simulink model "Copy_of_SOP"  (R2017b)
settings: Solver=FixedStepDiscrete  StartTime=0.0  StopTime=10.0  FixedStep=0.01  RelTol=1e-3  EnableMultiTasking=on
undefined symbols (not defined in the file): ASWTYPE_FALSE, ASWTYPE_TRUE, CcSOP_CellVoltLowLevel1Time_MS, CcSOP_CellVoltRngDiff_V, CcSOP_CellVoltRngDiffHeal_V, CcSOP_CellVoltRngHighTime_MS, CcSOP_CellVoltRngLowTime_MS, CcSOP_CellVoltRngUpLimit_V, CcSOP_ChrgCurrFltChrgCurrThrld_A, CcSOP_ChrgCurrFltLevel1Factor_numb, CcSOP_ChrgCurrFltLevel1Time_ms, CcSOP_ChrgCurrFltLevel2Factor_numb, CcSOP_ChrgCurrFltLevel2Time_ms, CcSOP_ChrgCurrFltLevel3Factor_numb, CcSOP_ChrgCurrFltLevel3Time_ms, CcSOP_ChrgFloorPwrLimit_kW, CcSOP_ChrgFltHysCurr_A, CcSOP_ChrgHighFactor_numb, CcSOP_ChrgLowFactor_numb, CcSOP_ChrgPwrFltPeakPwrThrld_kW, CcSOP_DisChrgEmerPwrLimit_kW, CcSOP_DisChrgFloorPwrLimit_kW, CcSOP_DisChrgHighFactor_numb, CcSOP_DisChrgLowFactor_numb, CcSOP_DischrgPwrFltLevel1Factor_numb, CcSOP_DischrgPwrFltLevel1Time_ms, CcSOP_DischrgPwrFltLevel2Factor_numb, CcSOP_DischrgPwrFltLevel2Time_ms, CcSOP_DischrgPwrFltLevel3Factor_numb, CcSOP_DischrgPwrFltLevel3Time_ms, CcSOP_DischrgPwrFltPeakPwrThrld_kW, CcSOP_DischrgPwrFltThrld_kW, CcSOP_DisChrgPwrLimit_kW, CcSOP_FeedbackPwrFltLevel1Factor_numb, CcSOP_FeedbackPwrFltLevel1Time_ms, CcSOP_FeedbackPwrFltLevel2Factor_numb, CcSOP_FeedbackPwrFltLevel2Time_ms, CcSOP_FeedbackPwrFltLevel3Factor_numb, CcSOP_FeedbackPwrFltLevel3Time_ms, CcSOP_FeedbackPwrFltThrld_kW, CcSOP_FltLimitPwrFactorLevel1_numb, CcSOP_FltLimitPwrFactorLevel2_numb, CcSOP_LookupTablePwrFactor_pct, CcSOP_MaxChrgCurrLimitFactorLevel2_numb, CcSOP_MaxCurrTableLarger_ms, CcSOP_MaxCurrTableSmaller_ms, CcSOP_PeakPowerRunTime_ms, CcSOP_PwrDownDisDetLevel1Speed_kW, CcSOP_PwrDownDisFloorFactor_numb, CcSOP_PwrDownDisFloorSpeed_kW, CcSOP_PwrDownSpeed_kW, CcSOP_PwrFltHysFactor_numb, CcSOP_PwrFltThrldTestMode_kW, CcSOP_PwrUpSpeed_kW, Enum_CTCCtrCtlConnMode, Enum_CTCCtrCtlState, Enum_MSMBMUState, Enum_SOPChrgPwrState, Enum_SOPDisChrgPwrState, Enum_SOPFeedbackPwrState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
libraries: AIWAYS_Powertrain_BMS_lib x77
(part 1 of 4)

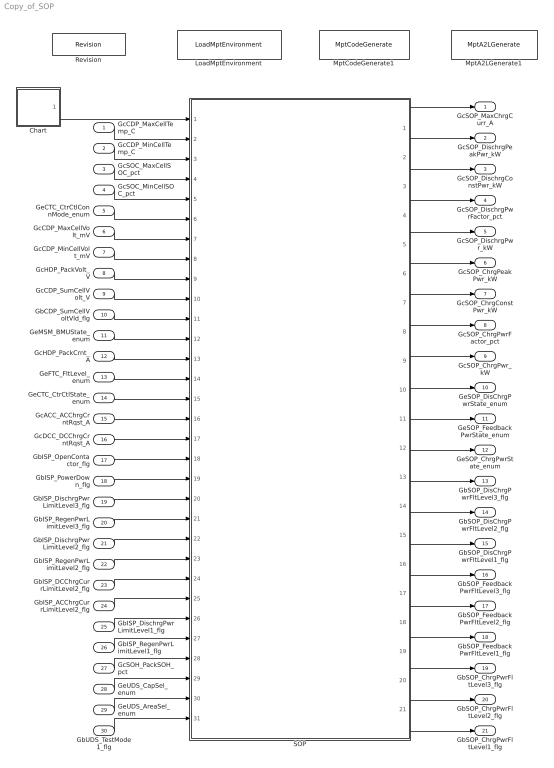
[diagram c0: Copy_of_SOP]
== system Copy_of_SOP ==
  GcCDP_MaxCellTemp_C : Inport
  GcCDP_MinCellTemp_C : Inport  Port=2
  GcSOC_MaxCellSOC_pct : Inport  Port=3
  GcSOC_MinCellSOC_pct : Inport  Port=4
  GeCTC_CtrCtlConnMode_enum : Inport  Port=5
  GcCDP_MaxCellVolt_mV : Inport  Port=6
  GcCDP_MinCellVolt_mV : Inport  Port=7
  GcHDP_PackVolt_V : Inport  Port=8
  GcCDP_SumCellVolt_V : Inport  Port=9
  GbCDP_SumCellVoltVld_flg : Inport  Port=10
  GeMSM_BMUState_enum : Inport  Port=11
  GcHDP_PackCrnt_A : Inport  Port=12
  GeFTC_FltLevel_enum : Inport  Port=13
  GeCTC_CtrCtlState_enum : Inport  Port=14
  GcACC_ACChrgCrntRqst_A : Inport  Port=15
  GcDCC_DCChrgCrntRqst_A : Inport  Port=16
  GbISP_OpenContactor_flg : Inport  Port=17
  GbISP_PowerDown_flg : Inport  Port=18
  GbISP_DischrgPwrLimitLevel3_flg : Inport  Port=19
  GbISP_RegenPwrLimitLevel3_flg : Inport  Port=20
  GbISP_DischrgPwrLimitLevel2_flg : Inport  Port=21
  GbISP_RegenPwrLimitLevel2_flg : Inport  Port=22
  GbISP_DCChrgCurrLimitLevel2_flg : Inport  Port=23
  GbISP_ACChrgCurrLimitLevel2_flg : Inport  Port=24
  GbISP_DischrgPwrLimitLevel1_flg : Inport  Port=25
  GbISP_RegenPwrLimitLevel1_flg : Inport  Port=26
  GcSOH_PackSOH_pct : Inport  Port=27
  GeUDS_CapSel_enum : Inport  Port=28
  GeUDS_AreaSel_enum : Inport  Port=29
  GbUDS_TestMode1_flg : Inport  Port=30
  Chart : Stateflow chart  TreatAsAtomicUnit=on
  LoadMptEnvironment : AIWAYS_Powertrain_BMS_lib/Config/LoadMptEnvironment  ProjectName=Comm  SuppierID=NewPlatformUAES
  MptA2LGenerate1 : AIWAYS_Powertrain_BMS_lib/Config/MptA2LGenerate  SystemSampleTime=-1
  MptCodeGenerate1 : AIWAYS_Powertrain_BMS_lib/Config/MptCodeGenerate  SystemSampleTime=-1
  Revision : AIWAYS_Powertrain_BMS_lib/Config/Revision  curVersion='M110C115R104'  newVersion='M110C115R104'
  SOP : Subsystem
  GcSOP_MaxChrgCurr_A : Outport
  GcSOP_DischrgPeakPwr_kW : Outport  Port=2
  GcSOP_DischrgConstPwr_kW : Outport  Port=3
  GcSOP_DischrgPwrFactor_pct : Outport  Port=4
  GcSOP_DischrgPwr_kW : Outport  Port=5
  GcSOP_ChrgPeakPwr_kW : Outport  Port=6
  GcSOP_ChrgConstPwr_kW : Outport  Port=7
  GcSOP_ChrgPwrFactor_pct : Outport  Port=8
  GcSOP_ChrgPwr_kW : Outport  Port=9
  GeSOP_DisChrgPwrState_enum : Outport  Port=10
  GeSOP_FeedbackPwrState_enum : Outport  Port=11
  GeSOP_ChrgPwrState_enum : Outport  Port=12
  GbSOP_DisChrgPwrFltLevel3_flg : Outport  Port=13
  GbSOP_DisChrgPwrFltLevel2_flg : Outport  Port=14
  GbSOP_DisChrgPwrFltLevel1_flg : Outport  Port=15
  GbSOP_FeedbackPwrFltLevel3_flg : Outport  Port=16
  GbSOP_FeedbackPwrFltLevel2_flg : Outport  Port=17
  GbSOP_FeedbackPwrFltLevel1_flg : Outport  Port=18
  GbSOP_ChrgPwrFltLevel3_flg : Outport  Port=19
  GbSOP_ChrgPwrFltLevel2_flg : Outport  Port=20
  GbSOP_ChrgPwrFltLevel1_flg : Outport  Port=21
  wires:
  Chart/1(SOP_SOP_10ms()) -> SOP/1(SOP_SOP_10ms)
  GcCDP_MaxCellTemp_C/1 -> SOP/2(GcCDP_MaxCellTemp_C)
  GcCDP_MinCellTemp_C/1 -> SOP/3(GcCDP_MinCellTemp_C)
  GcSOC_MaxCellSOC_pct/1 -> SOP/4(GcSOC_MaxCellSOC_pct)
  GcSOC_MinCellSOC_pct/1 -> SOP/5(GcSOC_MinCellSOC_pct)
  GeCTC_CtrCtlConnMode_enum/1 -> SOP/6(GeCTC_CtrCtlConnMode_enum)
  GcCDP_MaxCellVolt_mV/1 -> SOP/7(GcCDP_MaxCellVolt_mV)
  GcCDP_MinCellVolt_mV/1 -> SOP/8(GcCDP_MinCellVolt_mV)
  GcHDP_PackVolt_V/1 -> SOP/9(GcHDP_PackVolt_V)
  GcCDP_SumCellVolt_V/1 -> SOP/10(GcCDP_SumCellVolt_V)
  GbCDP_SumCellVoltVld_flg/1 -> SOP/11(GbCDP_SumCellVoltVld_flg)
  GeMSM_BMUState_enum/1 -> SOP/12(GeMSM_BMUState_enum)
  GcHDP_PackCrnt_A/1 -> SOP/13(GcHDP_PackCrnt_A)
  GeFTC_FltLevel_enum/1 -> SOP/14(GeFTC_FltLevel_enum)
  GeCTC_CtrCtlState_enum/1 -> SOP/15(GeCTC_CtrCtlState_enum)
  GcACC_ACChrgCrntRqst_A/1 -> SOP/16(GcACC_ACChrgCrntRqst_A)
  GcDCC_DCChrgCrntRqst_A/1 -> SOP/17(GcDCC_DCChrgCrntRqst_A)
  SOP/1(GcSOP_MaxChrgCurr_A) -> GcSOP_MaxChrgCurr_A/1
  SOP/2(GcSOP_DischrgPeakPwr_kW) -> GcSOP_DischrgPeakPwr_kW/1
  SOP/3(GcSOP_DischrgConstPwr_kW) -> GcSOP_DischrgConstPwr_kW/1
  SOP/4(GcSOP_DischrgPwrFactor_pct) -> GcSOP_DischrgPwrFactor_pct/1
  SOP/5(GcSOP_DischrgPwr_kW) -> GcSOP_DischrgPwr_kW/1
  SOP/6(GcSOP_ChrgPeakPwr_kW) -> GcSOP_ChrgPeakPwr_kW/1
  SOP/7(GcSOP_ChrgConstPwr_kW) -> GcSOP_ChrgConstPwr_kW/1
  SOP/8(GcSOP_ChrgPwrFactor_pct) -> GcSOP_ChrgPwrFactor_pct/1
  SOP/9(GcSOP_ChrgPwr_kW) -> GcSOP_ChrgPwr_kW/1
  SOP/10(GeSOP_DisChrgPwrState_enum) -> GeSOP_DisChrgPwrState_enum/1
  SOP/11(GeSOP_FeedbackPwrState_enum) -> GeSOP_FeedbackPwrState_enum/1
  SOP/12(GeSOP_ChrgPwrState_enum) -> GeSOP_ChrgPwrState_enum/1
  GbISP_OpenContactor_flg/1 -> SOP/18(GbISP_OpenContactor_flg)
  GbISP_PowerDown_flg/1 -> SOP/19(GbISP_PowerDown_flg)
  GbISP_DischrgPwrLimitLevel3_flg/1 -> SOP/20(GbISP_DischrgPwrLimitLevel3_flg)
  GbISP_RegenPwrLimitLevel3_flg/1 -> SOP/21(GbISP_RegenPwrLimitLevel3_flg)
  GbISP_DischrgPwrLimitLevel2_flg/1 -> SOP/22(GbISP_DischrgPwrLimitLevel2_flg)
  GbISP_RegenPwrLimitLevel2_flg/1 -> SOP/23(GbISP_RegenPwrLimitLevel2_flg)
  GbISP_DCChrgCurrLimitLevel2_flg/1 -> SOP/24(GbISP_DCChrgCurrLimitLevel2_flg)
  GbISP_ACChrgCurrLimitLevel2_flg/1 -> SOP/25(GbISP_ACChrgCurrLimitLevel2_flg)
  GbISP_DischrgPwrLimitLevel1_flg/1 -> SOP/26(GbISP_DischrgPwrLimitLevel1_flg)
  GbISP_RegenPwrLimitLevel1_flg/1 -> SOP/27(GbISP_RegenPwrLimitLevel1_flg)
  SOP/13(GbSOP_DisChrgPwrFltLevel3_flg) -> GbSOP_DisChrgPwrFltLevel3_flg/1
  SOP/14(GbSOP_DisChrgPwrFltLevel2_flg) -> GbSOP_DisChrgPwrFltLevel2_flg/1
  SOP/15(GbSOP_DisChrgPwrFltLevel1_flg) -> GbSOP_DisChrgPwrFltLevel1_flg/1
  SOP/16(GbSOP_FeedbackPwrFltLevel3_flg) -> GbSOP_FeedbackPwrFltLevel3_flg/1
  SOP/17(GbSOP_FeedbackPwrFltLevel2_flg) -> GbSOP_FeedbackPwrFltLevel2_flg/1
  SOP/18(GbSOP_FeedbackPwrFltLevel1_flg) -> GbSOP_FeedbackPwrFltLevel1_flg/1
  SOP/19(GbSOP_ChrgPwrFltLevel3_flg) -> GbSOP_ChrgPwrFltLevel3_flg/1
  SOP/20(GbSOP_ChrgPwrFltLevel2_flg) -> GbSOP_ChrgPwrFltLevel2_flg/1
  SOP/21(GbSOP_ChrgPwrFltLevel1_flg) -> GbSOP_ChrgPwrFltLevel1_flg/1
  GcSOH_PackSOH_pct/1 -> SOP/28(GcSOH_PackSOH_pct)
  GeUDS_CapSel_enum/1 -> SOP/29(GeUDS_CapSel_enum)
  GeUDS_AreaSel_enum/1 -> SOP/30(GeUDS_AreaSel_enum)
  GbUDS_TestMode1_flg/1 -> SOP/31(GbUDS_TestMode1_flg)

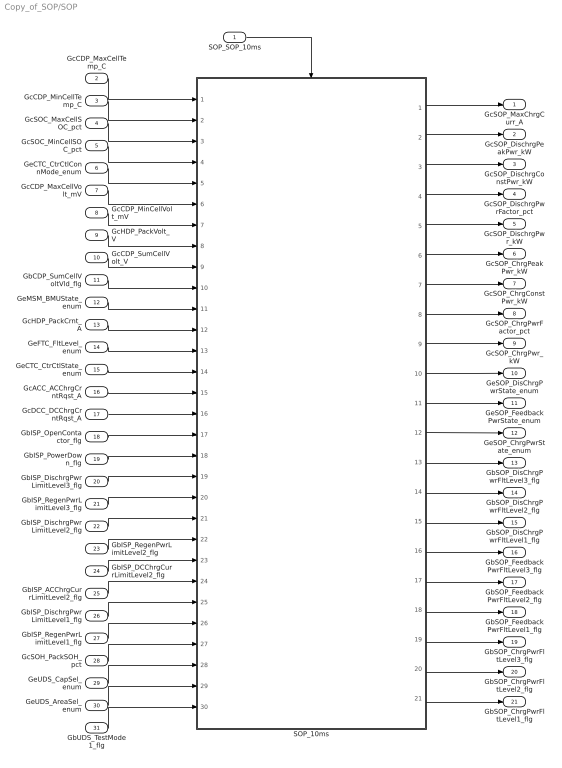
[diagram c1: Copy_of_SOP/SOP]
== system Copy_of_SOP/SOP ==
  SOP_SOP_10ms : Inport
  GcCDP_MaxCellTemp_C : Inport  Port=2
  GcCDP_MinCellTemp_C : Inport  Port=3
  GcSOC_MaxCellSOC_pct : Inport  Port=4
  GcSOC_MinCellSOC_pct : Inport  Port=5
  GeCTC_CtrCtlConnMode_enum : Inport  Port=6
  GcCDP_MaxCellVolt_mV : Inport  Port=7
  GcCDP_MinCellVolt_mV : Inport  Port=8
  GcHDP_PackVolt_V : Inport  Port=9
  GcCDP_SumCellVolt_V : Inport  Port=10
  GbCDP_SumCellVoltVld_flg : Inport  Port=11
  GeMSM_BMUState_enum : Inport  Port=12
  GcHDP_PackCrnt_A : Inport  Port=13
  GeFTC_FltLevel_enum : Inport  Port=14
  GeCTC_CtrCtlState_enum : Inport  Port=15
  GcACC_ACChrgCrntRqst_A : Inport  Port=16
  GcDCC_DCChrgCrntRqst_A : Inport  Port=17
  GbISP_OpenContactor_flg : Inport  Port=18
  GbISP_PowerDown_flg : Inport  Port=19
  GbISP_DischrgPwrLimitLevel3_flg : Inport  Port=20
  GbISP_RegenPwrLimitLevel3_flg : Inport  Port=21
  GbISP_DischrgPwrLimitLevel2_flg : Inport  Port=22
  GbISP_RegenPwrLimitLevel2_flg : Inport  Port=23
  GbISP_DCChrgCurrLimitLevel2_flg : Inport  Port=24
  GbISP_ACChrgCurrLimitLevel2_flg : Inport  Port=25
  GbISP_DischrgPwrLimitLevel1_flg : Inport  Port=26
  GbISP_RegenPwrLimitLevel1_flg : Inport  Port=27
  GcSOH_PackSOH_pct : Inport  Port=28
  GeUDS_CapSel_enum : Inport  Port=29
  GeUDS_AreaSel_enum : Inport  Port=30
  GbUDS_TestMode1_flg : Inport  Port=31
  SOP_10ms : Subsystem  TreatAsAtomicUnit=on
  GcSOP_MaxChrgCurr_A : Outport
  GcSOP_DischrgPeakPwr_kW : Outport  Port=2
  GcSOP_DischrgConstPwr_kW : Outport  Port=3
  GcSOP_DischrgPwrFactor_pct : Outport  Port=4
  GcSOP_DischrgPwr_kW : Outport  Port=5
  GcSOP_ChrgPeakPwr_kW : Outport  Port=6
  GcSOP_ChrgConstPwr_kW : Outport  Port=7
  GcSOP_ChrgPwrFactor_pct : Outport  Port=8
  GcSOP_ChrgPwr_kW : Outport  Port=9
  GeSOP_DisChrgPwrState_enum : Outport  Port=10
  GeSOP_FeedbackPwrState_enum : Outport  Port=11
  GeSOP_ChrgPwrState_enum : Outport  Port=12
  GbSOP_DisChrgPwrFltLevel3_flg : Outport  Port=13
  GbSOP_DisChrgPwrFltLevel2_flg : Outport  Port=14
  GbSOP_DisChrgPwrFltLevel1_flg : Outport  Port=15
  GbSOP_FeedbackPwrFltLevel3_flg : Outport  Port=16
  GbSOP_FeedbackPwrFltLevel2_flg : Outport  Port=17
  GbSOP_FeedbackPwrFltLevel1_flg : Outport  Port=18
  GbSOP_ChrgPwrFltLevel3_flg : Outport  Port=19
  GbSOP_ChrgPwrFltLevel2_flg : Outport  Port=20
  GbSOP_ChrgPwrFltLevel1_flg : Outport  Port=21
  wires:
  SOP_SOP_10ms/1 -> SOP_10ms/Trigger
  SOP_10ms/1(GcSOP_MaxChrgCurr_A) -> GcSOP_MaxChrgCurr_A/1
  SOP_10ms/2(GcSOP_DischrgPeakPwr_kW) -> GcSOP_DischrgPeakPwr_kW/1
  SOP_10ms/3(GcSOP_DischrgConstPwr_kW) -> GcSOP_DischrgConstPwr_kW/1
  SOP_10ms/4(GcSOP_DischrgPwrFactor_pct) -> GcSOP_DischrgPwrFactor_pct/1
  SOP_10ms/5(GcSOP_DischrgPwr_kW) -> GcSOP_DischrgPwr_kW/1
  SOP_10ms/6(GcSOP_ChrgPeakPwr_kW) -> GcSOP_ChrgPeakPwr_kW/1
  SOP_10ms/7(GcSOP_ChrgConstPwr_kW) -> GcSOP_ChrgConstPwr_kW/1
  SOP_10ms/8(GcSOP_ChrgPwrFactor_pct) -> GcSOP_ChrgPwrFactor_pct/1
  SOP_10ms/9(GcSOP_ChrgPwr_kW) -> GcSOP_ChrgPwr_kW/1
  SOP_10ms/10(GeSOP_DisChrgPwrState_enum) -> GeSOP_DisChrgPwrState_enum/1
  SOP_10ms/11(GeSOP_FeedbackPwrState_enum) -> GeSOP_FeedbackPwrState_enum/1
  SOP_10ms/12(GeSOP_ChrgPwrState_enum) -> GeSOP_ChrgPwrState_enum/1
  GcCDP_MaxCellTemp_C/1 -> SOP_10ms/1(GcCDP_MaxCellTemp_C)
  GcCDP_MinCellTemp_C/1 -> SOP_10ms/2(GcCDP_MinCellTemp_C)
  GcSOC_MaxCellSOC_pct/1 -> SOP_10ms/3(GcSOC_MaxCellSOC_pct)
  GcSOC_MinCellSOC_pct/1 -> SOP_10ms/4(GcSOC_MinCellSOC_pct)
  GeCTC_CtrCtlConnMode_enum/1 -> SOP_10ms/5(GeCTC_CtrCtlConnMode_enum)
  GcCDP_MaxCellVolt_mV/1 -> SOP_10ms/6(GcCDP_MaxCellVolt_mV)
  GcCDP_MinCellVolt_mV/1 -> SOP_10ms/7(GcCDP_MinCellVolt_mV)
  GcHDP_PackVolt_V/1 -> SOP_10ms/8(GcHDP_PackVolt_V)
  GcCDP_SumCellVolt_V/1 -> SOP_10ms/9(GcCDP_SumCellVolt_V)
  GbCDP_SumCellVoltVld_flg/1 -> SOP_10ms/10(GbCDP_SumCellVoltVld_flg)
  GeMSM_BMUState_enum/1 -> SOP_10ms/11(GeMSM_BMUState_enum)
  GcHDP_PackCrnt_A/1 -> SOP_10ms/12(GcHDP_PackCrnt_A)
  GeFTC_FltLevel_enum/1 -> SOP_10ms/13(GeFTC_FltLevel_enum)
  GeCTC_CtrCtlState_enum/1 -> SOP_10ms/14(GeCTC_CtrCtlState_enum)
  GcACC_ACChrgCrntRqst_A/1 -> SOP_10ms/15(GcACC_ACChrgCrntRqst_A)
  GcDCC_DCChrgCrntRqst_A/1 -> SOP_10ms/16(GcDCC_DCChrgCrntRqst_A)
  GbISP_OpenContactor_flg/1 -> SOP_10ms/17(GbISP_OpenContactor_flg)
  GbISP_PowerDown_flg/1 -> SOP_10ms/18(GbISP_PowerDown_flg)
  GbISP_DischrgPwrLimitLevel3_flg/1 -> SOP_10ms/19(GbISP_DischrgPwrLimitLevel3_flg)
  GbISP_RegenPwrLimitLevel3_flg/1 -> SOP_10ms/20(GbISP_RegenPwrLimitLevel3_flg)
  GbISP_DischrgPwrLimitLevel2_flg/1 -> SOP_10ms/21(GbISP_DischrgPwrLimitLevel2_flg)
  GbISP_RegenPwrLimitLevel2_flg/1 -> SOP_10ms/22(GbISP_RegenPwrLimitLevel2_flg)
  GbISP_DCChrgCurrLimitLevel2_flg/1 -> SOP_10ms/23(GbISP_DCChrgCurrLimitLevel2_flg)
  GbISP_ACChrgCurrLimitLevel2_flg/1 -> SOP_10ms/24(GbISP_ACChrgCurrLimitLevel2_flg)
  GbISP_DischrgPwrLimitLevel1_flg/1 -> SOP_10ms/25(GbISP_DischrgPwrLimitLevel1_flg)
  GbISP_RegenPwrLimitLevel1_flg/1 -> SOP_10ms/26(GbISP_RegenPwrLimitLevel1_flg)
  SOP_10ms/13(GbSOP_DisChrgPwrFltLevel3_flg) -> GbSOP_DisChrgPwrFltLevel3_flg/1
  SOP_10ms/14(GbSOP_DisChrgPwrFltLevel2_flg) -> GbSOP_DisChrgPwrFltLevel2_flg/1
  SOP_10ms/15(GbSOP_DisChrgPwrFltLevel1_flg) -> GbSOP_DisChrgPwrFltLevel1_flg/1
  SOP_10ms/16(GbSOP_FeedbackPwrFltLevel3_flg) -> GbSOP_FeedbackPwrFltLevel3_flg/1
  SOP_10ms/17(GbSOP_FeedbackPwrFltLevel2_flg) -> GbSOP_FeedbackPwrFltLevel2_flg/1
  SOP_10ms/18(GbSOP_FeedbackPwrFltLevel1_flg) -> GbSOP_FeedbackPwrFltLevel1_flg/1
  SOP_10ms/19(GbSOP_ChrgPwrFltLevel3_flg) -> GbSOP_ChrgPwrFltLevel3_flg/1
  SOP_10ms/20(GbSOP_ChrgPwrFltLevel2_flg) -> GbSOP_ChrgPwrFltLevel2_flg/1
  SOP_10ms/21(GbSOP_ChrgPwrFltLevel1_flg) -> GbSOP_ChrgPwrFltLevel1_flg/1
  GcSOH_PackSOH_pct/1 -> SOP_10ms/27(GcSOH_PackSOH_pct)
  GeUDS_CapSel_enum/1 -> SOP_10ms/28(GeUDS_CapSel_enum)
  GeUDS_AreaSel_enum/1 -> SOP_10ms/29(GeUDS_AreaSel_enum)
  GbUDS_TestMode1_flg/1 -> SOP_10ms/30(GbUDS_TestMode1_flg)

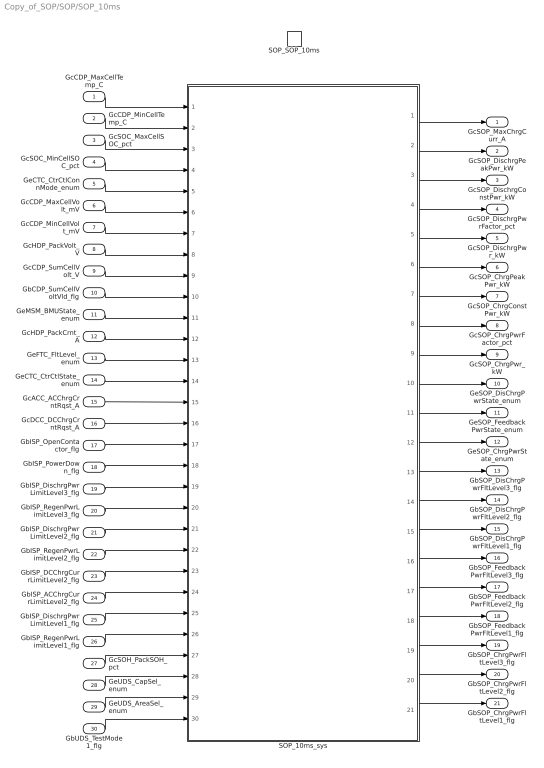
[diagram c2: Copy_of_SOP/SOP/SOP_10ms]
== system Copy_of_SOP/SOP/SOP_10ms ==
  GcCDP_MaxCellTemp_C : Inport
  GcCDP_MinCellTemp_C : Inport  Port=2
  GcSOC_MaxCellSOC_pct : Inport  Port=3
  GcSOC_MinCellSOC_pct : Inport  Port=4
  GeCTC_CtrCtlConnMode_enum : Inport  Port=5
  GcCDP_MaxCellVolt_mV : Inport  Port=6
  GcCDP_MinCellVolt_mV : Inport  Port=7
  GcHDP_PackVolt_V : Inport  Port=8
  GcCDP_SumCellVolt_V : Inport  Port=9
  GbCDP_SumCellVoltVld_flg : Inport  Port=10
  GeMSM_BMUState_enum : Inport  Port=11
  GcHDP_PackCrnt_A : Inport  Port=12
  GeFTC_FltLevel_enum : Inport  Port=13
  GeCTC_CtrCtlState_enum : Inport  Port=14
  GcACC_ACChrgCrntRqst_A : Inport  Port=15
  GcDCC_DCChrgCrntRqst_A : Inport  Port=16
  GbISP_OpenContactor_flg : Inport  Port=17
  GbISP_PowerDown_flg : Inport  Port=18
  GbISP_DischrgPwrLimitLevel3_flg : Inport  Port=19
  GbISP_RegenPwrLimitLevel3_flg : Inport  Port=20
  GbISP_DischrgPwrLimitLevel2_flg : Inport  Port=21
  GbISP_RegenPwrLimitLevel2_flg : Inport  Port=22
  GbISP_DCChrgCurrLimitLevel2_flg : Inport  Port=23
  GbISP_ACChrgCurrLimitLevel2_flg : Inport  Port=24
  GbISP_DischrgPwrLimitLevel1_flg : Inport  Port=25
  GbISP_RegenPwrLimitLevel1_flg : Inport  Port=26
  GcSOH_PackSOH_pct : Inport  Port=27
  GeUDS_CapSel_enum : Inport  Port=28
  GeUDS_AreaSel_enum : Inport  Port=29
  GbUDS_TestMode1_flg : Inport  Port=30
  SOP_SOP_10ms : TriggerPort  TriggerType=function-call  VariantControl=(inherit)  SampleTime=-1
  SOP_10ms_sys : Subsystem  Tag=MTestTObj
  GcSOP_MaxChrgCurr_A : Outport
  GcSOP_DischrgPeakPwr_kW : Outport  Port=2
  GcSOP_DischrgConstPwr_kW : Outport  Port=3
  GcSOP_DischrgPwrFactor_pct : Outport  Port=4
  GcSOP_DischrgPwr_kW : Outport  Port=5
  GcSOP_ChrgPeakPwr_kW : Outport  Port=6
  GcSOP_ChrgConstPwr_kW : Outport  Port=7
  GcSOP_ChrgPwrFactor_pct : Outport  Port=8
  GcSOP_ChrgPwr_kW : Outport  Port=9
  GeSOP_DisChrgPwrState_enum : Outport  Port=10
  GeSOP_FeedbackPwrState_enum : Outport  Port=11
  GeSOP_ChrgPwrState_enum : Outport  Port=12
  GbSOP_DisChrgPwrFltLevel3_flg : Outport  Port=13
  GbSOP_DisChrgPwrFltLevel2_flg : Outport  Port=14
  GbSOP_DisChrgPwrFltLevel1_flg : Outport  Port=15
  GbSOP_FeedbackPwrFltLevel3_flg : Outport  Port=16
  GbSOP_FeedbackPwrFltLevel2_flg : Outport  Port=17
  GbSOP_FeedbackPwrFltLevel1_flg : Outport  Port=18
  GbSOP_ChrgPwrFltLevel3_flg : Outport  Port=19
  GbSOP_ChrgPwrFltLevel2_flg : Outport  Port=20
  GbSOP_ChrgPwrFltLevel1_flg : Outport  Port=21
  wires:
  GcSOC_MinCellSOC_pct/1 -> SOP_10ms_sys/4(GcSOC_MinCellSOC_pct)
  GcSOC_MaxCellSOC_pct/1 -> SOP_10ms_sys/3(GcSOC_MaxCellSOC_pct)
  GcCDP_MinCellTemp_C/1 -> SOP_10ms_sys/2(GcCDP_MinCellTemp_C)
  GcCDP_MaxCellTemp_C/1 -> SOP_10ms_sys/1(GcCDP_MaxCellTemp_C)
  GeCTC_CtrCtlConnMode_enum/1 -> SOP_10ms_sys/5(GeCTC_CtrCtlConnMode_enum)
  GcHDP_PackVolt_V/1 -> SOP_10ms_sys/8(GcHDP_PackVolt_V)
  GeMSM_BMUState_enum/1 -> SOP_10ms_sys/11(GeMSM_BMUState_enum)
  GeCTC_CtrCtlState_enum/1 -> SOP_10ms_sys/14(GeCTC_CtrCtlState_enum)
  GeFTC_FltLevel_enum/1 -> SOP_10ms_sys/13(GeFTC_FltLevel_enum)
  GcHDP_PackCrnt_A/1 -> SOP_10ms_sys/12(GcHDP_PackCrnt_A)
  SOP_10ms_sys/1(GcSOP_MaxChrgCurr_A) -> GcSOP_MaxChrgCurr_A/1
  SOP_10ms_sys/2(GcSOP_DischrgPeakPwr_kW) -> GcSOP_DischrgPeakPwr_kW/1
  SOP_10ms_sys/3(GcSOP_DischrgConstPwr_kW) -> GcSOP_DischrgConstPwr_kW/1
  SOP_10ms_sys/4(GcSOP_DischrgPwrFactor_pct) -> GcSOP_DischrgPwrFactor_pct/1
  SOP_10ms_sys/5(GcSOP_DischrgPwr_kW) -> GcSOP_DischrgPwr_kW/1
  SOP_10ms_sys/6(GcSOP_ChrgPeakPwr_kW) -> GcSOP_ChrgPeakPwr_kW/1
  SOP_10ms_sys/7(GcSOP_ChrgConstPwr_kW) -> GcSOP_ChrgConstPwr_kW/1
  SOP_10ms_sys/8(GcSOP_ChrgPwrFactor_pct) -> GcSOP_ChrgPwrFactor_pct/1
  SOP_10ms_sys/9(GcSOP_ChrgPwr_kW) -> GcSOP_ChrgPwr_kW/1
  GcACC_ACChrgCrntRqst_A/1 -> SOP_10ms_sys/15(GcACC_ACChrgCrntRqst_A)
  GcDCC_DCChrgCrntRqst_A/1 -> SOP_10ms_sys/16(GcDCC_DCChrgCrntRqst_A)
  SOP_10ms_sys/10(GeSOP_DisChrgPwrState_enum) -> GeSOP_DisChrgPwrState_enum/1
  SOP_10ms_sys/11(GeSOP_FeedbackPwrState_enum) -> GeSOP_FeedbackPwrState_enum/1
  SOP_10ms_sys/12(GeSOP_ChrgPwrState_enum) -> GeSOP_ChrgPwrState_enum/1
  GcCDP_MaxCellVolt_mV/1 -> SOP_10ms_sys/6(GcCDP_MaxCellVolt_mV)
  GcCDP_MinCellVolt_mV/1 -> SOP_10ms_sys/7(GcCDP_MinCellVolt_mV)
  GcCDP_SumCellVolt_V/1 -> SOP_10ms_sys/9(GcCDP_SumCellVolt_V)
  GbCDP_SumCellVoltVld_flg/1 -> SOP_10ms_sys/10(GbCDP_SumCellVoltVld_flg)
  GbISP_OpenContactor_flg/1 -> SOP_10ms_sys/17(GbISP_OpenContactor_flg)
  GbISP_PowerDown_flg/1 -> SOP_10ms_sys/18(GbISP_PowerDown_flg)
  GbISP_DischrgPwrLimitLevel3_flg/1 -> SOP_10ms_sys/19(GbISP_DischrgPwrLimitLevel3_flg)
  GbISP_RegenPwrLimitLevel3_flg/1 -> SOP_10ms_sys/20(GbISP_RegenPwrLimitLevel3_flg)
  GbISP_DischrgPwrLimitLevel2_flg/1 -> SOP_10ms_sys/21(GbISP_DischrgPwrLimitLevel2_flg)
  GbISP_RegenPwrLimitLevel2_flg/1 -> SOP_10ms_sys/22(GbISP_RegenPwrLimitLevel2_flg)
  GbISP_DCChrgCurrLimitLevel2_flg/1 -> SOP_10ms_sys/23(GbISP_DCChrgCurrLimitLevel2_flg)
  GbISP_ACChrgCurrLimitLevel2_flg/1 -> SOP_10ms_sys/24(GbISP_ACChrgCurrLimitLevel2_flg)
  GbISP_DischrgPwrLimitLevel1_flg/1 -> SOP_10ms_sys/25(GbISP_DischrgPwrLimitLevel1_flg)
  GbISP_RegenPwrLimitLevel1_flg/1 -> SOP_10ms_sys/26(GbISP_RegenPwrLimitLevel1_flg)
  SOP_10ms_sys/13(GbSOP_DisChrgPwrFltLevel3_flg) -> GbSOP_DisChrgPwrFltLevel3_flg/1
  SOP_10ms_sys/14(GbSOP_DisChrgPwrFltLevel2_flg) -> GbSOP_DisChrgPwrFltLevel2_flg/1
  SOP_10ms_sys/15(GbSOP_DisChrgPwrFltLevel1_flg) -> GbSOP_DisChrgPwrFltLevel1_flg/1
  SOP_10ms_sys/16(GbSOP_FeedbackPwrFltLevel3_flg) -> GbSOP_FeedbackPwrFltLevel3_flg/1
  SOP_10ms_sys/17(GbSOP_FeedbackPwrFltLevel2_flg) -> GbSOP_FeedbackPwrFltLevel2_flg/1
  SOP_10ms_sys/18(GbSOP_FeedbackPwrFltLevel1_flg) -> GbSOP_FeedbackPwrFltLevel1_flg/1
  SOP_10ms_sys/19(GbSOP_ChrgPwrFltLevel3_flg) -> GbSOP_ChrgPwrFltLevel3_flg/1
  SOP_10ms_sys/20(GbSOP_ChrgPwrFltLevel2_flg) -> GbSOP_ChrgPwrFltLevel2_flg/1
  SOP_10ms_sys/21(GbSOP_ChrgPwrFltLevel1_flg) -> GbSOP_ChrgPwrFltLevel1_flg/1
  GcSOH_PackSOH_pct/1 -> SOP_10ms_sys/27(GcSOH_PackSOH_pct)
  GeUDS_CapSel_enum/1 -> SOP_10ms_sys/28(GeUDS_CapSel_enum)
  GeUDS_AreaSel_enum/1 -> SOP_10ms_sys/29(GeUDS_AreaSel_enum)
  GbUDS_TestMode1_flg/1 -> SOP_10ms_sys/30(GbUDS_TestMode1_flg)

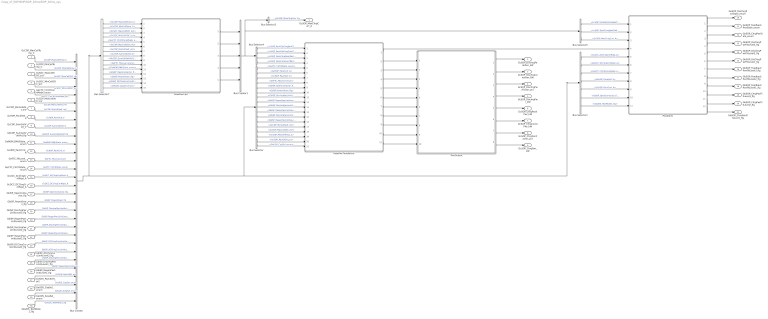
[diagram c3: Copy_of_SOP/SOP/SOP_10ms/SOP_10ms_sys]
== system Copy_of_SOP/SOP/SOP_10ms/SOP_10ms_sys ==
  GcCDP_MaxCellTemp_C : Inport
  GcCDP_MinCellTemp_C : Inport  Port=2
  GcSOC_MaxCellSOC_pct : Inport  Port=3
  GcSOC_MinCellSOC_pct : Inport  Port=4
  GeCTC_CtrCtlConnMode_enum : Inport  Port=5
  GcCDP_MaxCellVolt_mV : Inport  Port=6
  GcCDP_MinCellVolt_mV : Inport  Port=7
  GcHDP_PackVolt_V : Inport  Port=8
  GcCDP_SumCellVolt_V : Inport  Port=9
  GbCDP_SumCellVoltVld_flg : Inport  Port=10
  GeMSM_BMUState_enum : Inport  Port=11
  GcHDP_PackCrnt_A : Inport  Port=12
  GeFTC_FltLevel_enum : Inport  Port=13
  GeCTC_CtrCtlState_enum : Inport  Port=14
  GcACC_ACChrgCrntRqst_A : Inport  Port=15
  GcDCC_DCChrgCrntRqst_A : Inport  Port=16
  GbISP_OpenContactor_flg : Inport  Port=17
  GbISP_PowerDown_flg : Inport  Port=18
  GbISP_DischrgPwrLimitLevel3_flg : Inport  Port=19
  GbISP_RegenPwrLimitLevel3_flg : Inport  Port=20
  GbISP_DischrgPwrLimitLevel2_flg : Inport  Port=21
  GbISP_RegenPwrLimitLevel2_flg : Inport  Port=22
  GbISP_DCChrgCurrLimitLevel2_flg : Inport  Port=23
  GbISP_ACChrgCurrLimitLevel2_flg : Inport  Port=24
  GbISP_DischrgPwrLimitLevel1_flg : Inport  Port=25
  GbISP_RegenPwrLimitLevel1_flg : Inport  Port=26
  GcSOH_PackSOH_pct : Inport  Port=27
  GeUDS_CapSel_enum : Inport  Port=28
  GeUDS_AreaSel_enum : Inport  Port=29
  GbUDS_TestMode1_flg : Inport  Port=30
  Bus Creator : BusCreator  Inputs=30
  Bus Creator1 : BusCreator  Inputs=5
  Bus Selector : BusSelector  OutputSignals=GeCTC_CtrCtlState_enum,GcHDP_PackCrnt_A,GcHDP_PackVolt_V,GeFTC_FltLevel_enum,GbISP_OpenContactor_flg,GbISP_PowerDown_flg,GbISP_DischrgPwrLimitLevel3_flg,GbISP_RegenPwrLimitLevel3_flg,GbISP_DischrgPwrLimitLevel2_flg,GbISP_RegenPwrLimitLevel2_flg,GbISP_DischrgPwrLimitLevel1_flg,GbISP_RegenPwrLimitLevel1_flg,GcCDP_MinCellVolt_mV,GcCDP_MaxCellVolt_mV,GcCDP_MinCellTemp_C,GcSOH_PackSOH_pct,GeUDS_CapSel_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
  Bus Selector1 : BusSelector  OutputSignals=GcACC_ACChrgCrntRqst_A,GcDCC_DCChrgCrntRqst_A,GeCTC_CtrCtlConnMode_enum,GcHDP_PackVolt_V,GcHDP_PackCrnt_A,GbISP_OpenContactor_flg,GbUDS_TestMode1_flg
  Bus Selector3 : BusSelector  OutputSignals=GcSOP_MaxChrgCurr_A
  Bus Selector4 : BusSelector  OutputSignals=LcSOP_PackDisChrgPeakTablePwr_kW,LcSOP_PackDisChrgContTablePwr_kW,LcSOP_PackChrgPeakTablePwr_kW,LcSOP_PackChrgContTablePwr_kW
  Bus Selector5 : BusSelector  OutputSignals=LcSOP_PackDisChrgPeakTablePwr_kW,LcSOP_PackChrgPeakTablePwr_kW,GcSOP_MaxChrgCurr_A
  Bus Selector7 : BusSelector  OutputSignals=GcCDP_MaxCellTemp_C,GcCDP_MinCellTemp_C,GcSOC_MaxCellSOC_pct,GcSOC_MinCellSOC_pct,GeCTC_CtrCtlConnMode_enum,GcCDP_MaxCellVolt_mV,GcCDP_MinCellVolt_mV,GcCDP_SumCellVolt_V,GbCDP_SumCellVoltVld_flg,GeFTC_FltLevel_enum,GeMSM_BMUState_enum,GbISP_OpenContactor_flg,GbISP_PowerDown_flg,GbISP_DCChrgCurrLimitLevel2_flg,GeUDS_CapSel_enum
  PeakPwrCacl : Subsystem
  PeakPwrTimeFactor : Subsystem
  PwrAlarm : Subsystem
  PwrOutput : Subsystem
  GcSOP_MaxChrgCurr_A : Outport
  GcSOP_DischrgPeakPwr_kW : Outport  Port=2
  GcSOP_DischrgConstPwr_kW : Outport  Port=3
  GcSOP_DischrgPwrFactor_pct : Outport  Port=4
  GcSOP_DischrgPwr_kW : Outport  Port=5
  GcSOP_ChrgPeakPwr_kW : Outport  Port=6
  GcSOP_ChrgConstPwr_kW : Outport  Port=7
  GcSOP_ChrgPwrFactor_pct : Outport  Port=8
  GcSOP_ChrgPwr_kW : Outport  Port=9
  GeSOP_DisChrgPwrState_enum : Outport  Port=10
  GeSOP_FeedbackPwrState_enum : Outport  Port=11
  GeSOP_ChrgPwrState_enum : Outport  Port=12
  GbSOP_DisChrgPwrFltLevel3_flg : Outport  Port=13
  GbSOP_DisChrgPwrFltLevel2_flg : Outport  Port=14
  GbSOP_DisChrgPwrFltLevel1_flg : Outport  Port=15
  GbSOP_FeedbackPwrFltLevel3_flg : Outport  Port=16
  GbSOP_FeedbackPwrFltLevel2_flg : Outport  Port=17
  GbSOP_FeedbackPwrFltLevel1_flg : Outport  Port=18
  GbSOP_ChrgPwrFltLevel3_flg : Outport  Port=19
  GbSOP_ChrgPwrFltLevel2_flg : Outport  Port=20
  GbSOP_ChrgPwrFltLevel1_flg : Outport  Port=21
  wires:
  Bus Selector1/3 -> PwrAlarm/7(GeCTC_CtrCtlConnMode_enum)  "<GeCTC_CtrCtlConnMode_enum>"
  PwrAlarm/3(GeSOP_ChrgPwrState_enum) -> GeSOP_ChrgPwrState_enum/1
  PwrAlarm/2(GeSOP_FeedbackPwrState_enum) -> GeSOP_FeedbackPwrState_enum/1
  PwrAlarm/1(GeSOP_DisChrgPwrState_enum) -> GeSOP_DisChrgPwrState_enum/1
  Bus Selector1/4 -> PwrAlarm/8(GcHDP_PackVolt_V)  "<GcHDP_PackVolt_V>"
  Bus Selector1/5 -> PwrAlarm/9(GcHDP_PackCrnt_A)  "<GcHDP_PackCrnt_A>"
  PeakPwrCacl/5(GcSOP_MaxChrgCurr_A) -> Bus Creator1/5
  Bus Selector/2 -> PeakPwrTimeFactor/6(GcHDP_PackCrnt_A)  "<GcHDP_PackCrnt_A>"
  Bus Selector/4 -> PeakPwrTimeFactor/8(GeFTC_FltLevel_enum)  "<GeFTC_FltLevel_enum>"
  Bus Selector/3 -> PeakPwrTimeFactor/7(GcHDP_PackVolt_V)  "<GcHDP_PackVolt_V>"
  PwrOutput/2(GcSOP_DischrgConstPwr_kW) -> GcSOP_DischrgConstPwr_kW/1
  PwrOutput/3(GcSOP_DischrgPwrFactor_pct) -> GcSOP_DischrgPwrFactor_pct/1
  PwrOutput/4(GcSOP_DischrgPwr_kW) -> GcSOP_DischrgPwr_kW/1
  PwrOutput/5(GcSOP_ChrgPeakPwr_kW) -> GcSOP_ChrgPeakPwr_kW/1
  PwrOutput/6(GcSOP_ChrgConstPwr_kW) -> GcSOP_ChrgConstPwr_kW/1
  PwrOutput/7(GcSOP_ChrgPwrFactor_pct) -> GcSOP_ChrgPwrFactor_pct/1
  PwrOutput/8(GcSOP_ChrgPwr_kW) -> GcSOP_ChrgPwr_kW/1
  PwrOutput/1(GcSOP_DischrgPeakPwr_kW) -> GcSOP_DischrgPeakPwr_kW/1
  PeakPwrTimeFactor/7(LcSOP_ChrgPwrFactor_pct) -> PwrOutput/6(LcSOP_ChrgPwrFactor_pct)
  PeakPwrTimeFactor/6(LcSOP_DischrgPwrFactor_pct) -> PwrOutput/5(LcSOP_DischrgPwrFactor_pct)
  PeakPwrTimeFactor/5(LcSOP_ChrgContPwr_kW) -> PwrOutput/4(LcSOP_ChrgContPwr_kW)
  PeakPwrTimeFactor/4(LcSOP_ChrgPeakPwr_kW) -> PwrOutput/3(LcSOP_ChrgPeakPwr_kW)
  PeakPwrTimeFactor/3(LcSOP_DisChrgContPwr_kW) -> PwrOutput/2(LcSOP_DisChrgContPwr_kW)
  PeakPwrTimeFactor/2(LcSOP_DisChrgPeakPwr_kW) -> PwrOutput/1(LcSOP_DisChrgPeakPwr_kW)
  Bus Creator1/1 -> Bus Selector5/1, Bus Selector3/1, Bus Selector4/1
  Bus Selector5/1 -> PwrAlarm/1(LcSOP_PackDisChrgPeakTablePwr_kW)  "<LcSOP_PackDisChrgPeakTablePwr_kW>"
  Bus Selector5/2 -> PwrAlarm/2(LcSOP_PackChrgPeakTablePwr_kW)  "<LcSOP_PackChrgPeakTablePwr_kW>"
  PeakPwrCacl/1(LcSOP_PackDisChrgPeakTablePwr_kW) -> Bus Creator1/1
  PeakPwrCacl/2(LcSOP_PackDisChrgContTablePwr_kW) -> Bus Creator1/2
  PeakPwrCacl/3(LcSOP_PackChrgPeakTablePwr_kW) -> Bus Creator1/3
  PeakPwrCacl/4(LcSOP_PackChrgContTablePwr_kW) -> Bus Creator1/4
  Bus Selector4/1 -> PeakPwrTimeFactor/1(LcSOP_PackDisChrgPeakTablePwr_kW)  "<LcSOP_PackDisChrgPeakTablePwr_kW>"
  Bus Selector4/2 -> PeakPwrTimeFactor/2(LcSOP_PackDisChrgContTablePwr_kW)  "<LcSOP_PackDisChrgContTablePwr_kW>"
  Bus Selector4/3 -> PeakPwrTimeFactor/3(LcSOP_PackChrgPeakTablePwr_kW)  "<LcSOP_PackChrgPeakTablePwr_kW>"
  Bus Selector4/4 -> PeakPwrTimeFactor/4(LcSOP_PackChrgContTablePwr_kW)  "<LcSOP_PackChrgContTablePwr_kW>"
  Bus Selector/1 -> PeakPwrTimeFactor/5(GeCTC_CtrCtlState_enum)  "<GeCTC_CtrCtlState_enum>"
  GcCDP_MaxCellTemp_C/1 -> Bus Creator/1  "GcCDP_MaxCellTemp_C"
  GcCDP_MinCellTemp_C/1 -> Bus Creator/2  "GcCDP_MinCellTemp_C"
  GcSOC_MaxCellSOC_pct/1 -> Bus Creator/3  "GcSOC_MaxCellSOC_pct"
  GcSOC_MinCellSOC_pct/1 -> Bus Creator/4  "GcSOC_MinCellSOC_pct"
  GeCTC_CtrCtlConnMode_enum/1 -> Bus Creator/5  "GeCTC_CtrCtlConnMode_enum"
  GcCDP_MaxCellVolt_mV/1 -> Bus Creator/6  "GcCDP_MaxCellVolt_mV"
  GcCDP_MinCellVolt_mV/1 -> Bus Creator/7  "GcCDP_MinCellVolt_mV"
  GcHDP_PackVolt_V/1 -> Bus Creator/8  "GcHDP_PackVolt_V"
  GcCDP_SumCellVolt_V/1 -> Bus Creator/9  "GcCDP_SumCellVolt_V"
  GbCDP_SumCellVoltVld_flg/1 -> Bus Creator/10  "GbCDP_SumCellVoltVld_flg"
  GeMSM_BMUState_enum/1 -> Bus Creator/11  "GeMSM_BMUState_enum"
  GcHDP_PackCrnt_A/1 -> Bus Creator/12  "GcHDP_PackCrnt_A"
  GeFTC_FltLevel_enum/1 -> Bus Creator/13  "GeFTC_FltLevel_enum"
  Bus Creator/1 -> Bus Selector7/1, Bus Selector1/1, Bus Selector/1
  Bus Selector7/1 -> PeakPwrCacl/1(GcCDP_MaxCellTemp_C)  "<GcCDP_MaxCellTemp_C>"
  Bus Selector7/2 -> PeakPwrCacl/2(GcCDP_MinCellTemp_C)  "<GcCDP_MinCellTemp_C>"
  Bus Selector7/3 -> PeakPwrCacl/3(GcSOC_MaxCellSOC_pct)  "<GcSOC_MaxCellSOC_pct>"
  Bus Selector7/4 -> PeakPwrCacl/4(GcSOC_MinCellSOC_pct)  "<GcSOC_MinCellSOC_pct>"
  Bus Selector7/5 -> PeakPwrCacl/5(GeCTC_CtrCtlConnMode_enum)  "<GeCTC_CtrCtlConnMode_enum>"
  Bus Selector7/6 -> PeakPwrCacl/6(GcCDP_MaxCellVolt_mV)  "<GcCDP_MaxCellVolt_mV>"
  Bus Selector7/7 -> PeakPwrCacl/7(GcCDP_MinCellVolt_mV)  "<GcCDP_MinCellVolt_mV>"
  Bus Selector7/8 -> PeakPwrCacl/8(GcCDP_SumCellVolt_V)  "<GcCDP_SumCellVolt_V>"
  Bus Selector7/9 -> PeakPwrCacl/9(GbCDP_SumCellVoltVld_flg)  "<GbCDP_SumCellVoltVld_flg>"
  Bus Selector7/10 -> PeakPwrCacl/10(GeFTC_FltLevel_enum)  "<GeFTC_FltLevel_enum>"
  Bus Selector5/3 -> PwrAlarm/3(GcSOP_MaxChrgCurr_A)  "<GcSOP_MaxChrgCurr_A>"
  Bus Selector3/1 -> GcSOP_MaxChrgCurr_A/1  "<GcSOP_MaxChrgCurr_A>"
  Bus Selector1/1 -> PwrAlarm/5(GcACC_ACChrgCrntRqst_A)  "<GcACC_ACChrgCrntRqst_A>"
  Bus Selector1/2 -> PwrAlarm/6(GcDCC_DCChrgCrntRqst_A)  "<GcDCC_DCChrgCrntRqst_A>"
  PeakPwrTimeFactor/1(LbSOP_SOPEnbl_flg) -> PwrAlarm/4(LbSOP_SOPEnbl_flg)
  Bus Selector7/11 -> PeakPwrCacl/11(GeMSM_BMUState_enum)  "<GeMSM_BMUState_enum>"
  Bus Selector7/12 -> PeakPwrCacl/12(GbISP_OpenContactor_flg)  "<GbISP_OpenContactor_flg>"
  Bus Selector7/13 -> PeakPwrCacl/13(GbISP_PowerDown_flg)  "<GbISP_PowerDown_flg>"
  Bus Selector7/14 -> PeakPwrCacl/14(GbISP_DCChrgCurrLimitLevel2_flg)  "<GbISP_DCChrgCurrLimitLevel2_flg>"
  GeCTC_CtrCtlState_enum/1 -> Bus Creator/14  "GeCTC_CtrCtlState_enum"
  GcACC_ACChrgCrntRqst_A/1 -> Bus Creator/15  "GcACC_ACChrgCrntRqst_A"
  GcDCC_DCChrgCrntRqst_A/1 -> Bus Creator/16  "GcDCC_DCChrgCrntRqst_A"
  GbISP_OpenContactor_flg/1 -> Bus Creator/17  "GbISP_OpenContactor_flg"
  GbISP_PowerDown_flg/1 -> Bus Creator/18  "GbISP_PowerDown_flg"
  GbISP_DischrgPwrLimitLevel3_flg/1 -> Bus Creator/19  "GbISP_DischrgPwrLimitLevel3_flg"
  GbISP_RegenPwrLimitLevel3_flg/1 -> Bus Creator/20  "GbISP_RegenPwrLimitLevel3_flg"
  GbISP_DischrgPwrLimitLevel2_flg/1 -> Bus Creator/21  "GbISP_DischrgPwrLimitLevel2_flg"
  GbISP_RegenPwrLimitLevel2_flg/1 -> Bus Creator/22  "GbISP_RegenPwrLimitLevel2_flg"
  GbISP_DCChrgCurrLimitLevel2_flg/1 -> Bus Creator/23  "GbISP_DCChrgCurrLimitLevel2_flg"
  GbISP_ACChrgCurrLimitLevel2_flg/1 -> Bus Creator/24  "GbISP_ACChrgCurrLimitLevel2_flg"
  GbISP_DischrgPwrLimitLevel1_flg/1 -> Bus Creator/25  "GbISP_DischrgPwrLimitLevel1_flg"
  GbISP_RegenPwrLimitLevel1_flg/1 -> Bus Creator/26  "GbISP_RegenPwrLimitLevel1_flg"
  Bus Selector/5 -> PeakPwrTimeFactor/9(GbISP_OpenContactor_flg)  "<GbISP_OpenContactor_flg>"
  Bus Selector/6 -> PeakPwrTimeFactor/10(GbISP_PowerDown_flg)  "<GbISP_PowerDown_flg>"
  Bus Selector/7 -> PeakPwrTimeFactor/11(GbISP_DischrgPwrLimitLevel3_flg)  "<GbISP_DischrgPwrLimitLevel3_flg>"
  Bus Selector/8 -> PeakPwrTimeFactor/12(GbISP_RegenPwrLimitLevel3_flg)  "<GbISP_RegenPwrLimitLevel3_flg>"
  Bus Selector/9 -> PeakPwrTimeFactor/13(GbISP_DischrgPwrLimitLevel2_flg)  "<GbISP_DischrgPwrLimitLevel2_flg>"
  Bus Selector/10 -> PeakPwrTimeFactor/14(GbISP_RegenPwrLimitLevel2_flg)  "<GbISP_RegenPwrLimitLevel2_flg>"
  Bus Selector/11 -> PeakPwrTimeFactor/15(GbISP_DischrgPwrLimitLevel1_flg)  "<GbISP_DischrgPwrLimitLevel1_flg>"
  Bus Selector/12 -> PeakPwrTimeFactor/16(GbISP_RegenPwrLimitLevel1_flg)  "<GbISP_RegenPwrLimitLevel1_flg>"
  Bus Selector/13 -> PeakPwrTimeFactor/17(GcCDP_MinCellVolt_mV)  "<GcCDP_MinCellVolt_mV>"
  Bus Selector/14 -> PeakPwrTimeFactor/18(GcCDP_MaxCellVolt_mV)  "<GcCDP_MaxCellVolt_mV>"
  Bus Selector/15 -> PeakPwrTimeFactor/19(GcCDP_MinCellTemp_C)  "<GcCDP_MinCellTemp_C>"
  PwrAlarm/4(GbSOP_DisChrgPwrFltLevel3_flg) -> GbSOP_DisChrgPwrFltLevel3_flg/1
  PwrAlarm/5(GbSOP_DisChrgPwrFltLevel2_flg) -> GbSOP_DisChrgPwrFltLevel2_flg/1
  PwrAlarm/6(GbSOP_DisChrgPwrFltLevel1_flg) -> GbSOP_DisChrgPwrFltLevel1_flg/1
  PwrAlarm/7(GbSOP_FeedbackPwrFltLevel3_flg) -> GbSOP_FeedbackPwrFltLevel3_flg/1
  PwrAlarm/8(GbSOP_FeedbackPwrFltLevel2_flg) -> GbSOP_FeedbackPwrFltLevel2_flg/1
  PwrAlarm/9(GbSOP_FeedbackPwrFltLevel1_flg) -> GbSOP_FeedbackPwrFltLevel1_flg/1
  PwrAlarm/10(GbSOP_ChrgPwrFltLevel3_flg) -> GbSOP_ChrgPwrFltLevel3_flg/1
  PwrAlarm/11(GbSOP_ChrgPwrFltLevel2_flg) -> GbSOP_ChrgPwrFltLevel2_flg/1
  PwrAlarm/12(GbSOP_ChrgPwrFltLevel1_flg) -> GbSOP_ChrgPwrFltLevel1_flg/1
  PeakPwrTimeFactor/8(LbSOP_DisChrgDetLevel1_flg) -> PwrOutput/7(LbSOP_DisChrgDetLevel1_flg)
  PeakPwrTimeFactor/9(LbSOP_DisChrgHealLevel1_flg) -> PwrOutput/8(LbSOP_DisChrgHealLevel1_flg)
  PeakPwrTimeFactor/10(LbSOP_DisChrgFloorFlag_flg) -> PwrOutput/9(LbSOP_DisChrgFloorFlag_flg)
  PeakPwrTimeFactor/11(LbSOP_ChrgFloorFlag_flg) -> PwrOutput/10(LbSOP_ChrgFloorFlag_flg)
  GcSOH_PackSOH_pct/1 -> Bus Creator/27  "GcSOH_PackSOH_pct"
  Bus Selector/16 -> PeakPwrTimeFactor/20(GcSOH_PackSOH_pct)  "<GcSOH_PackSOH_pct>"
  GeUDS_CapSel_enum/1 -> Bus Creator/28  "GeUDS_CapSel_enum"
  GeUDS_AreaSel_enum/1 -> Bus Creator/29  "GeUDS_AreaSel_enum"
  Bus Selector7/15 -> PeakPwrCacl/15(GeUDS_CapSel_enum)  "<GeUDS_CapSel_enum>"
  Bus Selector/17 -> PeakPwrTimeFactor/21(GeUDS_CapSel_enum)  "<GeUDS_CapSel_enum>"
  Bus Selector1/6 -> PwrAlarm/10(GbISP_OpenContactor_flg)  "<GbISP_OpenContactor_flg>"
  GbUDS_TestMode1_flg/1 -> Bus Creator/30  "GbUDS_TestMode1_flg"
  Bus Selector1/7 -> PwrAlarm/11(GbUDS_TestMode1_flg)  "<GbUDS_TestMode1_flg>"

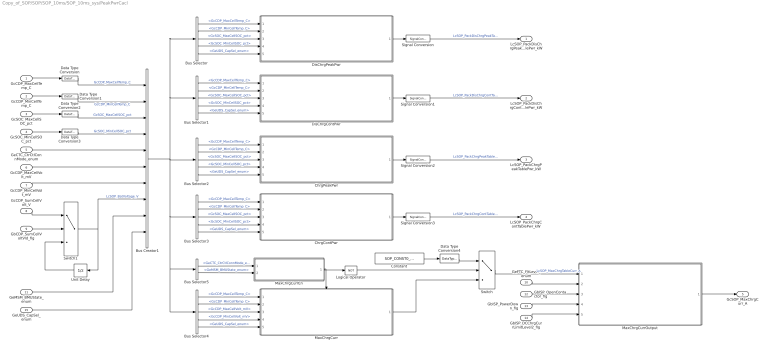
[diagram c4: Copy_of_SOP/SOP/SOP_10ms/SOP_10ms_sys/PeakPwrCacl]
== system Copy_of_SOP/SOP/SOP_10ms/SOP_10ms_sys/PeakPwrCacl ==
  GcCDP_MaxCellTemp_C : Inport
  GcCDP_MinCellTemp_C : Inport  Port=2
  GcSOC_MaxCellSOC_pct : Inport  Port=3
  GcSOC_MinCellSOC_pct : Inport  Port=4
  GeCTC_CtrCtlConnMode_enum : Inport  Port=5
  GcCDP_MaxCellVolt_mV : Inport  Port=6
  GcCDP_MinCellVolt_mV : Inport  Port=7
  GcCDP_SumCellVolt_V : Inport  Port=8
  GbCDP_SumCellVoltVld_flg : Inport  Port=9
  GeFTC_FltLevel_enum : Inport  Port=10
  GeMSM_BMUState_enum : Inport  Port=11
  GbISP_OpenContactor_flg : Inport  Port=12
  GbISP_PowerDown_flg : Inport  Port=13
  GbISP_DCChrgCurrLimitLevel2_flg : Inport  Port=14
  GeUDS_CapSel_enum : Inport  Port=15
  Bus Creator1 : BusCreator  Inputs=10
  Bus Selector{,1..3} (4 alike) : BusSelector  OutputSignals=GcCDP_MaxCellTemp_C,GcCDP_MinCellTemp_C,GcSOC_MaxCellSOC_pct,GcSOC_MinCellSOC_pct,GeUDS_CapSel_enum
  Bus Selector4 : BusSelector  OutputSignals=GcCDP_MaxCellTemp_C,GcCDP_MinCellTemp_C,GcCDP_MaxCellVolt_mV,GcCDP_MinCellVolt_mV,GeUDS_CapSel_enum
  Bus Selector5 : BusSelector  OutputSignals=GeCTC_CtrCtlConnMode_enum,GeMSM_BMUState_enum
  ChrgContPwr : Subsystem
  ChrgPeakPwr : Subsystem
  Constant : Constant  Value=SOP_CONST0_NUMB
  Data Type Conversion : DataTypeConversion  OutDataTypeStr=fixdt(0,8,1,-40)
  Data Type Conversion1 : DataTypeConversion  OutDataTypeStr=fixdt(0,8,1,-40)
  Data Type Conversion2 : DataTypeConversion  OutDataTypeStr=uint8
  Data Type Conversion3 : DataTypeConversion  OutDataTypeStr=uint8
  Data Type Conversion4 : DataTypeConversion
  DisChrgContPwr : Subsystem
  DisChrgPeakPwr : Subsystem
  Logical Operator : Logic  Operator=NOT  AllPortsSameDT=off  OutDataTypeStr=boolean
  MaxChrgCurr : Subsystem
  MaxChrgCurrEn : Subsystem
  MaxChrgCurrOutput : Subsystem
  Signal Conversion{,1..3} (4 alike) : SignalConversion  ConversionOutput=Contiguous copy  OverrideOpt=off
  Switch : Switch  Criteria=u2 ~= 0
  Switch1 : Switch  Criteria=u2 ~= 0
  Unit Delay : UnitDelay  SampleTime=-1  StateName=StateName
  LcSOP_PackDisChrgPeakTablePwr_kW : Outport
  LcSOP_PackDisChrgContTablePwr_kW : Outport  Port=2
  LcSOP_PackChrgPeakTablePwr_kW : Outport  Port=3
  LcSOP_PackChrgContTablePwr_kW : Outport  Port=4
  GcSOP_MaxChrgCurr_A : Outport  Port=5
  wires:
  GcSOC_MinCellSOC_pct/1 -> Data Type Conversion3/1
  GcSOC_MaxCellSOC_pct/1 -> Data Type Conversion2/1
  Data Type Conversion1/1 -> Bus Creator1/2  "GcCDP_MinCellTemp_C"
  Data Type Conversion/1 -> Bus Creator1/1  "GcCDP_MaxCellTemp_C"
  GeCTC_CtrCtlConnMode_enum/1 -> Bus Creator1/5
  Bus Selector4/1 -> MaxChrgCurr/1(GcCDP_MaxCellTemp_C)  "<GcCDP_MaxCellTemp_C>"
  Bus Selector4/2 -> MaxChrgCurr/2(GcCDP_MinCellTemp_C)  "<GcCDP_MinCellTemp_C>"
  Bus Selector/1 -> DisChrgPeakPwr/1(GcCDP_MaxCellTemp_C)  "<GcCDP_MaxCellTemp_C>"
  Bus Selector/3 -> DisChrgPeakPwr/3(GcSOC_MaxCellSOC_pct)  "<GcSOC_MaxCellSOC_pct>"
  Bus Selector/2 -> DisChrgPeakPwr/2(GcCDP_MinCellTemp_C)  "<GcCDP_MinCellTemp_C>"
  Bus Selector/4 -> DisChrgPeakPwr/4(GcSOC_MinCellSOC_pct)  "<GcSOC_MinCellSOC_pct>"
  GcCDP_MaxCellTemp_C/1 -> Data Type Conversion/1
  GcCDP_MinCellTemp_C/1 -> Data Type Conversion1/1
  Bus Selector1/2 -> DisChrgContPwr/2(GcCDP_MinCellTemp_C)  "<GcCDP_MinCellTemp_C>"
  Bus Selector1/3 -> DisChrgContPwr/3(GcSOC_MaxCellSOC_pct)  "<GcSOC_MaxCellSOC_pct>"
  Bus Selector1/1 -> DisChrgContPwr/1(GcCDP_MaxCellTemp_C)  "<GcCDP_MaxCellTemp_C>"
  Bus Selector1/4 -> DisChrgContPwr/4(GcSOC_MinCellSOC_pct)  "<GcSOC_MinCellSOC_pct>"
  Bus Selector2/1 -> ChrgPeakPwr/1(GcCDP_MaxCellTemp_C)  "<GcCDP_MaxCellTemp_C>"
  Bus Selector2/2 -> ChrgPeakPwr/2(GcCDP_MinCellTemp_C)  "<GcCDP_MinCellTemp_C>"
  Bus Selector2/3 -> ChrgPeakPwr/3(GcSOC_MaxCellSOC_pct)  "<GcSOC_MaxCellSOC_pct>"
  Bus Selector2/4 -> ChrgPeakPwr/4(GcSOC_MinCellSOC_pct)  "<GcSOC_MinCellSOC_pct>"
  Bus Selector3/3 -> ChrgContPwr/3(GcSOC_MaxCellSOC_pct)  "<GcSOC_MaxCellSOC_pct>"
  Bus Selector3/4 -> ChrgContPwr/4(GcSOC_MinCellSOC_pct)  "<GcSOC_MinCellSOC_pct>"
  Bus Selector3/2 -> ChrgContPwr/2(GcCDP_MinCellTemp_C)  "<GcCDP_MinCellTemp_C>"
  Bus Selector3/1 -> ChrgContPwr/1(GcCDP_MaxCellTemp_C)  "<GcCDP_MaxCellTemp_C>"
  Bus Selector4/3 -> MaxChrgCurr/3(GcCDP_MaxCellVolt_mV)  "<GcCDP_MaxCellVolt_mV>"
  Bus Selector4/4 -> MaxChrgCurr/4(GcCDP_MinCellVolt_mV)  "<GcCDP_MinCellVolt_mV>"
  MaxChrgCurrEn/1(LbSOP_MaxChrgCurrEn_flg) -> Logical Operator/1, MaxChrgCurr/Enable
  Bus Selector5/1 -> MaxChrgCurrEn/1(GeCTC_CtrCtlConnMode_enum)  "<GeCTC_CtrCtlConnMode_enum>"
  Logical Operator/1 -> Switch/2
  Switch/1 -> MaxChrgCurrOutput/1(LcSOP_MaxChrgTableCurr_A)  "LcSOP_MaxChrgTableCurr_A"
  MaxChrgCurr/1(LcSOP_MaxChrgTableCurr_A) -> Switch/3
  Constant/1 -> Data Type Conversion4/1
  Data Type Conversion2/1 -> Bus Creator1/3  "GcSOC_MaxCellSOC_pct"
  Data Type Conversion3/1 -> Bus Creator1/4  "GcSOC_MinCellSOC_pct"
  GcCDP_MaxCellVolt_mV/1 -> Bus Creator1/6
  GcCDP_MinCellVolt_mV/1 -> Bus Creator1/7
  DisChrgPeakPwr/1(LcSOP_DisChrgPeakTablePwr_kW) -> Signal Conversion/1
  Signal Conversion1/1 -> LcSOP_PackDisChrgContTablePwr_kW/1  "LcSOP_PackDisChrgContTablePwr_kW"
  Signal Conversion2/1 -> LcSOP_PackChrgPeakTablePwr_kW/1  "LcSOP_PackChrgPeakTablePwr_kW"
  Signal Conversion3/1 -> LcSOP_PackChrgContTablePwr_kW/1  "LcSOP_PackChrgContTablePwr_kW"
  Bus Creator1/1 -> Bus Selector/1, Bus Selector1/1, Bus Selector3/1, Bus Selector4/1, Bus Selector5/1, Bus Selector2/1
  Switch1/1 -> Bus Creator1/8, Unit Delay/1  "LcSOP_BatVoltage_V"
  GbCDP_SumCellVoltVld_flg/1 -> Switch1/2
  Unit Delay/1 -> Switch1/3
  GcCDP_SumCellVolt_V/1 -> Switch1/1
  Signal Conversion/1 -> LcSOP_PackDisChrgPeakTablePwr_kW/1  "LcSOP_PackDisChrgPeakTablePwr_kW"
  DisChrgContPwr/1(LcSOP_DisChrgContTablePwr_kW) -> Signal Conversion1/1
  ChrgPeakPwr/1(LcSOP_ChrgPeakTablePwr_kW) -> Signal Conversion2/1
  ChrgContPwr/1(LcSOP_ChrgContTablePwr_kW) -> Signal Conversion3/1
  GeFTC_FltLevel_enum/1 -> MaxChrgCurrOutput/2(GeFTC_FltLevel_enum)
  MaxChrgCurrOutput/1(GcSOP_MaxChrgCurr_A) -> GcSOP_MaxChrgCurr_A/1
  GeMSM_BMUState_enum/1 -> Bus Creator1/9
  Bus Selector5/2 -> MaxChrgCurrEn/2(GeMSM_BMUState_enum)  "<GeMSM_BMUState_enum>"
  GbISP_OpenContactor_flg/1 -> MaxChrgCurrOutput/3(GbISP_OpenContactor_flg)
  GbISP_PowerDown_flg/1 -> MaxChrgCurrOutput/4(GbISP_PowerDown_flg)
  GbISP_DCChrgCurrLimitLevel2_flg/1 -> MaxChrgCurrOutput/5(GbISP_DCChrgCurrLimitLevel2_flg)
  Data Type Conversion4/1 -> Switch/1
  GeUDS_CapSel_enum/1 -> Bus Creator1/10
  Bus Selector/5 -> DisChrgPeakPwr/5(GeUDS_CapSel_enum)  "<GeUDS_CapSel_enum>"
  Bus Selector1/5 -> DisChrgContPwr/5(GeUDS_CapSel_enum)  "<GeUDS_CapSel_enum>"
  Bus Selector4/5 -> MaxChrgCurr/5(GeUDS_CapSel_enum)  "<GeUDS_CapSel_enum>"
  Bus Selector3/5 -> ChrgContPwr/5(GeUDS_CapSel_enum)  "<GeUDS_CapSel_enum>"
  Bus Selector2/5 -> ChrgPeakPwr/5(GeUDS_CapSel_enum)  "<GeUDS_CapSel_enum>"

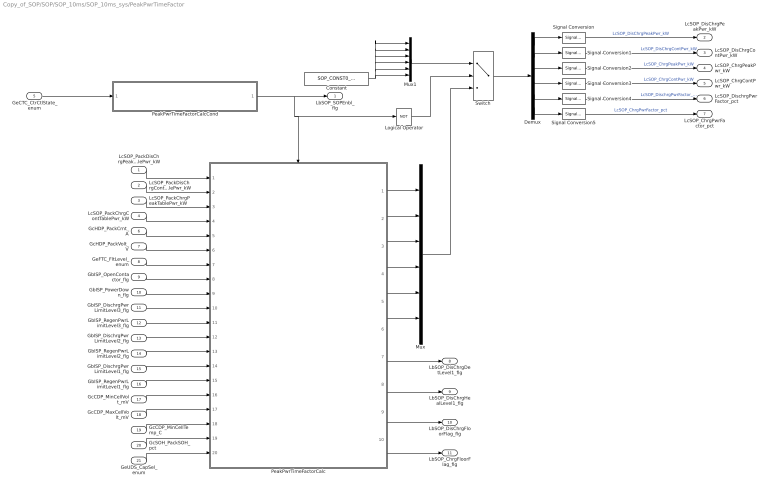
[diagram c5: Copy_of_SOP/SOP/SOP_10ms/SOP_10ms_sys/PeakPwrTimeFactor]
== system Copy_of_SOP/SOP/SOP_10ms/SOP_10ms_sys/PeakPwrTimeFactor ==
  LcSOP_PackDisChrgPeakTablePwr_kW : Inport
  LcSOP_PackDisChrgContTablePwr_kW : Inport  Port=2
  LcSOP_PackChrgPeakTablePwr_kW : Inport  Port=3
  LcSOP_PackChrgContTablePwr_kW : Inport  Port=4
  GeCTC_CtrCtlState_enum : Inport  Port=5
  GcHDP_PackCrnt_A : Inport  Port=6
  GcHDP_PackVolt_V : Inport  Port=7
  GeFTC_FltLevel_enum : Inport  Port=8
  GbISP_OpenContactor_flg : Inport  Port=9
  GbISP_PowerDown_flg : Inport  Port=10
  GbISP_DischrgPwrLimitLevel3_flg : Inport  Port=11
  GbISP_RegenPwrLimitLevel3_flg : Inport  Port=12
  GbISP_DischrgPwrLimitLevel2_flg : Inport  Port=13
  GbISP_RegenPwrLimitLevel2_flg : Inport  Port=14
  GbISP_DischrgPwrLimitLevel1_flg : Inport  Port=15
  GbISP_RegenPwrLimitLevel1_flg : Inport  Port=16
  GcCDP_MinCellVolt_mV : Inport  Port=17
  GcCDP_MaxCellVolt_mV : Inport  Port=18
  GcCDP_MinCellTemp_C : Inport  Port=19
  GcSOH_PackSOH_pct : Inport  Port=20
  GeUDS_CapSel_enum : Inport  Port=21
  Constant : Constant  Value=SOP_CONST0_NUMB
  Demux : Demux  Outputs=6
  Logical Operator : Logic  Operator=NOT  AllPortsSameDT=off  OutDataTypeStr=boolean
  Mux : Mux  Inputs=6
  Mux1 : Mux  Inputs=6
  PeakPwrTimeFactorCalc : Subsystem
  PeakPwrTimeFactorCalcCond : Subsystem
  Signal Conversion{,1..5} (6 alike) : SignalConversion  OverrideOpt=off
  Switch : Switch  Criteria=u2 ~= 0
  LbSOP_SOPEnbl_flg : Outport
  LcSOP_DisChrgPeakPwr_kW : Outport  Port=2
  LcSOP_DisChrgContPwr_kW : Outport  Port=3
  LcSOP_ChrgPeakPwr_kW : Outport  Port=4
  LcSOP_ChrgContPwr_kW : Outport  Port=5
  LcSOP_DischrgPwrFactor_pct : Outport  Port=6
  LcSOP_ChrgPwrFactor_pct : Outport  Port=7
  LbSOP_DisChrgDetLevel1_flg : Outport  Port=8
  LbSOP_DisChrgHealLevel1_flg : Outport  Port=9
  LbSOP_DisChrgFloorFlag_flg : Outport  Port=10
  LbSOP_ChrgFloorFlag_flg : Outport  Port=11
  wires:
  Signal Conversion5/1 -> LcSOP_ChrgPwrFactor_pct/1  "LcSOP_ChrgPwrFactor_pct"
  Signal Conversion4/1 -> LcSOP_DischrgPwrFactor_pct/1  "LcSOP_DischrgPwrFactor_pct"
  Signal Conversion3/1 -> LcSOP_ChrgContPwr_kW/1  "LcSOP_ChrgContPwr_kW"
  Signal Conversion2/1 -> LcSOP_ChrgPeakPwr_kW/1  "LcSOP_ChrgPeakPwr_kW"
  Signal Conversion1/1 -> LcSOP_DisChrgContPwr_kW/1  "LcSOP_DisChrgContPwr_kW"
  Signal Conversion/1 -> LcSOP_DisChrgPeakPwr_kW/1  "LcSOP_DisChrgPeakPwr_kW"
  Demux/6 -> Signal Conversion5/1
  Demux/5 -> Signal Conversion4/1
  Demux/4 -> Signal Conversion3/1
  Demux/3 -> Signal Conversion2/1
  Demux/2 -> Signal Conversion1/1
  Demux/1 -> Signal Conversion/1
  PeakPwrTimeFactorCalc/4(LcSOP_ChrgContPwr_kW) -> Mux/4
  PeakPwrTimeFactorCalc/3(LcSOP_ChrgPeakPwr_kW) -> Mux/3
  PeakPwrTimeFactorCalc/2(LcSOP_DisChrgContPwr_kW) -> Mux/2
  PeakPwrTimeFactorCalc/1(LcSOP_DisChrgPeakPwr_kW) -> Mux/1
  PeakPwrTimeFactorCalc/6(LcSOP_ChrgPwrFactor_pct) -> Mux/6
  PeakPwrTimeFactorCalc/5(LcSOP_DischrgPwrFactor_pct) -> Mux/5
  LcSOP_PackDisChrgPeakTablePwr_kW/1 -> PeakPwrTimeFactorCalc/1(LcSOP_PackDisChrgPeakTablePwr_kW)
  LcSOP_PackChrgContTablePwr_kW/1 -> PeakPwrTimeFactorCalc/4(LcSOP_PackChrgContTablePwr_kW)
  LcSOP_PackDisChrgContTablePwr_kW/1 -> PeakPwrTimeFactorCalc/2(LcSOP_PackDisChrgContTablePwr_kW)
  LcSOP_PackChrgPeakTablePwr_kW/1 -> PeakPwrTimeFactorCalc/3(LcSOP_PackChrgPeakTablePwr_kW)
  GeFTC_FltLevel_enum/1 -> PeakPwrTimeFactorCalc/7(GeFTC_FltLevel_enum)
  GeCTC_CtrCtlState_enum/1 -> PeakPwrTimeFactorCalcCond/1(GeCTC_CtrCtlState_enum)
  GcHDP_PackVolt_V/1 -> PeakPwrTimeFactorCalc/6(GcHDP_PackVolt_V)
  GcHDP_PackCrnt_A/1 -> PeakPwrTimeFactorCalc/5(GcHDP_PackCrnt_A)
  PeakPwrTimeFactorCalcCond/1(LbSOP_SOPEnbl_flg) -> PeakPwrTimeFactorCalc/Enable, Logical Operator/1, LbSOP_SOPEnbl_flg/1
  Mux/1 -> Switch/3
  Logical Operator/1 -> Switch/2
  Mux1/1 -> Switch/1
  Switch/1 -> Demux/1
  GbISP_OpenContactor_flg/1 -> PeakPwrTimeFactorCalc/8(GbISP_OpenContactor_flg)
  GbISP_PowerDown_flg/1 -> PeakPwrTimeFactorCalc/9(GbISP_PowerDown_flg)
  GbISP_DischrgPwrLimitLevel3_flg/1 -> PeakPwrTimeFactorCalc/10(GbISP_DischrgPwrLimitLevel3_flg)
  GbISP_RegenPwrLimitLevel3_flg/1 -> PeakPwrTimeFactorCalc/11(GbISP_RegenPwrLimitLevel3_flg)
  GbISP_DischrgPwrLimitLevel2_flg/1 -> PeakPwrTimeFactorCalc/12(GbISP_DischrgPwrLimitLevel2_flg)
  GbISP_RegenPwrLimitLevel2_flg/1 -> PeakPwrTimeFactorCalc/13(GbISP_RegenPwrLimitLevel2_flg)
  GbISP_DischrgPwrLimitLevel1_flg/1 -> PeakPwrTimeFactorCalc/14(GbISP_DischrgPwrLimitLevel1_flg)
  GbISP_RegenPwrLimitLevel1_flg/1 -> PeakPwrTimeFactorCalc/15(GbISP_RegenPwrLimitLevel1_flg)
  GcCDP_MinCellVolt_mV/1 -> PeakPwrTimeFactorCalc/16(GcCDP_MinCellVolt_mV)
  GcCDP_MinCellTemp_C/1 -> PeakPwrTimeFactorCalc/18(GcCDP_MinCellTemp_C)
  GcCDP_MaxCellVolt_mV/1 -> PeakPwrTimeFactorCalc/17(GcCDP_MaxCellVolt_mV)
  PeakPwrTimeFactorCalc/7(LbSOP_DisChrgDetLevel1_flg) -> LbSOP_DisChrgDetLevel1_flg/1
  PeakPwrTimeFactorCalc/8(LbSOP_DisChrgHealLevel1_flg) -> LbSOP_DisChrgHealLevel1_flg/1
  PeakPwrTimeFactorCalc/9(LbSOP_DisChrgFloorFlag_flg) -> LbSOP_DisChrgFloorFlag_flg/1
  PeakPwrTimeFactorCalc/10(LbSOP_ChrgFloorFlag_flg) -> LbSOP_ChrgFloorFlag_flg/1
  Constant/1 -> Mux1/1, Mux1/2, Mux1/3, Mux1/4, Mux1/5, Mux1/6
  GcSOH_PackSOH_pct/1 -> PeakPwrTimeFactorCalc/19(GcSOH_PackSOH_pct)
  GeUDS_CapSel_enum/1 -> PeakPwrTimeFactorCalc/20(GeUDS_CapSel_enum)
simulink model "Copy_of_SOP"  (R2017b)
settings: Solver=FixedStepDiscrete  StartTime=0.0  StopTime=10.0  FixedStep=0.01  RelTol=1e-3  EnableMultiTasking=on
undefined symbols (not defined in the file): ASWTYPE_FALSE, ASWTYPE_TRUE, CcSOP_CellVoltLowLevel1Time_MS, CcSOP_CellVoltRngDiff_V, CcSOP_CellVoltRngDiffHeal_V, CcSOP_CellVoltRngHighTime_MS, CcSOP_CellVoltRngLowTime_MS, CcSOP_CellVoltRngUpLimit_V, CcSOP_ChrgCurrFltChrgCurrThrld_A, CcSOP_ChrgCurrFltLevel1Factor_numb, CcSOP_ChrgCurrFltLevel1Time_ms, CcSOP_ChrgCurrFltLevel2Factor_numb, CcSOP_ChrgCurrFltLevel2Time_ms, CcSOP_ChrgCurrFltLevel3Factor_numb, CcSOP_ChrgCurrFltLevel3Time_ms, CcSOP_ChrgFloorPwrLimit_kW, CcSOP_ChrgFltHysCurr_A, CcSOP_ChrgHighFactor_numb, CcSOP_ChrgLowFactor_numb, CcSOP_ChrgPwrFltPeakPwrThrld_kW, CcSOP_DisChrgEmerPwrLimit_kW, CcSOP_DisChrgFloorPwrLimit_kW, CcSOP_DisChrgHighFactor_numb, CcSOP_DisChrgLowFactor_numb, CcSOP_DischrgPwrFltLevel1Factor_numb, CcSOP_DischrgPwrFltLevel1Time_ms, CcSOP_DischrgPwrFltLevel2Factor_numb, CcSOP_DischrgPwrFltLevel2Time_ms, CcSOP_DischrgPwrFltLevel3Factor_numb, CcSOP_DischrgPwrFltLevel3Time_ms, CcSOP_DischrgPwrFltPeakPwrThrld_kW, CcSOP_DischrgPwrFltThrld_kW, CcSOP_DisChrgPwrLimit_kW, CcSOP_FeedbackPwrFltLevel1Factor_numb, CcSOP_FeedbackPwrFltLevel1Time_ms, CcSOP_FeedbackPwrFltLevel2Factor_numb, CcSOP_FeedbackPwrFltLevel2Time_ms, CcSOP_FeedbackPwrFltLevel3Factor_numb, CcSOP_FeedbackPwrFltLevel3Time_ms, CcSOP_FeedbackPwrFltThrld_kW, CcSOP_FltLimitPwrFactorLevel1_numb, CcSOP_FltLimitPwrFactorLevel2_numb, CcSOP_LookupTablePwrFactor_pct, CcSOP_MaxChrgCurrLimitFactorLevel2_numb, CcSOP_MaxCurrTableLarger_ms, CcSOP_MaxCurrTableSmaller_ms, CcSOP_PeakPowerRunTime_ms, CcSOP_PwrDownDisDetLevel1Speed_kW, CcSOP_PwrDownDisFloorFactor_numb, CcSOP_PwrDownDisFloorSpeed_kW, CcSOP_PwrDownSpeed_kW, CcSOP_PwrFltHysFactor_numb, CcSOP_PwrFltThrldTestMode_kW, CcSOP_PwrUpSpeed_kW, Enum_CTCCtrCtlConnMode, Enum_CTCCtrCtlState, Enum_MSMBMUState, Enum_SOPChrgPwrState, Enum_SOPDisChrgPwrState, Enum_SOPFeedbackPwrState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
libraries: AIWAYS_Powertrain_BMS_lib x77
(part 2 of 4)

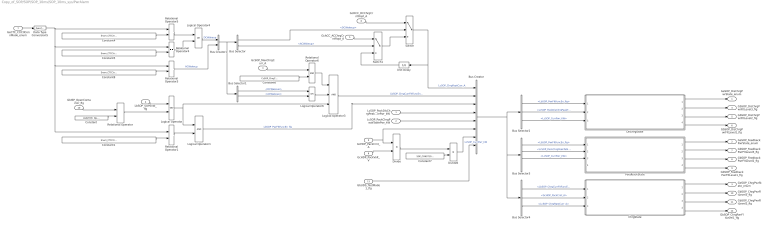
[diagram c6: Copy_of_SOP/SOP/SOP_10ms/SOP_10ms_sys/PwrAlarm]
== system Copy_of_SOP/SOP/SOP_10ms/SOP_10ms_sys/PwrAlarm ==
  LcSOP_PackDisChrgPeakTablePwr_kW : Inport
  LcSOP_PackChrgPeakTablePwr_kW : Inport  Port=2
  GcSOP_MaxChrgCurr_A : Inport  Port=3
  LbSOP_SOPEnbl_flg : Inport  Port=4
  GcACC_ACChrgCrntRqst_A : Inport  Port=5
  GcDCC_DCChrgCrntRqst_A : Inport  Port=6
  GeCTC_CtrCtlConnMode_enum : Inport  Port=7
  GcHDP_PackVolt_V : Inport  Port=8
  GcHDP_PackCrnt_A : Inport  Port=9
  GbISP_OpenContactor_flg : Inport  Port=10
  GbUDS_TestMode1_flg : Inport  Port=11
  Bus Creator : BusCreator  Inputs=8
  Bus Creator1 : BusCreator  Inputs=2
  Bus Selector : BusSelector  OutputSignals=DCWakeup,ACWakeup
  Bus Selector1 : BusSelector  OutputSignals=DCWakeup,ACWakeup
  Bus Selector2 : BusSelector  OutputSignals=LbSOP_PwrFltFuncEn_flg,LcSOP_PackDisChrgPeakTablePwr_kW,LcSOP_CurrPwr_kW
  Bus Selector3 : BusSelector  OutputSignals=LbSOP_PwrFltFuncEn_flg,LcSOP_PackChrgPeakTablePwr_kW,LcSOP_CurrPwr_kW,GbUDS_TestMode1_flg
  Bus Selector4 : BusSelector  OutputSignals=LbSOP_ChrgCurrFltFuncEn_flg,GcHDP_PackCrnt_A,LcSOP_ChrgRqstCurr_A
  ChrgState : Subsystem
  Constant : Constant  Value=ASWTYPE_FALSE
  Constant1 : Constant  Value=Enum_CTCCtrCtlConnMode.Enum_CTCCtrCtlConnMode_Drive
  Constant4 : Constant  Value=Enum_CTCCtrCtlConnMode.Enum_CTCCtrCtlConnMode_DCChrg
  Constant5 : Constant  Value=Enum_CTCCtrCtlConnMode.Enum_CTCCtrCtlConnMode_EDCChrg
  Constant6 : Constant  Value=CcSOP_ChrgCurrFltChrgCurrThrld_A
  Constant7 : Constant  Value=SOP_CONST1000_NUMB
  Constant8 : Constant  Value=Enum_CTCCtrCtlConnMode.Enum_CTCCtrCtlConnMode_ACChrg
  Data Type Conversion5 : DataTypeConversion
  DischrgState : Subsystem
  Divide : Product  Inputs=**  OutDataTypeStr=single
  Divide6 : Product  Inputs=*/  OutDataTypeStr=single
  FeedbackState : Subsystem
  Logical Operator : Logic  AllPortsSameDT=off  OutDataTypeStr=boolean
  Logical Operator1 : Logic  AllPortsSameDT=off  OutDataTypeStr=boolean
  Logical Operator3 : Logic  Inputs=3  AllPortsSameDT=off  OutDataTypeStr=boolean
  Logical Operator4 : Logic  Operator=OR  AllPortsSameDT=off  OutDataTypeStr=boolean
  Logical Operator6 : Logic  Operator=OR  AllPortsSameDT=off  OutDataTypeStr=boolean
  Relational Operator{,1,3..5} (5 alike) : RelationalOperator  Operator===  OutDataTypeStr=boolean
  Relational Operator6 : RelationalOperator  OutDataTypeStr=boolean
  Switch : Switch  Criteria=u2 ~= 0  OutDataTypeStr=Inherit: Inherit via back propagation
  Switch1 : Switch  Criteria=u2 ~= 0  OutDataTypeStr=Inherit: Inherit via back propagation
  Unit Delay : UnitDelay  SampleTime=-1  StateName=StateName
  GeSOP_DisChrgPwrState_enum : Outport
  GeSOP_FeedbackPwrState_enum : Outport  Port=2
  GeSOP_ChrgPwrState_enum : Outport  Port=3
  GbSOP_DisChrgPwrFltLevel3_flg : Outport  Port=4
  GbSOP_DisChrgPwrFltLevel2_flg : Outport  Port=5
  GbSOP_DisChrgPwrFltLevel1_flg : Outport  Port=6
  GbSOP_FeedbackPwrFltLevel3_flg : Outport  Port=7
  GbSOP_FeedbackPwrFltLevel2_flg : Outport  Port=8
  GbSOP_FeedbackPwrFltLevel1_flg : Outport  Port=9
  GbSOP_ChrgPwrFltLevel3_flg : Outport  Port=10
  GbSOP_ChrgPwrFltLevel2_flg : Outport  Port=11
  GbSOP_ChrgPwrFltLevel1_flg : Outport  Port=12
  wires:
  ChrgState/1(GeSOP_ChrgPwrState_enum) -> GeSOP_ChrgPwrState_enum/1
  FeedbackState/1(GeSOP_FeedbackPwrState_enum) -> GeSOP_FeedbackPwrState_enum/1
  DischrgState/1(GeSOP_DisChrgPwrState_enum) -> GeSOP_DisChrgPwrState_enum/1
  Bus Selector4/3 -> ChrgState/3(LcSOP_ChrgRqstCurr_A)  "<LcSOP_ChrgRqstCurr_A>"
  Bus Selector4/2 -> ChrgState/2(GcHDP_PackCrnt_A)  "<GcHDP_PackCrnt_A>"
  Bus Selector4/1 -> ChrgState/1(LbSOP_ChrgCurrFltFuncEn_flg)  "<LbSOP_ChrgCurrFltFuncEn_flg>"
  GcHDP_PackVolt_V/1 -> Divide/2
  GcHDP_PackCrnt_A/1 -> Divide/1, Bus Creator/6
  Bus Selector3/3 -> FeedbackState/3(LcSOP_CurrPwr_kW)  "<LcSOP_CurrPwr_kW>"
  Bus Selector3/1 -> FeedbackState/1(LbSOP_PwrFltFuncEn_flg)  "<LbSOP_PwrFltFuncEn_flg>"
  Bus Selector3/2 -> FeedbackState/2(LcSOP_PackChrgPeakTablePwr_kW)  "<LcSOP_PackChrgPeakTablePwr_kW>"
  Bus Selector2/3 -> DischrgState/3(LcSOP_CurrPwr_kW)  "<LcSOP_CurrPwr_kW>"
  Bus Selector2/2 -> DischrgState/2(LcSOP_PackDisChrgPeakTablePwr_kW)  "<LcSOP_PackDisChrgPeakTablePwr_kW>"
  Bus Selector2/1 -> DischrgState/1(LbSOP_PwrFltFuncEn_flg)  "<LbSOP_PwrFltFuncEn_flg>"
  Bus Creator/1 -> Bus Selector2/1, Bus Selector4/1, Bus Selector3/1
  Divide6/1 -> Bus Creator/7  "LcSOP_CurrPwr_kW"
  LcSOP_PackChrgPeakTablePwr_kW/1 -> Bus Creator/5
  LcSOP_PackDisChrgPeakTablePwr_kW/1 -> Bus Creator/4
  Logical Operator3/1 -> Bus Creator/2  "LbSOP_ChrgCurrFltFuncEn_flg"
  Bus Selector1/2 -> Logical Operator6/2  "<ACWakeup>"
  Bus Selector1/1 -> Logical Operator6/1  "<DCWakeup>"
  Switch/1 -> Bus Creator/1, Unit Delay/1  "LcSOP_ChrgRqstCurr_A"
  Unit Delay/1 -> Switch1/3
  Bus Creator1/1 -> Bus Selector1/1, Bus Selector/1
  Bus Selector/2 -> Switch1/2  "<ACWakeup>"
  Bus Selector/1 -> Switch/2  "<DCWakeup>"
  GcACC_ACChrgCrntRqst_A/1 -> Switch1/1
  Switch1/1 -> Switch/3
  GcDCC_DCChrgCrntRqst_A/1 -> Switch/1
  Relational Operator3/1 -> Bus Creator1/2  "ACWakeup"
  Logical Operator4/1 -> Bus Creator1/1  "DCWakeup"
  Relational Operator4/1 -> Logical Operator4/2
  Relational Operator5/1 -> Logical Operator4/1
  Relational Operator1/1 -> Logical Operator1/2
  Constant4/1 -> Relational Operator5/2
  Constant5/1 -> Relational Operator4/2
  Constant8/1 -> Relational Operator3/2
  Logical Operator1/1 -> Bus Creator/3  "LbSOP_PwrFltFuncEn_flg"
  Logical Operator/1 -> Logical Operator3/3, Logical Operator1/1
  GeCTC_CtrCtlConnMode_enum/1 -> Data Type Conversion5/1
  Constant1/1 -> Relational Operator1/2
  Divide/1 -> Divide6/1
  Constant7/1 -> Divide6/2
  Relational Operator/1 -> Logical Operator/2
  Constant/1 -> Relational Operator/2
  Constant6/1 -> Relational Operator6/2
  Relational Operator6/1 -> Logical Operator3/1
  GcSOP_MaxChrgCurr_A/1 -> Relational Operator6/1
  Logical Operator6/1 -> Logical Operator3/2
  Data Type Conversion5/1 -> Relational Operator3/1, Relational Operator1/1, Relational Operator4/1, Relational Operator5/1
  LbSOP_SOPEnbl_flg/1 -> Logical Operator/1
  DischrgState/2(GbSOP_DisChrgPwrFltLevel3_flg) -> GbSOP_DisChrgPwrFltLevel3_flg/1
  DischrgState/3(GbSOP_DisChrgPwrFltLevel2_flg) -> GbSOP_DisChrgPwrFltLevel2_flg/1
  DischrgState/4(GbSOP_DisChrgPwrFltLevel1_flg) -> GbSOP_DisChrgPwrFltLevel1_flg/1
  ChrgState/2(GbSOP_ChrgPwrFltLevel3_flg) -> GbSOP_ChrgPwrFltLevel3_flg/1
  ChrgState/3(GbSOP_ChrgPwrFltLevel2_flg) -> GbSOP_ChrgPwrFltLevel2_flg/1
  ChrgState/4(GbSOP_ChrgPwrFltLevel1_flg) -> GbSOP_ChrgPwrFltLevel1_flg/1
  FeedbackState/2(GbSOP_FeedbackPwrFltLevel3_flg) -> GbSOP_FeedbackPwrFltLevel3_flg/1
  FeedbackState/3(GbSOP_FeedbackPwrFltLevel2_flg) -> GbSOP_FeedbackPwrFltLevel2_flg/1
  FeedbackState/4(GbSOP_FeedbackPwrFltLevel1_flg) -> GbSOP_FeedbackPwrFltLevel1_flg/1
  GbISP_OpenContactor_flg/1 -> Relational Operator/1
  GbUDS_TestMode1_flg/1 -> Bus Creator/8

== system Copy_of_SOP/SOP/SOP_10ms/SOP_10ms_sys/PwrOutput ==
  LcSOP_DisChrgPeakPwr_kW : Inport
  LcSOP_DisChrgContPwr_kW : Inport  Port=2
  LcSOP_ChrgPeakPwr_kW : Inport  Port=3
  LcSOP_ChrgContPwr_kW : Inport  Port=4
  LcSOP_DischrgPwrFactor_pct : Inport  Port=5
  LcSOP_ChrgPwrFactor_pct : Inport  Port=6
  LbSOP_DisChrgDetLevel1_flg : Inport  Port=7
  LbSOP_DisChrgHealLevel1_flg : Inport  Port=8
  LbSOP_DisChrgFloorFlag_flg : Inport  Port=9
  LbSOP_ChrgFloorFlag_flg : Inport  Port=10
  Bus Creator6 : BusCreator  Inputs=10
  Bus Creator7 : BusCreator  Inputs=8
  Bus Selector11 : BusSelector  OutputSignals=LcSOP_DisChrgPeakPwr_kW,LcSOP_DisChrgContPwr_kW,LcSOP_ChrgPeakPwr_kW,LcSOP_ChrgContPwr_kW,LcSOP_DischrgPwrFactor_pct,LcSOP_ChrgPwrFactor_pct,LbSOP_DisChrgDetLevel1_flg,LbSOP_DisChrgHealLevel1_flg,LbSOP_DisChrgFloorFlag_flg,LbSOP_ChrgFloorFlag_flg
  Bus Selector12 : BusSelector  OutputSignals=LcSOP_DisChrgPeakPwr_kW,LcSOP_DisChrgContPwr_kW,LcSOP_DischrgPwrFactor_pct,GcSOP_DischrgPwr_kW,LcSOP_ChrgPeakPwr_kW,LcSOP_ChrgContPwr_kW,LcSOP_ChrgPwrFactor_pct,GcSOP_ChrgPwr_kW
  DefaultMode : Subsystem  TreatAsAtomicUnit=on
  OverWrite : AIWAYS_Powertrain_BMS_lib/Signals/OverWrite  OverWrite_Value=CcSOP_DischrgPeakPwrOvr_kW  OverWrite_flag=CbSOP_DischrgPeakPwrOvrSwt_flg
  OverWrite1 : AIWAYS_Powertrain_BMS_lib/Signals/OverWrite  OverWrite_Value=CcSOP_DischrgConstPwrOvr_kW  OverWrite_flag=CbSOP_DischrgConstPwrOvrSwt_flg
  OverWrite2 : AIWAYS_Powertrain_BMS_lib/Signals/OverWrite  OverWrite_Value=CcSOP_DischrgPwrFactorOvr_pct  OverWrite_flag=CbSOP_DischrgPwrFactorOvrSwt_flg
  OverWrite3 : AIWAYS_Powertrain_BMS_lib/Signals/OverWrite  OverWrite_Value=CcSOP_DischrgPwrOvr_kW  OverWrite_flag=CbSOP_DischrgPwrOvrSwt_flg
  OverWrite4 : AIWAYS_Powertrain_BMS_lib/Signals/OverWrite  OverWrite_Value=CcSOP_ChrgPeakPwrOvr_kW  OverWrite_flag=CbSOP_ChrgPeakPwrOvrSwt_flg
  OverWrite5 : AIWAYS_Powertrain_BMS_lib/Signals/OverWrite  OverWrite_Value=CcSOP_ChrgConstPwrOvr_kW  OverWrite_flag=CbSOP_ChrgConstPwrOvrSwt_flg
  OverWrite6 : AIWAYS_Powertrain_BMS_lib/Signals/OverWrite  OverWrite_Value=CcSOP_ChrgPwrFactorOvr_pct  OverWrite_flag=CbSOP_ChrgPwrFactorOvrSwt_flg
  OverWrite7 : AIWAYS_Powertrain_BMS_lib/Signals/OverWrite  OverWrite_Value=CcSOP_ChrgPwrOvr_kW  OverWrite_flag=CbSOP_ChrgPwrOvrSwt_flg
  GcSOP_DischrgPeakPwr_kW : Outport
  GcSOP_DischrgConstPwr_kW : Outport  Port=2
  GcSOP_DischrgPwrFactor_pct : Outport  Port=3
  GcSOP_DischrgPwr_kW : Outport  Port=4
  GcSOP_ChrgPeakPwr_kW : Outport  Port=5
  GcSOP_ChrgConstPwr_kW : Outport  Port=6
  GcSOP_ChrgPwrFactor_pct : Outport  Port=7
  GcSOP_ChrgPwr_kW : Outport  Port=8
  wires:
  OverWrite7/1 -> GcSOP_ChrgPwr_kW/1  "GcSOP_ChrgPwr_kW"
  OverWrite6/1 -> GcSOP_ChrgPwrFactor_pct/1  "GcSOP_ChrgPwrFactor_pct"
  OverWrite5/1 -> GcSOP_ChrgConstPwr_kW/1  "GcSOP_ChrgConstPwr_kW"
  OverWrite4/1 -> GcSOP_ChrgPeakPwr_kW/1  "GcSOP_ChrgPeakPwr_kW"
  OverWrite3/1 -> GcSOP_DischrgPwr_kW/1  "GcSOP_DischrgPwr_kW"
  OverWrite2/1 -> GcSOP_DischrgPwrFactor_pct/1  "GcSOP_DischrgPwrFactor_pct"
  OverWrite1/1 -> GcSOP_DischrgConstPwr_kW/1  "GcSOP_DischrgConstPwr_kW"
  OverWrite/1 -> GcSOP_DischrgPeakPwr_kW/1  "GcSOP_DischrgPeakPwr_kW"
  Bus Creator6/1 -> Bus Selector11/1
  LcSOP_DisChrgPeakPwr_kW/1 -> Bus Creator6/1  "LcSOP_DisChrgPeakPwr_kW"
  LcSOP_DisChrgContPwr_kW/1 -> Bus Creator6/2  "LcSOP_DisChrgContPwr_kW"
  LcSOP_DischrgPwrFactor_pct/1 -> Bus Creator6/3  "LcSOP_DischrgPwrFactor_pct"
  LcSOP_ChrgPwrFactor_pct/1 -> Bus Creator6/6  "LcSOP_ChrgPwrFactor_pct"
  LcSOP_ChrgContPwr_kW/1 -> Bus Creator6/5  "LcSOP_ChrgContPwr_kW"
  LcSOP_ChrgPeakPwr_kW/1 -> Bus Creator6/4  "LcSOP_ChrgPeakPwr_kW"
  Bus Selector11/1 -> DefaultMode/1(LcSOP_DisChrgPeakPwr_kW)  "<LcSOP_DisChrgPeakPwr_kW>"
  Bus Selector11/2 -> DefaultMode/2(LcSOP_DisChrgContPwr_kW)  "<LcSOP_DisChrgContPwr_kW>"
  Bus Selector11/3 -> DefaultMode/3(LcSOP_ChrgPeakPwr_kW)  "<LcSOP_ChrgPeakPwr_kW>"
  Bus Selector11/4 -> DefaultMode/4(LcSOP_ChrgContPwr_kW)  "<LcSOP_ChrgContPwr_kW>"
  Bus Selector11/5 -> DefaultMode/5(LcSOP_DischrgPwrFactor_pct)  "<LcSOP_DischrgPwrFactor_pct>"
  Bus Selector11/6 -> DefaultMode/6(LcSOP_ChrgPwrFactor_pct)  "<LcSOP_ChrgPwrFactor_pct>"
  DefaultMode/1(LcSOP_DischrgPeakPwr_kW) -> Bus Creator7/1
  DefaultMode/2(LcSOP_DischrgConstPwr_kW) -> Bus Creator7/2
  DefaultMode/3(GcSOP_DischrgPwrFactor_pct) -> Bus Creator7/3
  DefaultMode/4(GcSOP_DischrgPwr_kW) -> Bus Creator7/4
  DefaultMode/5(GcSOP_ChrgPeakPwr_kW) -> Bus Creator7/5
  DefaultMode/6(LcSOP_ChrgConstPwr_kW) -> Bus Creator7/6
  DefaultMode/7(GcSOP_ChrgPwrFactor_pct) -> Bus Creator7/7
  DefaultMode/8(GcSOP_ChrgPwr_kW) -> Bus Creator7/8
  Bus Creator7/1 -> Bus Selector12/1
  Bus Selector12/1 -> OverWrite/1  "<LcSOP_DisChrgPeakPwr_kW>"
  Bus Selector12/2 -> OverWrite1/1  "<LcSOP_DisChrgContPwr_kW>"
  Bus Selector12/3 -> OverWrite2/1  "<LcSOP_DischrgPwrFactor_pct>"
  Bus Selector12/4 -> OverWrite3/1  "<GcSOP_DischrgPwr_kW>"
  Bus Selector12/5 -> OverWrite4/1  "<LcSOP_ChrgPeakPwr_kW>"
  Bus Selector12/6 -> OverWrite5/1  "<LcSOP_ChrgContPwr_kW>"
  Bus Selector12/7 -> OverWrite6/1  "<LcSOP_ChrgPwrFactor_pct>"
  Bus Selector12/8 -> OverWrite7/1  "<GcSOP_ChrgPwr_kW>"
  LbSOP_DisChrgDetLevel1_flg/1 -> Bus Creator6/7
  LbSOP_DisChrgHealLevel1_flg/1 -> Bus Creator6/8
  LbSOP_DisChrgFloorFlag_flg/1 -> Bus Creator6/9
  LbSOP_ChrgFloorFlag_flg/1 -> Bus Creator6/10
  Bus Selector11/7 -> DefaultMode/7(LbSOP_DisChrgDetLevel1_flg)  "<LbSOP_DisChrgDetLevel1_flg>"
  Bus Selector11/8 -> DefaultMode/8(LbSOP_DisChrgHealLevel1_flg)  "<LbSOP_DisChrgHealLevel1_flg>"
  Bus Selector11/9 -> DefaultMode/9(LbSOP_DisChrgFloorFlag_flg)  "<LbSOP_DisChrgFloorFlag_flg>"
  Bus Selector11/10 -> DefaultMode/10(LbSOP_ChrgFloorFlag_flg)  "<LbSOP_ChrgFloorFlag_flg>"

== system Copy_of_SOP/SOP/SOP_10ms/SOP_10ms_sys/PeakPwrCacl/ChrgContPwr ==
  GcCDP_MaxCellTemp_C : Inport
  GcCDP_MinCellTemp_C : Inport  Port=2
  GcSOC_MaxCellSOC_pct : Inport  Port=3
  GcSOC_MinCellSOC_pct : Inport  Port=4
  GeUDS_CapSel_enum : Inport  Port=5
  3D_Config_Word{,1..3} (4 alike) : AIWAYS_Powertrain_BMS_lib/Signals/3D_Config_Word  Default_Cal_Breakpoint1_Name=CaSOP_ChrgContPwrTempTable_C  Default_Cal_Breakpoint2_Name=CaSOP_ChrgContPwrSOCTable_pct  Default_Cal_Table1_Name=CaSOP_ChrgContPwrTable_kW  CATL153Ah_Cal_Breakpoint1_Name=CaSOP_ChrgContPwrTempTableC153_C  CATL153Ah_Cal_Breakpoint2_Name=CaSOP_ChrgContPwrSOCTableC153_pct  CATL153Ah_Cal_Table1_Name=CaSOP_ChrgContPwrTableC153_kW  CATL180Ah_Cal_Breakpoint1_Name=CaSOP_ChrgContPwrTempTableC180_C  CATL180Ah_Cal_Breakpoint2_Name=CaSOP_ChrgContPwrSOCTableC180_pct  CATL180Ah_Cal_Table1_Name=CaSOP_ChrgContPwrTableC180_kW  CATL177Ah_Cal_Breakpoint1_Name=CaSOP_ChrgContPwrTempTableC177_C  CATL177Ah_Cal_Breakpoint2_Name=CaSOP_ChrgContPwrSOCTableC177_pct  CATL177Ah_Cal_Table1_Name=CaSOP_ChrgContPwrTableC177_kW  CATL203Ah_Cal_Breakpoint1_Name=CaSOP_ChrgContPwrTempTableC203_C  CATL203Ah_Cal_Breakpoint2_Name=CaSOP_ChrgContPwrSOCTableC203_pct  CATL203Ah_Cal_Table1_Name=CaSOP_ChrgContPwrTableC203_kW  CATL51Ah_Cal_Breakpoint1_Name=CaSOP_ChrgContPwrTempTableC51_C  CATL51Ah_Cal_Breakpoint2_Name=CaSOP_ChrgContPwrSOCTableC51_pct  CATL51Ah_Cal_Table1_Name=CaSOP_ChrgContPwrTableC51_kW  CATL132Ah_Cal_Breakpoint1_Name=CaSOP_ChrgContPwrTempTableC132_C  CATL132Ah_Cal_Breakpoint2_Name=CaSOP_ChrgContPwrSOCTableC132_pct  CATL132Ah_Cal_Table1_Name=CaSOP_ChrgContPwrTableC132_kW  XWD75Ah_Cal_Breakpoint1_Name=CaSOP_ChrgContPwrTempTableX75_C  XWD75Ah_Cal_Breakpoint2_Name=CaSOP_ChrgContPwrSOCTableX75_pct  XWD75Ah_Cal_Table1_Name=CaSOP_ChrgContPwrTableX75_kW  TFE177Ah_Cal_Breakpoint1_Name=CaSOP_ChrgContPwrTempTableT177_C  TFE177Ah_Cal_Breakpoint2_Name=CaSOP_ChrgContPwrSOCTableT177_pct  TFE177Ah_Cal_Table1_Name=CaSOP_ChrgContPwrTableT177_kW  CATLCTP248Ah_Cal_Breakpoint1_Name=CaSOP_ChrgContPwrTempTableC248_C  CATLCTP248Ah_Cal_Breakpoint2_Name=CaSOP_ChrgContPwrSOCTableC248_pct  CATLCTP248Ah_Cal_Table1_Name=CaSOP_ChrgContPwrTableC248_kW
  Bus Creator : BusCreator  Inputs=5
  Bus Selector4 : BusSelector  OutputSignals=GeUDS_CapSel_enum,GcCDP_MaxCellTemp_C,GcSOC_MaxCellSOC_pct
  Bus Selector5 : BusSelector  OutputSignals=GeUDS_CapSel_enum,GcCDP_MinCellTemp_C,GcSOC_MaxCellSOC_pct
  Bus Selector6 : BusSelector  OutputSignals=GeUDS_CapSel_enum,GcCDP_MaxCellTemp_C,GcSOC_MinCellSOC_pct
  Bus Selector7 : BusSelector  OutputSignals=GeUDS_CapSel_enum,GcCDP_MinCellTemp_C,GcSOC_MinCellSOC_pct
  Constant : Constant  Value=CcSOP_LookupTablePwrFactor_pct
  Divide : Product  Inputs=**  OutDataTypeStr=Inherit: Inherit via back propagation
  MinMax : MinMax  Inputs=4
  LcSOP_ChrgContTablePwr_kW : Outport
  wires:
  GcCDP_MaxCellTemp_C/1 -> Bus Creator/1  "GcCDP_MaxCellTemp_C"
  GcCDP_MinCellTemp_C/1 -> Bus Creator/2  "GcCDP_MinCellTemp_C"
  GcSOC_MaxCellSOC_pct/1 -> Bus Creator/3  "GcSOC_MaxCellSOC_pct"
  GcSOC_MinCellSOC_pct/1 -> Bus Creator/4  "GcSOC_MinCellSOC_pct"
  MinMax/1 -> Divide/1
  Divide/1 -> LcSOP_ChrgContTablePwr_kW/1  "LcSOP_ChrgContTablePwr_kW"
  Constant/1 -> Divide/2
  GeUDS_CapSel_enum/1 -> Bus Creator/5  "GeUDS_CapSel_enum"
  Bus Creator/1 -> Bus Selector7/1, Bus Selector6/1, Bus Selector5/1, Bus Selector4/1
  Bus Selector4/1 -> 3D_Config_Word/1  "<GeUDS_CapSel_enum>"
  Bus Selector4/2 -> 3D_Config_Word/2  "<GcCDP_MaxCellTemp_C>"
  Bus Selector4/3 -> 3D_Config_Word/3  "<GcSOC_MaxCellSOC_pct>"
  Bus Selector5/1 -> 3D_Config_Word1/1  "<GeUDS_CapSel_enum>"
  Bus Selector5/2 -> 3D_Config_Word1/2  "<GcCDP_MinCellTemp_C>"
  Bus Selector5/3 -> 3D_Config_Word1/3  "<GcSOC_MaxCellSOC_pct>"
  Bus Selector6/1 -> 3D_Config_Word2/1  "<GeUDS_CapSel_enum>"
  Bus Selector6/2 -> 3D_Config_Word2/2  "<GcCDP_MaxCellTemp_C>"
  Bus Selector6/3 -> 3D_Config_Word2/3  "<GcSOC_MinCellSOC_pct>"
  Bus Selector7/1 -> 3D_Config_Word3/1  "<GeUDS_CapSel_enum>"
  Bus Selector7/2 -> 3D_Config_Word3/2  "<GcCDP_MinCellTemp_C>"
  Bus Selector7/3 -> 3D_Config_Word3/3  "<GcSOC_MinCellSOC_pct>"
  3D_Config_Word/1 -> MinMax/1
  3D_Config_Word1/1 -> MinMax/2
  3D_Config_Word2/1 -> MinMax/3
  3D_Config_Word3/1 -> MinMax/4

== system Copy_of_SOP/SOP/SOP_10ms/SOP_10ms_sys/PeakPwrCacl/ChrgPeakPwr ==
  GcCDP_MaxCellTemp_C : Inport
  GcCDP_MinCellTemp_C : Inport  Port=2
  GcSOC_MaxCellSOC_pct : Inport  Port=3
  GcSOC_MinCellSOC_pct : Inport  Port=4
  GeUDS_CapSel_enum : Inport  Port=5
  3D_Config_Word{,1..3} (4 alike) : AIWAYS_Powertrain_BMS_lib/Signals/3D_Config_Word  Default_Cal_Breakpoint1_Name=CaSOP_ChrgPeakPwrTempTable_C  Default_Cal_Breakpoint2_Name=CaSOP_ChrgPeakPwrSOCTable_pct  Default_Cal_Table1_Name=CaSOP_ChrgPeakPwrTable_kW  CATL153Ah_Cal_Breakpoint1_Name=CaSOP_ChrgPeakPwrTempTableC153_C  CATL153Ah_Cal_Breakpoint2_Name=CaSOP_ChrgPeakPwrSOCTableC153_pct  CATL153Ah_Cal_Table1_Name=CaSOP_ChrgPeakPwrTableC153_kW  CATL180Ah_Cal_Breakpoint1_Name=CaSOP_ChrgPeakPwrTempTableC180_C  CATL180Ah_Cal_Breakpoint2_Name=CaSOP_ChrgPeakPwrSOCTableC180_pct  CATL180Ah_Cal_Table1_Name=CaSOP_ChrgPeakPwrTableC180_kW  CATL177Ah_Cal_Breakpoint1_Name=CaSOP_ChrgPeakPwrTempTableC177_C  CATL177Ah_Cal_Breakpoint2_Name=CaSOP_ChrgPeakPwrSOCTableC177_pct  CATL177Ah_Cal_Table1_Name=CaSOP_ChrgPeakPwrTableC177_kW  CATL203Ah_Cal_Breakpoint1_Name=CaSOP_ChrgPeakPwrTempTableC203_C  CATL203Ah_Cal_Breakpoint2_Name=CaSOP_ChrgPeakPwrSOCTableC203_pct  CATL203Ah_Cal_Table1_Name=CaSOP_ChrgPeakPwrTableC203_kW  CATL51Ah_Cal_Breakpoint1_Name=CaSOP_ChrgPeakPwrTempTableC51_C  CATL51Ah_Cal_Breakpoint2_Name=CaSOP_ChrgPeakPwrSOCTableC51_pct  CATL51Ah_Cal_Table1_Name=CaSOP_ChrgPeakPwrTableC51_kW  CATL132Ah_Cal_Breakpoint1_Name=CaSOP_ChrgPeakPwrTempTableC132_C  CATL132Ah_Cal_Breakpoint2_Name=CaSOP_ChrgPeakPwrSOCTableC132_pct  CATL132Ah_Cal_Table1_Name=CaSOP_ChrgPeakPwrTableC132_kW  XWD75Ah_Cal_Breakpoint1_Name=CaSOP_ChrgPeakPwrTempTableX75_C  XWD75Ah_Cal_Breakpoint2_Name=CaSOP_ChrgPeakPwrSOCTableX75_pct  XWD75Ah_Cal_Table1_Name=CaSOP_ChrgPeakPwrTableX75_kW  TFE177Ah_Cal_Breakpoint1_Name=CaSOP_ChrgPeakPwrTempTableT177_C  TFE177Ah_Cal_Breakpoint2_Name=CaSOP_ChrgPeakPwrSOCTableT177_pct  TFE177Ah_Cal_Table1_Name=CaSOP_ChrgPeakPwrTableT177_kW  CATLCTP248Ah_Cal_Breakpoint1_Name=CaSOP_ChrgPeakPwrTempTableC248_C  CATLCTP248Ah_Cal_Breakpoint2_Name=CaSOP_ChrgPeakPwrSOCTableC248_pct  CATLCTP248Ah_Cal_Table1_Name=CaSOP_ChrgPeakPwrTableC248_kW
  Bus Creator : BusCreator  Inputs=5
  Bus Selector4 : BusSelector  OutputSignals=GeUDS_CapSel_enum,GcCDP_MaxCellTemp_C,GcSOC_MaxCellSOC_pct
  Bus Selector5 : BusSelector  OutputSignals=GeUDS_CapSel_enum,GcCDP_MinCellTemp_C,GcSOC_MaxCellSOC_pct
  Bus Selector6 : BusSelector  OutputSignals=GeUDS_CapSel_enum,GcCDP_MaxCellTemp_C,GcSOC_MinCellSOC_pct
  Bus Selector7 : BusSelector  OutputSignals=GeUDS_CapSel_enum,GcCDP_MinCellTemp_C,GcSOC_MinCellSOC_pct
  Constant : Constant  Value=CcSOP_LookupTablePwrFactor_pct
  Divide : Product  Inputs=**  OutDataTypeStr=Inherit: Inherit via back propagation
  MinMax : MinMax  Inputs=4
  LcSOP_ChrgPeakTablePwr_kW : Outport
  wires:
  Constant/1 -> Divide/2
  Divide/1 -> LcSOP_ChrgPeakTablePwr_kW/1  "LcSOP_ChrgPeakTablePwr_kW"
  MinMax/1 -> Divide/1
  GcSOC_MinCellSOC_pct/1 -> Bus Creator/4  "GcSOC_MinCellSOC_pct"
  GcSOC_MaxCellSOC_pct/1 -> Bus Creator/3  "GcSOC_MaxCellSOC_pct"
  GcCDP_MinCellTemp_C/1 -> Bus Creator/2  "GcCDP_MinCellTemp_C"
  GcCDP_MaxCellTemp_C/1 -> Bus Creator/1  "GcCDP_MaxCellTemp_C"
  GeUDS_CapSel_enum/1 -> Bus Creator/5  "GeUDS_CapSel_enum"
  Bus Creator/1 -> Bus Selector7/1, Bus Selector6/1, Bus Selector5/1, Bus Selector4/1
  3D_Config_Word/1 -> MinMax/1
  Bus Selector4/1 -> 3D_Config_Word/1  "<GeUDS_CapSel_enum>"
  Bus Selector4/2 -> 3D_Config_Word/2  "<GcCDP_MaxCellTemp_C>"
  Bus Selector4/3 -> 3D_Config_Word/3  "<GcSOC_MaxCellSOC_pct>"
  Bus Selector5/1 -> 3D_Config_Word1/1  "<GeUDS_CapSel_enum>"
  Bus Selector5/2 -> 3D_Config_Word1/2  "<GcCDP_MinCellTemp_C>"
  Bus Selector5/3 -> 3D_Config_Word1/3  "<GcSOC_MaxCellSOC_pct>"
  Bus Selector6/1 -> 3D_Config_Word2/1  "<GeUDS_CapSel_enum>"
  Bus Selector6/2 -> 3D_Config_Word2/2  "<GcCDP_MaxCellTemp_C>"
  Bus Selector6/3 -> 3D_Config_Word2/3  "<GcSOC_MinCellSOC_pct>"
  Bus Selector7/1 -> 3D_Config_Word3/1  "<GeUDS_CapSel_enum>"
  Bus Selector7/2 -> 3D_Config_Word3/2  "<GcCDP_MinCellTemp_C>"
  Bus Selector7/3 -> 3D_Config_Word3/3  "<GcSOC_MinCellSOC_pct>"
  3D_Config_Word1/1 -> MinMax/2
  3D_Config_Word2/1 -> MinMax/3
  3D_Config_Word3/1 -> MinMax/4

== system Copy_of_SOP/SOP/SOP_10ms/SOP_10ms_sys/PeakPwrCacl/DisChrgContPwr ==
  GcCDP_MaxCellTemp_C : Inport
  GcCDP_MinCellTemp_C : Inport  Port=2
  GcSOC_MaxCellSOC_pct : Inport  Port=3
  GcSOC_MinCellSOC_pct : Inport  Port=4
  GeUDS_CapSel_enum : Inport  Port=5
  3D_Config_Word{,2..4} (4 alike) : AIWAYS_Powertrain_BMS_lib/Signals/3D_Config_Word  Default_Cal_Breakpoint1_Name=CaSOP_DisChrgContPwrTempTable_C  Default_Cal_Breakpoint2_Name=CaSOP_DisChrgContPwrSOCTable_pct  Default_Cal_Table1_Name=CaSOP_DisChrgContPwrTable_kW  CATL153Ah_Cal_Breakpoint1_Name=CaSOP_DisChrgContPwrTempTableC153_C  CATL153Ah_Cal_Breakpoint2_Name=CaSOP_DisChrgContPwrSOCTableC153_pct  CATL153Ah_Cal_Table1_Name=CaSOP_DisChrgContPwrTableC153_kW  CATL180Ah_Cal_Breakpoint1_Name=CaSOP_DisChrgContPwrTempTableC180_C  CATL180Ah_Cal_Breakpoint2_Name=CaSOP_DisChrgContPwrSOCTableC180_pct  CATL180Ah_Cal_Table1_Name=CaSOP_DisChrgContPwrTableC180_kW  CATL177Ah_Cal_Breakpoint1_Name=CaSOP_DisChrgContPwrTempTableC177_C  CATL177Ah_Cal_Breakpoint2_Name=CaSOP_DisChrgContPwrSOCTableC177_pct  CATL177Ah_Cal_Table1_Name=CaSOP_DisChrgContPwrTableC177_kW  CATL203Ah_Cal_Breakpoint1_Name=CaSOP_DisChrgContPwrTempTableC203_C  CATL203Ah_Cal_Breakpoint2_Name=CaSOP_DisChrgContPwrSOCTableC203_pct  CATL203Ah_Cal_Table1_Name=CaSOP_DisChrgContPwrTableC203_kW  CATL51Ah_Cal_Breakpoint1_Name=CaSOP_DisChrgContPwrTempTableC51_C  CATL51Ah_Cal_Breakpoint2_Name=CaSOP_DisChrgContPwrSOCTableC51_pct  CATL51Ah_Cal_Table1_Name=CaSOP_DisChrgContPwrTableC51_kW  CATL132Ah_Cal_Breakpoint1_Name=CaSOP_DisChrgContPwrTempTableC132_C  CATL132Ah_Cal_Breakpoint2_Name=CaSOP_DisChrgContPwrSOCTableC132_pct  CATL132Ah_Cal_Table1_Name=CaSOP_DisChrgContPwrTableC132_kW  XWD75Ah_Cal_Breakpoint1_Name=CaSOP_DisChrgContPwrTempTableX75_C  XWD75Ah_Cal_Breakpoint2_Name=CaSOP_DisChrgContPwrSOCTableX75_pct  XWD75Ah_Cal_Table1_Name=CaSOP_DisChrgContPwrTableX75_kW  TFE177Ah_Cal_Breakpoint1_Name=CaSOP_DisChrgContPwrTempTableT177_C  TFE177Ah_Cal_Breakpoint2_Name=CaSOP_DisChrgContPwrSOCTableT177_pct  TFE177Ah_Cal_Table1_Name=CaSOP_DisChrgContPwrTableT177_kW  CATLCTP248Ah_Cal_Breakpoint1_Name=CaSOP_DisChrgContPwrTempTableC248_C  CATLCTP248Ah_Cal_Breakpoint2_Name=CaSOP_DisChrgContPwrSOCTableC248_pct  CATLCTP248Ah_Cal_Table1_Name=CaSOP_DisChrgContPwrTableC248_kW
  Bus Creator : BusCreator  Inputs=5
  Bus Selector : BusSelector  OutputSignals=GeUDS_CapSel_enum,GcCDP_MaxCellTemp_C,GcSOC_MaxCellSOC_pct
  Bus Selector1 : BusSelector  OutputSignals=GeUDS_CapSel_enum,GcCDP_MinCellTemp_C,GcSOC_MaxCellSOC_pct
  Bus Selector2 : BusSelector  OutputSignals=GeUDS_CapSel_enum,GcCDP_MaxCellTemp_C,GcSOC_MinCellSOC_pct
  Bus Selector3 : BusSelector  OutputSignals=GeUDS_CapSel_enum,GcCDP_MinCellTemp_C,GcSOC_MinCellSOC_pct
  Constant : Constant  Value=CcSOP_LookupTablePwrFactor_pct
  Divide : Product  Inputs=**  OutDataTypeStr=Inherit: Inherit via back propagation
  MinMax : MinMax  Inputs=4
  LcSOP_DisChrgContTablePwr_kW : Outport
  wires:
  Constant/1 -> Divide/2
  Divide/1 -> LcSOP_DisChrgContTablePwr_kW/1  "LcSOP_DisChrgContTablePwr_kW"
  MinMax/1 -> Divide/1
  Bus Creator/1 -> Bus Selector/1, Bus Selector3/1, Bus Selector2/1, Bus Selector1/1
  GcSOC_MinCellSOC_pct/1 -> Bus Creator/4  "GcSOC_MinCellSOC_pct"
  GcSOC_MaxCellSOC_pct/1 -> Bus Creator/3  "GcSOC_MaxCellSOC_pct"
  GcCDP_MinCellTemp_C/1 -> Bus Creator/2  "GcCDP_MinCellTemp_C"
  GcCDP_MaxCellTemp_C/1 -> Bus Creator/1  "GcCDP_MaxCellTemp_C"
  GeUDS_CapSel_enum/1 -> Bus Creator/5  "GeUDS_CapSel_enum"
  Bus Selector/1 -> 3D_Config_Word/1  "<GeUDS_CapSel_enum>"
  Bus Selector/2 -> 3D_Config_Word/2  "<GcCDP_MaxCellTemp_C>"
  Bus Selector/3 -> 3D_Config_Word/3  "<GcSOC_MaxCellSOC_pct>"
  3D_Config_Word/1 -> MinMax/1
  Bus Selector1/1 -> 3D_Config_Word2/1  "<GeUDS_CapSel_enum>"
  Bus Selector1/2 -> 3D_Config_Word2/2  "<GcCDP_MinCellTemp_C>"
  Bus Selector1/3 -> 3D_Config_Word2/3  "<GcSOC_MaxCellSOC_pct>"
  Bus Selector2/1 -> 3D_Config_Word3/1  "<GeUDS_CapSel_enum>"
  Bus Selector2/2 -> 3D_Config_Word3/2  "<GcCDP_MaxCellTemp_C>"
  Bus Selector2/3 -> 3D_Config_Word3/3  "<GcSOC_MinCellSOC_pct>"
  Bus Selector3/1 -> 3D_Config_Word4/1  "<GeUDS_CapSel_enum>"
  Bus Selector3/2 -> 3D_Config_Word4/2  "<GcCDP_MinCellTemp_C>"
  Bus Selector3/3 -> 3D_Config_Word4/3  "<GcSOC_MinCellSOC_pct>"
  3D_Config_Word2/1 -> MinMax/2
  3D_Config_Word3/1 -> MinMax/3
  3D_Config_Word4/1 -> MinMax/4

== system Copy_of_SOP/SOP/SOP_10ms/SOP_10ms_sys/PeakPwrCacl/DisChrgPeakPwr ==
  GcCDP_MaxCellTemp_C : Inport
  GcCDP_MinCellTemp_C : Inport  Port=2
  GcSOC_MaxCellSOC_pct : Inport  Port=3
  GcSOC_MinCellSOC_pct : Inport  Port=4
  GeUDS_CapSel_enum : Inport  Port=5
  3D_Config_Word{,1..3} (4 alike) : AIWAYS_Powertrain_BMS_lib/Signals/3D_Config_Word  Default_Cal_Breakpoint1_Name=CaSOP_DisChrgPeakPwrTempTable_C  Default_Cal_Breakpoint2_Name=CaSOP_DisChrgPeakPwrSOCTable_pct  Default_Cal_Table1_Name=CaSOP_DisChrgPeakPwrTable_kW  CATL153Ah_Cal_Breakpoint1_Name=CaSOP_DisChrgPeakPwrTempTableC153_C  CATL153Ah_Cal_Breakpoint2_Name=CaSOP_DisChrgPeakPwrSOCTableC153_pct  CATL153Ah_Cal_Table1_Name=CaSOP_DisChrgPeakPwrTableC153_kW  CATL180Ah_Cal_Breakpoint1_Name=CaSOP_DisChrgPeakPwrTempTableC180_C  CATL180Ah_Cal_Breakpoint2_Name=CaSOP_DisChrgPeakPwrSOCTableC180_pct  CATL180Ah_Cal_Table1_Name=CaSOP_DisChrgPeakPwrTableC180_kW  CATL177Ah_Cal_Breakpoint1_Name=CaSOP_DisChrgPeakPwrTempTableC177_C  CATL177Ah_Cal_Breakpoint2_Name=CaSOP_DisChrgPeakPwrSOCTableC177_pct  CATL177Ah_Cal_Table1_Name=CaSOP_DisChrgPeakPwrTableC177_kW  CATL203Ah_Cal_Breakpoint1_Name=CaSOP_DisChrgPeakPwrTempTableC203_C  CATL203Ah_Cal_Breakpoint2_Name=CaSOP_DisChrgPeakPwrSOCTableC203_pct  CATL203Ah_Cal_Table1_Name=CaSOP_DisChrgPeakPwrTableC203_kW  CATL51Ah_Cal_Breakpoint1_Name=CaSOP_DisChrgPeakPwrTempTableC51_C  CATL51Ah_Cal_Breakpoint2_Name=CaSOP_DisChrgPeakPwrSOCTableC51_pct  CATL51Ah_Cal_Table1_Name=CaSOP_DisChrgPeakPwrTableC51_kW  CATL132Ah_Cal_Breakpoint1_Name=CaSOP_DisChrgPeakPwrTempTableC132_C  CATL132Ah_Cal_Breakpoint2_Name=CaSOP_DisChrgPeakPwrSOCTableC132_pct  CATL132Ah_Cal_Table1_Name=CaSOP_DisChrgPeakPwrTableC132_kW  XWD75Ah_Cal_Breakpoint1_Name=CaSOP_DisChrgPeakPwrTempTableX75_C  XWD75Ah_Cal_Breakpoint2_Name=CaSOP_DisChrgPeakPwrSOCTableX75_pct  XWD75Ah_Cal_Table1_Name=CaSOP_DisChrgPeakPwrTableX75_kW  TFE177Ah_Cal_Breakpoint1_Name=CaSOP_DisChrgPeakPwrTempTableT177_C  TFE177Ah_Cal_Breakpoint2_Name=CaSOP_DisChrgPeakPwrSOCTableT177_pct  TFE177Ah_Cal_Table1_Name=CaSOP_DisChrgPeakPwrTableT177_kW  CATLCTP248Ah_Cal_Breakpoint1_Name=CaSOP_DisChrgPeakPwrTempTableC248_C  CATLCTP248Ah_Cal_Breakpoint2_Name=CaSOP_DisChrgPeakPwrSOCTableC248_pct  CATLCTP248Ah_Cal_Table1_Name=CaSOP_DisChrgPeakPwrTableC248_kW
  Bus Creator : BusCreator  Inputs=5
  Bus Selector : BusSelector  OutputSignals=GeUDS_CapSel_enum,GcCDP_MaxCellTemp_C,GcSOC_MaxCellSOC_pct
  Bus Selector1 : BusSelector  OutputSignals=GeUDS_CapSel_enum,GcCDP_MaxCellTemp_C,GcSOC_MinCellSOC_pct
  Bus Selector2 : BusSelector  OutputSignals=GeUDS_CapSel_enum,GcCDP_MinCellTemp_C,GcSOC_MaxCellSOC_pct
  Bus Selector3 : BusSelector  OutputSignals=GeUDS_CapSel_enum,GcCDP_MinCellTemp_C,GcSOC_MinCellSOC_pct
  Constant : Constant  Value=CcSOP_LookupTablePwrFactor_pct
  Divide : Product  Inputs=**  OutDataTypeStr=Inherit: Inherit via back propagation
  MinMax : MinMax  Inputs=4
  LcSOP_DisChrgPeakTablePwr_kW : Outport
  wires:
  GcCDP_MaxCellTemp_C/1 -> Bus Creator/1  "GcCDP_MaxCellTemp_C"
  GcCDP_MinCellTemp_C/1 -> Bus Creator/2  "GcCDP_MinCellTemp_C"
  GcSOC_MaxCellSOC_pct/1 -> Bus Creator/3  "GcSOC_MaxCellSOC_pct"
  GcSOC_MinCellSOC_pct/1 -> Bus Creator/4  "GcSOC_MinCellSOC_pct"
  Bus Creator/1 -> Bus Selector/1, Bus Selector1/1, Bus Selector3/1, Bus Selector2/1
  MinMax/1 -> Divide/1
  Divide/1 -> LcSOP_DisChrgPeakTablePwr_kW/1  "LcSOP_DisChrgPeakTablePwr_kW"
  Constant/1 -> Divide/2
  GeUDS_CapSel_enum/1 -> Bus Creator/5  "GeUDS_CapSel_enum"
  Bus Selector/1 -> 3D_Config_Word/1  "<GeUDS_CapSel_enum>"
  Bus Selector/2 -> 3D_Config_Word/2  "<GcCDP_MaxCellTemp_C>"
  Bus Selector/3 -> 3D_Config_Word/3  "<GcSOC_MaxCellSOC_pct>"
  Bus Selector1/1 -> 3D_Config_Word1/1  "<GeUDS_CapSel_enum>"
  Bus Selector1/2 -> 3D_Config_Word1/2  "<GcCDP_MaxCellTemp_C>"
  Bus Selector1/3 -> 3D_Config_Word1/3  "<GcSOC_MinCellSOC_pct>"
  Bus Selector2/1 -> 3D_Config_Word2/1  "<GeUDS_CapSel_enum>"
  Bus Selector2/2 -> 3D_Config_Word2/2  "<GcCDP_MinCellTemp_C>"
  Bus Selector2/3 -> 3D_Config_Word2/3  "<GcSOC_MaxCellSOC_pct>"
  Bus Selector3/1 -> 3D_Config_Word3/1  "<GeUDS_CapSel_enum>"
  Bus Selector3/2 -> 3D_Config_Word3/2  "<GcCDP_MinCellTemp_C>"
  Bus Selector3/3 -> 3D_Config_Word3/3  "<GcSOC_MinCellSOC_pct>"
  3D_Config_Word/1 -> MinMax/1
  3D_Config_Word1/1 -> MinMax/2
  3D_Config_Word2/1 -> MinMax/3
  3D_Config_Word3/1 -> MinMax/4

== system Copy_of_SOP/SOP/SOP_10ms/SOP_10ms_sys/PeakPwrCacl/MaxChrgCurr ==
  GcCDP_MaxCellTemp_C : Inport
  GcCDP_MinCellTemp_C : Inport  Port=2
  GcCDP_MaxCellVolt_mV : Inport  Port=3
  GcCDP_MinCellVolt_mV : Inport  Port=4
  GeUDS_CapSel_enum : Inport  Port=5
  Enable : EnablePort  StatesWhenEnabling=reset
  MaxChrgCurr_Update : Subsystem
  MaxDCChrgCurr : Subsystem
  LcSOP_MaxChrgTableCurr_A : Outport
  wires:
  MaxDCChrgCurr/1(LcSOP_OrigMaxChrgTableCurr_A) -> MaxChrgCurr_Update/1(LcSOP_OrigMaxChrgTableCurr_A)
  MaxChrgCurr_Update/1(LcSOP_MaxChrgTableCurr_A) -> LcSOP_MaxChrgTableCurr_A/1
  GcCDP_MaxCellTemp_C/1 -> MaxDCChrgCurr/1(GcCDP_MaxCellTemp_C)
  GcCDP_MinCellTemp_C/1 -> MaxDCChrgCurr/2(GcCDP_MinCellTemp_C)
  GcCDP_MaxCellVolt_mV/1 -> MaxDCChrgCurr/3(GcCDP_MaxCellVolt_mV)
  GcCDP_MinCellVolt_mV/1 -> MaxDCChrgCurr/4(GcCDP_MinCellVolt_mV)
  GeUDS_CapSel_enum/1 -> MaxDCChrgCurr/5(GeUDS_CapSel_enum)

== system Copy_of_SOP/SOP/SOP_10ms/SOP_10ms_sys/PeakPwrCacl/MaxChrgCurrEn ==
  GeCTC_CtrCtlConnMode_enum : Inport
  GeMSM_BMUState_enum : Inport  Port=2
  Constant : Constant  Value=Enum_MSMBMUState.Enum_MSMBMUState_Run
  Constant1 : Constant  Value=Enum_CTCCtrCtlConnMode.Enum_CTCCtrCtlConnMode_EDCChrg
  Constant2 : Constant  Value=Enum_CTCCtrCtlConnMode.Enum_CTCCtrCtlConnMode_ACChrg
  Constant3 : Constant  Value=Enum_CTCCtrCtlConnMode.Enum_CTCCtrCtlConnMode_DCChrg
  Data Type Conversion1 : DataTypeConversion
  Data Type Conversion2 : DataTypeConversion
  Logical Operator2 : Logic  AllPortsSameDT=off  OutDataTypeStr=boolean
  Logical Operator5 : Logic  Operator=OR  Inputs=3  AllPortsSameDT=off  OutDataTypeStr=boolean
  Relational Operator{,2..4} (4 alike) : RelationalOperator  Operator===  OutDataTypeStr=boolean
  LbSOP_MaxChrgCurrEn_flg : Outport
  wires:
  GeCTC_CtrCtlConnMode_enum/1 -> Data Type Conversion2/1
  Constant3/1 -> Relational Operator3/2
  Relational Operator2/1 -> Logical Operator5/2
  Relational Operator3/1 -> Logical Operator5/1
  Relational Operator4/1 -> Logical Operator5/3
  Data Type Conversion2/1 -> Relational Operator3/1, Relational Operator2/1, Relational Operator4/1
  Constant1/1 -> Relational Operator2/2
  Constant2/1 -> Relational Operator4/2
  Constant/1 -> Relational Operator/2
  GeMSM_BMUState_enum/1 -> Data Type Conversion1/1
  Data Type Conversion1/1 -> Relational Operator/1
  Relational Operator/1 -> Logical Operator2/2
  Logical Operator2/1 -> LbSOP_MaxChrgCurrEn_flg/1  "LbSOP_MaxChrgCurrEn_flg"
  Logical Operator5/1 -> Logical Operator2/1

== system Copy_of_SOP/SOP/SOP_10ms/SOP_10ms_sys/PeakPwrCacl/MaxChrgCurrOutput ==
  LcSOP_MaxChrgTableCurr_A : Inport
  GeFTC_FltLevel_enum : Inport  Port=2
  GbISP_OpenContactor_flg : Inport  Port=3
  GbISP_PowerDown_flg : Inport  Port=4
  GbISP_DCChrgCurrLimitLevel2_flg : Inport  Port=5
  Bus Creator : BusCreator  Inputs=5
  Bus Selector1 : BusSelector  OutputSignals=LcSOP_MaxChrgTableCurr_A
  Bus Selector2 : BusSelector  OutputSignals=LcSOP_MaxChrgTableCurr_A
  Bus Selector3 : BusSelector  OutputSignals=GbISP_DCChrgCurrLimitLevel2_flg
  Bus Selector6 : BusSelector  OutputSignals=GbISP_PowerDown_flg
  Bus Selector7 : BusSelector  OutputSignals=GbISP_OpenContactor_flg
  Constant5 : Constant  Value=SOP_CONST0_NUMB
  Constant7 : Constant  Value=CcSOP_MaxChrgCurrLimitFactorLevel2_numb
  Data Type Conversion : DataTypeConversion
  Data Type Conversion5 : DataTypeConversion
  Divide : Product  Inputs=**
  Logical Operator : Logic  Operator=OR  AllPortsSameDT=off  OutDataTypeStr=boolean
  OverWrite : AIWAYS_Powertrain_BMS_lib/Signals/OverWrite  OverWrite_Value=CcSOP_MaxChrgCurrOvr_A  OverWrite_flag=CbSOP_MaxChrgCurrOvrSwt_flg
  Switch1 : Switch  Criteria=u2 ~= 0
  Switch2 : Switch  Criteria=u2 ~= 0
  GcSOP_MaxChrgCurr_A : Outport
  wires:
  OverWrite/1 -> GcSOP_MaxChrgCurr_A/1  "GcSOP_MaxChrgCurr_A"
  LcSOP_MaxChrgTableCurr_A/1 -> Bus Creator/2
  GeFTC_FltLevel_enum/1 -> Data Type Conversion5/1
  Constant5/1 -> Data Type Conversion/1
  Bus Selector7/1 -> Logical Operator/1  "<GbISP_OpenContactor_flg>"
  Bus Selector6/1 -> Logical Operator/2  "<GbISP_PowerDown_flg>"
  Logical Operator/1 -> Switch1/2
  Switch2/1 -> Switch1/3
  Bus Selector3/1 -> Switch2/2  "<GbISP_DCChrgCurrLimitLevel2_flg>"
  Divide/1 -> Switch2/1
  Constant7/1 -> Divide/2
  Switch1/1 -> OverWrite/1
  Data Type Conversion5/1 -> Bus Creator/1  "GeFTC_FltLevel_enum"
  Bus Creator/1 -> Bus Selector2/1, Bus Selector3/1, Bus Selector1/1, Bus Selector6/1, Bus Selector7/1
  Bus Selector1/1 -> Divide/1  "<LcSOP_MaxChrgTableCurr_A>"
  Bus Selector2/1 -> Switch2/3  "<LcSOP_MaxChrgTableCurr_A>"
  GbISP_OpenContactor_flg/1 -> Bus Creator/3
  GbISP_PowerDown_flg/1 -> Bus Creator/4
  GbISP_DCChrgCurrLimitLevel2_flg/1 -> Bus Creator/5
  Data Type Conversion/1 -> Switch1/1

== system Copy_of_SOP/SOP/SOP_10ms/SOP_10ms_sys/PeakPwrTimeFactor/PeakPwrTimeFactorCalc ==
  LcSOP_PackDisChrgPeakTablePwr_kW : Inport
  LcSOP_PackDisChrgContTablePwr_kW : Inport  Port=2
  LcSOP_PackChrgPeakTablePwr_kW : Inport  Port=3
  LcSOP_PackChrgContTablePwr_kW : Inport  Port=4
  GcHDP_PackCrnt_A : Inport  Port=5
  GcHDP_PackVolt_V : Inport  Port=6
  GeFTC_FltLevel_enum : Inport  Port=7
  GbISP_OpenContactor_flg : Inport  Port=8
  GbISP_PowerDown_flg : Inport  Port=9
  GbISP_DischrgPwrLimitLevel3_flg : Inport  Port=10
  GbISP_RegenPwrLimitLevel3_flg : Inport  Port=11
  GbISP_DischrgPwrLimitLevel2_flg : Inport  Port=12
  GbISP_RegenPwrLimitLevel2_flg : Inport  Port=13
  GbISP_DischrgPwrLimitLevel1_flg : Inport  Port=14
  GbISP_RegenPwrLimitLevel1_flg : Inport  Port=15
  GcCDP_MinCellVolt_mV : Inport  Port=16
  GcCDP_MaxCellVolt_mV : Inport  Port=17
  GcCDP_MinCellTemp_C : Inport  Port=18
  GcSOH_PackSOH_pct : Inport  Port=19
  GeUDS_CapSel_enum : Inport  Port=20
  Enable : EnablePort  StatesWhenEnabling=reset
  Bus Creator1 : BusCreator  Inputs=6
  Bus Creator2 : BusCreator  Inputs=6
  Bus Selector1 : BusSelector  OutputSignals=LcSOP_ChrgPeakPwr_kW,LcSOP_ChrgContPwr_kW,GcHDP_PackCrnt_A,GcHDP_PackVolt_V
  Bus Selector2 : BusSelector  OutputSignals=LcSOP_DisChrgPeakPwr_kW,LcSOP_DisChrgContPwr_kW,GcHDP_PackCrnt_A,GcHDP_PackVolt_V
  Bus Selector3 : BusSelector  OutputSignals=LcSOP_DisChrgPeakPwr_kW,LcSOP_DisChrgContPwr_kW,LcSOP_ChrgPeakPwr_kW,LcSOP_ChrgContPwr_kW
  Bus Selector4 : BusSelector  OutputSignals=LbSOP_DisChrgDetLevel1_flg,LbSOP_DisChrgHealLevel1_flg,LbSOP_DisChrgFloorFlag_flg,LbSOP_ChrgFloorFlag_flg
  Bus Selector5 : BusSelector  OutputSignals=LbSOP_DisChrgDetLevel1_flg,LbSOP_DisChrgHealLevel1_flg,LbSOP_DisChrgFloorFlag_flg,LbSOP_ChrgFloorFlag_flg,GcHDP_PackCrnt_A,GcHDP_PackVolt_V
  ChrgTimeFactor : Subsystem
  DisChrgTimeFactor : Subsystem
  PwrLimit : Subsystem
  PwrLimitFlg : Subsystem
  LcSOP_DisChrgPeakPwr_kW : Outport
  LcSOP_DisChrgContPwr_kW : Outport  Port=2
  LcSOP_ChrgPeakPwr_kW : Outport  Port=3
  LcSOP_ChrgContPwr_kW : Outport  Port=4
  LcSOP_DischrgPwrFactor_pct : Outport  Port=5
  LcSOP_ChrgPwrFactor_pct : Outport  Port=6
  LbSOP_DisChrgDetLevel1_flg : Outport  Port=7
  LbSOP_DisChrgHealLevel1_flg : Outport  Port=8
  LbSOP_DisChrgFloorFlag_flg : Outport  Port=9
  LbSOP_ChrgFloorFlag_flg : Outport  Port=10
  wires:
  Bus Selector3/2 -> LcSOP_DisChrgContPwr_kW/1  "<LcSOP_DisChrgContPwr_kW>"
  Bus Selector3/1 -> LcSOP_DisChrgPeakPwr_kW/1  "<LcSOP_DisChrgPeakPwr_kW>"
  Bus Selector1/1 -> ChrgTimeFactor/1(LcSOP_ChrgPeakPwr_kW)  "<LcSOP_ChrgPeakPwr_kW>"
  Bus Selector1/2 -> ChrgTimeFactor/2(LcSOP_ChrgContPwr_kW)  "<LcSOP_ChrgContPwr_kW>"
  Bus Selector2/1 -> DisChrgTimeFactor/1(LcSOP_DisChrgPeakPwr_kW)  "<LcSOP_DisChrgPeakPwr_kW>"
  Bus Selector2/2 -> DisChrgTimeFactor/2(LcSOP_DisChrgContPwr_kW)  "<LcSOP_DisChrgContPwr_kW>"
  GeFTC_FltLevel_enum/1 -> PwrLimit/5(GeFTC_FltLevel_enum)
  LcSOP_PackChrgContTablePwr_kW/1 -> PwrLimit/4(LcSOP_PackChrgContTablePwr_kW)
  LcSOP_PackChrgPeakTablePwr_kW/1 -> PwrLimit/3(LcSOP_PackChrgPeakTablePwr_kW)
  LcSOP_PackDisChrgContTablePwr_kW/1 -> PwrLimit/2(LcSOP_PackDisChrgContTablePwr_kW)
  LcSOP_PackDisChrgPeakTablePwr_kW/1 -> PwrLimit/1(LcSOP_PackDisChrgPeakTablePwr_kW)
  Bus Selector2/4 -> DisChrgTimeFactor/4(GcHDP_PackVolt_V)  "<GcHDP_PackVolt_V>"
  Bus Selector2/3 -> DisChrgTimeFactor/3(GcHDP_PackCrnt_A)  "<GcHDP_PackCrnt_A>"
  Bus Selector1/3 -> ChrgTimeFactor/3(GcHDP_PackCrnt_A)  "<GcHDP_PackCrnt_A>"
  Bus Selector1/4 -> ChrgTimeFactor/4(GcHDP_PackVolt_V)  "<GcHDP_PackVolt_V>"
  DisChrgTimeFactor/1(LcSOP_DischrgPwrFactor_pct) -> LcSOP_DischrgPwrFactor_pct/1
  ChrgTimeFactor/1(LcSOP_ChrgPwrFactor_pct) -> LcSOP_ChrgPwrFactor_pct/1
  Bus Selector3/4 -> LcSOP_ChrgContPwr_kW/1  "<LcSOP_ChrgContPwr_kW>"
  Bus Selector3/3 -> LcSOP_ChrgPeakPwr_kW/1  "<LcSOP_ChrgPeakPwr_kW>"
  GbISP_OpenContactor_flg/1 -> PwrLimit/6(GbISP_OpenContactor_flg)
  GbISP_PowerDown_flg/1 -> PwrLimit/7(GbISP_PowerDown_flg)
  GbISP_DischrgPwrLimitLevel3_flg/1 -> PwrLimit/8(GbISP_DischrgPwrLimitLevel3_flg)
  GbISP_RegenPwrLimitLevel3_flg/1 -> PwrLimit/9(GbISP_RegenPwrLimitLevel3_flg)
  GbISP_DischrgPwrLimitLevel2_flg/1 -> PwrLimit/10(GbISP_DischrgPwrLimitLevel2_flg)
  GbISP_RegenPwrLimitLevel2_flg/1 -> PwrLimit/11(GbISP_RegenPwrLimitLevel2_flg)
  GbISP_DischrgPwrLimitLevel1_flg/1 -> PwrLimit/12(GbISP_DischrgPwrLimitLevel1_flg)
  GbISP_RegenPwrLimitLevel1_flg/1 -> PwrLimit/13(GbISP_RegenPwrLimitLevel1_flg)
  GcCDP_MinCellVolt_mV/1 -> PwrLimitFlg/1(GcCDP_MinCellVolt_mV)
  GcCDP_MinCellTemp_C/1 -> PwrLimitFlg/2(GcCDP_MinCellTemp_C)
  GcCDP_MaxCellVolt_mV/1 -> PwrLimitFlg/3(GcCDP_MaxCellVolt_mV)
  PwrLimitFlg/1(LbSOP_DisChrgDetLevel1_flg) -> Bus Creator1/1
  PwrLimitFlg/2(LbSOP_DisChrgHealLevel1_flg) -> Bus Creator1/2
  PwrLimitFlg/3(LbSOP_DisChrgFloorFlag_flg) -> Bus Creator1/3
  PwrLimitFlg/4(LbSOP_ChrgFloorFlag_flg) -> Bus Creator1/4
  Bus Creator1/1 -> Bus Selector4/1, Bus Selector5/1
  Bus Selector4/1 -> LbSOP_DisChrgDetLevel1_flg/1  "<LbSOP_DisChrgDetLevel1_flg>"
  Bus Selector4/2 -> LbSOP_DisChrgHealLevel1_flg/1  "<LbSOP_DisChrgHealLevel1_flg>"
  Bus Selector4/3 -> LbSOP_DisChrgFloorFlag_flg/1  "<LbSOP_DisChrgFloorFlag_flg>"
  Bus Selector4/4 -> LbSOP_ChrgFloorFlag_flg/1  "<LbSOP_ChrgFloorFlag_flg>"
  Bus Selector5/1 -> PwrLimit/14(LbSOP_DisChrgDetLevel1_flg)  "<LbSOP_DisChrgDetLevel1_flg>"
  Bus Selector5/2 -> PwrLimit/15(LbSOP_DisChrgHealLevel1_flg)  "<LbSOP_DisChrgHealLevel1_flg>"
  Bus Selector5/3 -> PwrLimit/16(LbSOP_DisChrgFloorFlag_flg)  "<LbSOP_DisChrgFloorFlag_flg>"
  Bus Selector5/4 -> PwrLimit/17(LbSOP_ChrgFloorFlag_flg)  "<LbSOP_ChrgFloorFlag_flg>"
  PwrLimit/1(LcSOP_DisChrgPeakPwr_kW) -> Bus Creator2/1
  PwrLimit/2(LcSOP_DisChrgContPwr_kW) -> Bus Creator2/2
  PwrLimit/3(LcSOP_ChrgPeakPwr_kW) -> Bus Creator2/3
  PwrLimit/4(LcSOP_ChrgContPwr_kW) -> Bus Creator2/4
  GcHDP_PackCrnt_A/1 -> Bus Creator1/5
  GcHDP_PackVolt_V/1 -> Bus Creator1/6
  Bus Selector5/5 -> Bus Creator2/5, PwrLimit/18(GcHDP_PackCrnt_A)  "<GcHDP_PackCrnt_A>"
  Bus Selector5/6 -> PwrLimit/19(GcHDP_PackVolt_V), Bus Creator2/6  "<GcHDP_PackVolt_V>"
  Bus Creator2/1 -> Bus Selector1/1, Bus Selector2/1, Bus Selector3/1
  GcSOH_PackSOH_pct/1 -> PwrLimitFlg/4(GcSOH_PackSOH_pct)
  GeUDS_CapSel_enum/1 -> PwrLimitFlg/5(GeUDS_CapSel_enum)

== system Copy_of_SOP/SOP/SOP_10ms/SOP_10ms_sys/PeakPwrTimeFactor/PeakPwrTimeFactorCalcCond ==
  GeCTC_CtrCtlState_enum : Inport
  Constant1 : Constant  Value=Enum_CTCCtrCtlState.Enum_CTCCtrCtlState_Emergency
  Data Type Conversion1 : DataTypeConversion
  Relational Operator1 : RelationalOperator  Operator=~=  OutDataTypeStr=boolean
  LbSOP_SOPEnbl_flg : Outport
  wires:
  GeCTC_CtrCtlState_enum/1 -> Data Type Conversion1/1
  Constant1/1 -> Relational Operator1/2
  Relational Operator1/1 -> LbSOP_SOPEnbl_flg/1  "LbSOP_SOPEnbl_flg"
  Data Type Conversion1/1 -> Relational Operator1/1

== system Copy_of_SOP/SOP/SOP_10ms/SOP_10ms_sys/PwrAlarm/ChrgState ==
  LbSOP_ChrgCurrFltFuncEn_flg : Inport
  GcHDP_PackCrnt_A : Inport  Port=2
  LcSOP_ChrgRqstCurr_A : Inport  Port=3
  Bus Creator : BusCreator  Inputs=2
  Bus Selector{,1..3} (4 alike) : BusSelector  OutputSignals=LcSOP_ChrgRqstCurr_A,GcHDP_PackCrnt_A
  ChrgState : Stateflow chart  TreatAsAtomicUnit=on
  ChrgStateFltLevel1 : Subsystem  TreatAsAtomicUnit=on
  ChrgStateFltLevel2 : Subsystem  TreatAsAtomicUnit=on
  ChrgStateFltLevel3 : Subsystem  TreatAsAtomicUnit=on
  ChrgStateNormal : Subsystem  TreatAsAtomicUnit=on
  Constant1 : Constant  Value=Enum_SOPChrgPwrState.Enum_SOPChrgPwrState_FltLevel1
  Constant2 : Constant  Value=Enum_SOPChrgPwrState.Enum_SOPChrgPwrState_FltLevel2
  Constant3 : Constant  Value=Enum_SOPChrgPwrState.Enum_SOPChrgPwrState_FltLevel3
  Constant4 : Constant  Value=Enum_SOPChrgPwrState.Enum_SOPChrgPwrState_Normal
  Constant5 : Constant  Value=Enum_SOPChrgPwrState.Enum_SOPChrgPwrState_FltLevel3
  Constant6 : Constant  Value=Enum_SOPChrgPwrState.Enum_SOPChrgPwrState_FltLevel2
  Constant7 : Constant  Value=Enum_SOPChrgPwrState.Enum_SOPChrgPwrState_FltLevel1
  Data Type Conversion1 : DataTypeConversion
  Data Type Conversion4 : DataTypeConversion
  OverWrite : AIWAYS_Powertrain_BMS_lib/Signals/OverWrite  OverWrite_Value=CeSOP_ChrgPwrStateOvr_enum  OverWrite_flag=CbSOP_ChrgPwrStateOvrSwt_flg
  Relational Operator{,1..3,5..7} (7 alike) : RelationalOperator  Operator===  OutDataTypeStr=boolean
  SOP_GbSOP_ChrgPwrFltLevel1_flg : AIWAYS_Powertrain_BMS_lib/Signals/OverWrite  OverWrite_Value=CbSOP_ChrgPwrFltLevel1Ovr_flg  OverWrite_flag=CbSOP_ChrgPwrFltLevel1OvrSwt_flg
  SOP_GbSOP_ChrgPwrFltLevel2_flg : AIWAYS_Powertrain_BMS_lib/Signals/OverWrite  OverWrite_Value=CbSOP_ChrgPwrFltLevel2Ovr_flg  OverWrite_flag=CbSOP_ChrgPwrFltLevel2OvrSwt_flg
  SOP_GbSOP_ChrgPwrFltLevel3_flg : AIWAYS_Powertrain_BMS_lib/Signals/OverWrite  OverWrite_Value=CbSOP_ChrgPwrFltLevel3Ovr_flg  OverWrite_flag=CbSOP_ChrgPwrFltLevel3OvrSwt_flg
  Unit Delay : UnitDelay  SampleTime=-1  StateName=StateName
  GeSOP_ChrgPwrState_enum : Outport
  GbSOP_ChrgPwrFltLevel3_flg : Outport  Port=2
  GbSOP_ChrgPwrFltLevel2_flg : Outport  Port=3
  GbSOP_ChrgPwrFltLevel1_flg : Outport  Port=4
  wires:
  OverWrite/1 -> GeSOP_ChrgPwrState_enum/1  "GeSOP_ChrgPwrState_enum"
  LcSOP_ChrgRqstCurr_A/1 -> Bus Creator/2  "LcSOP_ChrgRqstCurr_A"
  ChrgStateNormal/1(LbSOP_ChrgPwrNormal2Level1_flg) -> ChrgState/2(LbSOP_ChrgPwrNormal2Level1_flg)
  ChrgStateFltLevel1/1(LbSOP_ChrgPwrLevel12Level2_flg) -> ChrgState/3(LbSOP_ChrgPwrLevel12Level2_flg)
  ChrgStateFltLevel1/2(LbSOP_ChrgPwrLevel12Normal_flg) -> ChrgState/4(LbSOP_ChrgPwrLevel12Normal_flg)
  ChrgStateFltLevel2/1(LbSOP_ChrgPwrLevel22Level3_flg) -> ChrgState/5(LbSOP_ChrgPwrLevel22Level3_flg)
  ChrgStateFltLevel2/2(LbSOP_ChrgPwrLevel22Level1_flg) -> ChrgState/6(LbSOP_ChrgPwrLevel22Level1_flg)
  ChrgStateFltLevel3/1(LbSOP_ChrgPwrLevel32Level2_flg) -> ChrgState/7(LbSOP_ChrgPwrLevel32Level2_flg)
  Unit Delay/1 -> Data Type Conversion4/1
  Constant4/1 -> Relational Operator/2
  Relational Operator/1 -> ChrgStateNormal/Enable
  Bus Selector/2 -> ChrgStateNormal/2(GcHDP_PackCrnt_A)  "<GcHDP_PackCrnt_A>"
  Bus Selector/1 -> ChrgStateNormal/1(LcSOP_ChrgRqstCurr_A)  "<LcSOP_ChrgRqstCurr_A>"
  Bus Creator/1 -> Bus Selector/1, Bus Selector2/1, Bus Selector3/1, Bus Selector1/1
  GcHDP_PackCrnt_A/1 -> Bus Creator/1  "GcHDP_PackCrnt_A"
  Bus Selector1/1 -> ChrgStateFltLevel1/1(LcSOP_ChrgRqstCurr_A)  "<LcSOP_ChrgRqstCurr_A>"
  Bus Selector1/2 -> ChrgStateFltLevel1/2(GcHDP_PackCrnt_A)  "<GcHDP_PackCrnt_A>"
  Bus Selector2/1 -> ChrgStateFltLevel2/1(LcSOP_ChrgRqstCurr_A)  "<LcSOP_ChrgRqstCurr_A>"
  Bus Selector2/2 -> ChrgStateFltLevel2/2(GcHDP_PackCrnt_A)  "<GcHDP_PackCrnt_A>"
  Bus Selector3/2 -> ChrgStateFltLevel3/2(GcHDP_PackCrnt_A)  "<GcHDP_PackCrnt_A>"
  Bus Selector3/1 -> ChrgStateFltLevel3/1(LcSOP_ChrgRqstCurr_A)  "<LcSOP_ChrgRqstCurr_A>"
  Constant1/1 -> Relational Operator1/2
  Relational Operator1/1 -> ChrgStateFltLevel1/Enable
  Constant2/1 -> Relational Operator2/2
  Relational Operator2/1 -> ChrgStateFltLevel2/Enable
  Constant3/1 -> Relational Operator3/2
  Relational Operator3/1 -> ChrgStateFltLevel3/Enable
  LbSOP_ChrgCurrFltFuncEn_flg/1 -> ChrgState/1(LbSOP_ChrgCurrFltFuncEn_flg)  "LbSOP_ChrgCurrFltFuncEn_flg"
  Data Type Conversion4/1 -> Relational Operator/1, Relational Operator2/1, Relational Operator3/1, Relational Operator1/1
  Constant5/1 -> Relational Operator5/2
  Constant7/1 -> Relational Operator7/2
  Constant6/1 -> Relational Operator6/2
  Relational Operator7/1 -> SOP_GbSOP_ChrgPwrFltLevel1_flg/1
  Relational Operator6/1 -> SOP_GbSOP_ChrgPwrFltLevel2_flg/1
  ChrgState/1(GeSOP_ChrgPwrState_enum) -> Unit Delay/1, Data Type Conversion1/1, OverWrite/1
  Data Type Conversion1/1 -> Relational Operator6/1, Relational Operator7/1, Relational Operator5/1
  Relational Operator5/1 -> SOP_GbSOP_ChrgPwrFltLevel3_flg/1
  SOP_GbSOP_ChrgPwrFltLevel1_flg/1 -> GbSOP_ChrgPwrFltLevel1_flg/1  "GbSOP_ChrgPwrFltLevel1_flg"
  SOP_GbSOP_ChrgPwrFltLevel2_flg/1 -> GbSOP_ChrgPwrFltLevel2_flg/1  "GbSOP_ChrgPwrFltLevel2_flg"
  SOP_GbSOP_ChrgPwrFltLevel3_flg/1 -> GbSOP_ChrgPwrFltLevel3_flg/1  "GbSOP_ChrgPwrFltLevel3_flg"
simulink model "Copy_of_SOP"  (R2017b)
settings: Solver=FixedStepDiscrete  StartTime=0.0  StopTime=10.0  FixedStep=0.01  RelTol=1e-3  EnableMultiTasking=on
undefined symbols (not defined in the file): ASWTYPE_FALSE, ASWTYPE_TRUE, CcSOP_CellVoltLowLevel1Time_MS, CcSOP_CellVoltRngDiff_V, CcSOP_CellVoltRngDiffHeal_V, CcSOP_CellVoltRngHighTime_MS, CcSOP_CellVoltRngLowTime_MS, CcSOP_CellVoltRngUpLimit_V, CcSOP_ChrgCurrFltChrgCurrThrld_A, CcSOP_ChrgCurrFltLevel1Factor_numb, CcSOP_ChrgCurrFltLevel1Time_ms, CcSOP_ChrgCurrFltLevel2Factor_numb, CcSOP_ChrgCurrFltLevel2Time_ms, CcSOP_ChrgCurrFltLevel3Factor_numb, CcSOP_ChrgCurrFltLevel3Time_ms, CcSOP_ChrgFloorPwrLimit_kW, CcSOP_ChrgFltHysCurr_A, CcSOP_ChrgHighFactor_numb, CcSOP_ChrgLowFactor_numb, CcSOP_ChrgPwrFltPeakPwrThrld_kW, CcSOP_DisChrgEmerPwrLimit_kW, CcSOP_DisChrgFloorPwrLimit_kW, CcSOP_DisChrgHighFactor_numb, CcSOP_DisChrgLowFactor_numb, CcSOP_DischrgPwrFltLevel1Factor_numb, CcSOP_DischrgPwrFltLevel1Time_ms, CcSOP_DischrgPwrFltLevel2Factor_numb, CcSOP_DischrgPwrFltLevel2Time_ms, CcSOP_DischrgPwrFltLevel3Factor_numb, CcSOP_DischrgPwrFltLevel3Time_ms, CcSOP_DischrgPwrFltPeakPwrThrld_kW, CcSOP_DischrgPwrFltThrld_kW, CcSOP_DisChrgPwrLimit_kW, CcSOP_FeedbackPwrFltLevel1Factor_numb, CcSOP_FeedbackPwrFltLevel1Time_ms, CcSOP_FeedbackPwrFltLevel2Factor_numb, CcSOP_FeedbackPwrFltLevel2Time_ms, CcSOP_FeedbackPwrFltLevel3Factor_numb, CcSOP_FeedbackPwrFltLevel3Time_ms, CcSOP_FeedbackPwrFltThrld_kW, CcSOP_FltLimitPwrFactorLevel1_numb, CcSOP_FltLimitPwrFactorLevel2_numb, CcSOP_LookupTablePwrFactor_pct, CcSOP_MaxChrgCurrLimitFactorLevel2_numb, CcSOP_MaxCurrTableLarger_ms, CcSOP_MaxCurrTableSmaller_ms, CcSOP_PeakPowerRunTime_ms, CcSOP_PwrDownDisDetLevel1Speed_kW, CcSOP_PwrDownDisFloorFactor_numb, CcSOP_PwrDownDisFloorSpeed_kW, CcSOP_PwrDownSpeed_kW, CcSOP_PwrFltHysFactor_numb, CcSOP_PwrFltThrldTestMode_kW, CcSOP_PwrUpSpeed_kW, Enum_CTCCtrCtlConnMode, Enum_CTCCtrCtlState, Enum_MSMBMUState, Enum_SOPChrgPwrState, Enum_SOPDisChrgPwrState, Enum_SOPFeedbackPwrState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
libraries: AIWAYS_Powertrain_BMS_lib x77
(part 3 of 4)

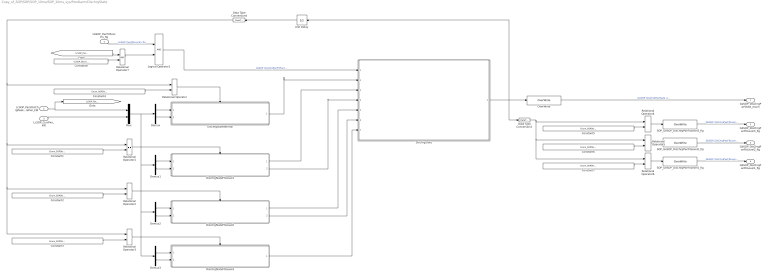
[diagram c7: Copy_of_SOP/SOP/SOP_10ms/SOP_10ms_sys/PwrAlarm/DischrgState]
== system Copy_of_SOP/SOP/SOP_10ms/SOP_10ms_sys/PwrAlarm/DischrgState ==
  LbSOP_PwrFltFuncEn_flg : Inport
  LcSOP_PackDisChrgPeakTablePwr_kW : Inport  Port=2
  LcSOP_CurrPwr_kW : Inport  Port=3
  Constant1 : Constant  Value=Enum_SOPDisChrgPwrState.Enum_SOPDisChrgPwrState_FltLevel1
  Constant2 : Constant  Value=Enum_SOPDisChrgPwrState.Enum_SOPDisChrgPwrState_FltLevel2
  Constant3 : Constant  Value=Enum_SOPDisChrgPwrState.Enum_SOPDisChrgPwrState_FltLevel3
  Constant4 : Constant  Value=Enum_SOPDisChrgPwrState.Enum_SOPDisChrgPwrState_Normal
  Constant5 : Constant  Value=Enum_SOPDisChrgPwrState.Enum_SOPDisChrgPwrState_FltLevel3
  Constant6 : Constant  Value=Enum_SOPDisChrgPwrState.Enum_SOPDisChrgPwrState_FltLevel2
  Constant7 : Constant  Value=Enum_SOPDisChrgPwrState.Enum_SOPDisChrgPwrState_FltLevel1
  Constant8 : Constant  Value=CcSOP_DischrgPwrFltPeakPwrThrld_kW
  Data Type Conversion1 : DataTypeConversion
  Data Type Conversion4 : DataTypeConversion
  Demux{,1..3} (4 alike) : Demux  Outputs=2
  DischrgState : Stateflow chart  TreatAsAtomicUnit=on
  DischrgStateFltLevel1 : Subsystem  TreatAsAtomicUnit=on
  DischrgStateFltLevel2 : Subsystem  TreatAsAtomicUnit=on
  DischrgStateFltLevel3 : Subsystem  TreatAsAtomicUnit=on
  DischrgStateNormal : Subsystem  TreatAsAtomicUnit=on
  Logical Operator1 : Logic  AllPortsSameDT=off  OutDataTypeStr=boolean
  Mux : Mux  Inputs=2
  OverWrite : AIWAYS_Powertrain_BMS_lib/Signals/OverWrite  OverWrite_Value=CeSOP_DisChrgPwrStateOvr_enum  OverWrite_flag=CbSOP_DisChrgPwrStateOvrSwt_flg
  Relational Operator{,1..6} (7 alike) : RelationalOperator  Operator===  OutDataTypeStr=boolean
  Relational Operator7 : RelationalOperator  OutDataTypeStr=boolean
  SOP_GeSOP_DisChrgPwrFltLevel1_flg : AIWAYS_Powertrain_BMS_lib/Signals/OverWrite  OverWrite_Value=CbSOP_DisChrgPwrFltLevel1Ovr_flg  OverWrite_flag=CbSOP_DisChrgPwrFltLevel1OvrSwt_flg
  SOP_GeSOP_DisChrgPwrFltLevel2_flg : AIWAYS_Powertrain_BMS_lib/Signals/OverWrite  OverWrite_Value=CbSOP_DisChrgPwrFltLevel2Ovr_flg  OverWrite_flag=CbSOP_DisChrgPwrFltLevel2OvrSwt_flg
  SOP_GeSOP_DisChrgPwrFltLevel3_flg : AIWAYS_Powertrain_BMS_lib/Signals/OverWrite  OverWrite_Value=CbSOP_DisChrgPwrFltLevel3Ovr_flg  OverWrite_flag=CbSOP_DisChrgPwrFltLevel3OvrSwt_flg
  Unit Delay : UnitDelay  SampleTime=-1  StateName=StateName
  GeSOP_DisChrgPwrState_enum : Outport
  GbSOP_DisChrgPwrFltLevel3_flg : Outport  Port=2
  GbSOP_DisChrgPwrFltLevel2_flg : Outport  Port=3
  GbSOP_DisChrgPwrFltLevel1_flg : Outport  Port=4
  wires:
  OverWrite/1 -> GeSOP_DisChrgPwrState_enum/1  "GeSOP_DisChrgPwrState_enum"
  Relational Operator3/1 -> DischrgStateFltLevel3/Enable
  Constant3/1 -> Relational Operator3/2
  Relational Operator2/1 -> DischrgStateFltLevel2/Enable
  Constant2/1 -> Relational Operator2/2
  Relational Operator1/1 -> DischrgStateFltLevel1/Enable
  Constant1/1 -> Relational Operator1/2
  Demux3/1 -> DischrgStateFltLevel3/1(LcSOP_PackDisChrgPeakTablePwr_kW)
  Demux3/2 -> DischrgStateFltLevel3/2(LcSOP_CurrPwr_kW)
  Demux2/2 -> DischrgStateFltLevel2/2(LcSOP_CurrPwr_kW)
  Demux2/1 -> DischrgStateFltLevel2/1(LcSOP_PackDisChrgPeakTablePwr_kW)
  Demux1/2 -> DischrgStateFltLevel1/2(LcSOP_CurrPwr_kW)
  Demux1/1 -> DischrgStateFltLevel1/1(LcSOP_PackDisChrgPeakTablePwr_kW)
  LcSOP_CurrPwr_kW/1 -> Mux/2
  LcSOP_PackDisChrgPeakTablePwr_kW/1 -> Mux/1, [LcSOP_PackDisChrgPeakTablePwr_kW]
  Mux/1 -> Demux/1, Demux1/1, Demux2/1, Demux3/1
  Demux/1 -> DischrgStateNormal/1(LcSOP_PackDisChrgPeakTablePwr_kW)
  Demux/2 -> DischrgStateNormal/2(LcSOP_CurrPwr_kW)
  Relational Operator/1 -> DischrgStateNormal/Enable
  Constant4/1 -> Relational Operator/2
  Unit Delay/1 -> Data Type Conversion4/1
  DischrgState/1(GeSOP_DisChrgPwrState_enum) -> Data Type Conversion1/1, Unit Delay/1, OverWrite/1
  DischrgStateFltLevel3/1(LbSOP_DischrgPwrLevel32Level2_flg) -> DischrgState/7(LbSOP_DischrgPwrLevel32Level2_flg)
  DischrgStateFltLevel2/2(LbSOP_DischrgPwrLevel22Level1_flg) -> DischrgState/6(LbSOP_DischrgPwrLevel22Level1_flg)
  DischrgStateFltLevel2/1(LbSOP_DischrgPwrLevel22Level3_flg) -> DischrgState/5(LbSOP_DischrgPwrLevel22Level3_flg)
  DischrgStateFltLevel1/2(LbSOP_DischrgPwrLevel12Normal_flg) -> DischrgState/4(LbSOP_DischrgPwrLevel12Normal_flg)
  DischrgStateFltLevel1/1(LbSOP_DischrgPwrLevel12Level2_flg) -> DischrgState/3(LbSOP_DischrgPwrLevel12Level2_flg)
  DischrgStateNormal/1(LbSOP_DischrgPwrNormal2Level1_flg) -> DischrgState/2(LbSOP_DischrgPwrNormal2Level1_flg)
  Constant8/1 -> Relational Operator7/2
  [LcSOP_PackDisChrgPeakTablePwr_kW] -> Relational Operator7/1
  LbSOP_PwrFltFuncEn_flg/1 -> Logical Operator1/1  "LbSOP_PwrFltFuncEn_flg"
  Relational Operator7/1 -> Logical Operator1/2
  Logical Operator1/1 -> DischrgState/1(LbSOP_DischrgPwrFltFuncEn_flg)  "LbSOP_DischrgPwrFltFuncEn_flg"
  Data Type Conversion4/1 -> Relational Operator1/1, Relational Operator3/1, Relational Operator2/1, Relational Operator/1
  Constant5/1 -> Relational Operator4/2
  Data Type Conversion1/1 -> Relational Operator5/1, Relational Operator6/1, Relational Operator4/1
  Relational Operator4/1 -> SOP_GeSOP_DisChrgPwrFltLevel3_flg/1
  Constant6/1 -> Relational Operator5/2
  Relational Operator5/1 -> SOP_GeSOP_DisChrgPwrFltLevel2_flg/1
  Constant7/1 -> Relational Operator6/2
  Relational Operator6/1 -> SOP_GeSOP_DisChrgPwrFltLevel1_flg/1
  SOP_GeSOP_DisChrgPwrFltLevel3_flg/1 -> GbSOP_DisChrgPwrFltLevel3_flg/1  "GbSOP_DisChrgPwrFltLevel3_flg"
  SOP_GeSOP_DisChrgPwrFltLevel2_flg/1 -> GbSOP_DisChrgPwrFltLevel2_flg/1  "GbSOP_DisChrgPwrFltLevel2_flg"
  SOP_GeSOP_DisChrgPwrFltLevel1_flg/1 -> GbSOP_DisChrgPwrFltLevel1_flg/1  "GbSOP_DisChrgPwrFltLevel1_flg"

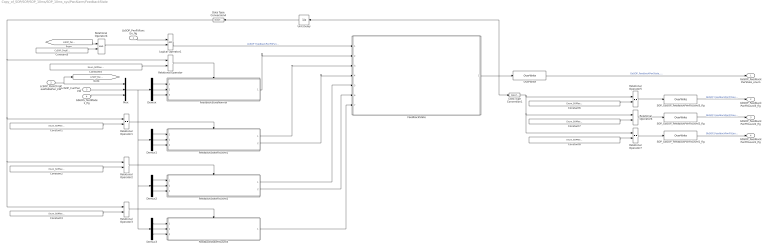
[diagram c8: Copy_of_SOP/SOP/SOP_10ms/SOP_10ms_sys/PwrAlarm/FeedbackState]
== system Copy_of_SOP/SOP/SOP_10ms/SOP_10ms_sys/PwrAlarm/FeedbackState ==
  LbSOP_PwrFltFuncEn_flg : Inport
  LcSOP_PackChrgPeakTablePwr_kW : Inport  Port=2
  LcSOP_CurrPwr_kW : Inport  Port=3
  GbUDS_TestMode1_flg : Inport  Port=4
  Constant1 : Constant  Value=Enum_SOPFeedbackPwrState.Enum_SOPFeedbackPwrState_FltLevel1
  Constant2 : Constant  Value=Enum_SOPFeedbackPwrState.Enum_SOPFeedbackPwrState_FltLevel2
  Constant3 : Constant  Value=Enum_SOPFeedbackPwrState.Enum_SOPFeedbackPwrState_FltLevel3
  Constant4 : Constant  Value=Enum_SOPFeedbackPwrState.Enum_SOPFeedbackPwrState_Normal
  Constant5 : Constant  Value=CcSOP_ChrgPwrFltPeakPwrThrld_kW
  Constant6 : Constant  Value=Enum_SOPFeedbackPwrState.Enum_SOPFeedbackPwrState_FltLevel3
  Constant7 : Constant  Value=Enum_SOPFeedbackPwrState.Enum_SOPFeedbackPwrState_FltLevel2
  Constant8 : Constant  Value=Enum_SOPFeedbackPwrState.Enum_SOPFeedbackPwrState_FltLevel1
  Data Type Conversion1 : DataTypeConversion
  Data Type Conversion4 : DataTypeConversion
  Demux{,1..3} (4 alike) : Demux  Outputs=3
  FeedbackState : Stateflow chart  TreatAsAtomicUnit=on
  FeedbackStateFltLevel1 : Subsystem  TreatAsAtomicUnit=on
  FeedbackStateFltLevel2 : Subsystem  TreatAsAtomicUnit=on
  FeedbackStateFltLevel3 : Subsystem  TreatAsAtomicUnit=on
  FeedbackStateNormal : Subsystem  TreatAsAtomicUnit=on
  Logical Operator1 : Logic  AllPortsSameDT=off  OutDataTypeStr=boolean
  Mux : Mux  Inputs=3
  OverWrite : AIWAYS_Powertrain_BMS_lib/Signals/OverWrite  OverWrite_Value=CeSOP_FeedbackPwrStateOvr_enum  OverWrite_flag=CbSOP_FeedbackPwrStateOvrSwt_flg
  Relational Operator{,1..3,5..7} (7 alike) : RelationalOperator  Operator===  OutDataTypeStr=boolean
  Relational Operator4 : RelationalOperator  OutDataTypeStr=boolean
  SOP_GbSOP_FeedbackPwrFltLevel1_flg : AIWAYS_Powertrain_BMS_lib/Signals/OverWrite  OverWrite_Value=CbSOP_FeedbackPwrFltLevel1Ovr_flg  OverWrite_flag=CbSOP_FeedbackPwrFltLevel1OvrSwt_flg
  SOP_GbSOP_FeedbackPwrFltLevel2_flg : AIWAYS_Powertrain_BMS_lib/Signals/OverWrite  OverWrite_Value=CbSOP_FeedbackPwrFltLevel2Ovr_flg  OverWrite_flag=CbSOP_FeedbackPwrFltLevel2OvrSwt_flg
  SOP_GbSOP_FeedbackPwrFltLevel3_flg : AIWAYS_Powertrain_BMS_lib/Signals/OverWrite  OverWrite_Value=CbSOP_FeedbackPwrFltLevel3Ovr_flg  OverWrite_flag=CbSOP_FeedbackPwrFltLevel3OvrSwt_flg
  Unit Delay : UnitDelay  SampleTime=-1  StateName=StateName
  GeSOP_FeedbackPwrState_enum : Outport
  GbSOP_FeedbackPwrFltLevel3_flg : Outport  Port=2
  GbSOP_FeedbackPwrFltLevel2_flg : Outport  Port=3
  GbSOP_FeedbackPwrFltLevel1_flg : Outport  Port=4
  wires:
  OverWrite/1 -> GeSOP_FeedbackPwrState_enum/1  "GeSOP_FeedbackPwrState_enum"
  FeedbackStateNormal/1(LbSOP_FeedbackPwrNormal2Level1_flg) -> FeedbackState/2(LbSOP_FeedbackPwrNormal2Level1_flg)
  FeedbackStateFltLevel1/1(LbSOP_FeedbackPwrLevel12Level2_flg) -> FeedbackState/3(LbSOP_FeedbackPwrLevel12Level2_flg)
  FeedbackStateFltLevel1/2(LbSOP_FeedbackPwrLevel12Normal_flg) -> FeedbackState/4(LbSOP_FeedbackPwrLevel12Normal_flg)
  FeedbackStateFltLevel2/1(LbSOP_FeedbackPwrLevel22Level3_flg) -> FeedbackState/5(LbSOP_FeedbackPwrLevel22Level3_flg)
  FeedbackStateFltLevel2/2(LbSOP_FeedbackPwrLevel22Level1_flg) -> FeedbackState/6(LbSOP_FeedbackPwrLevel22Level1_flg)
  FeedbackStateFltLevel3/1(LbSOP_FeedbackPwrLevel32Level2_flg) -> FeedbackState/7(LbSOP_FeedbackPwrLevel32Level2_flg)
  Unit Delay/1 -> Data Type Conversion4/1
  Constant4/1 -> Relational Operator/2
  Relational Operator/1 -> FeedbackStateNormal/Enable
  Demux/2 -> FeedbackStateNormal/2(LcSOP_CurrPwr_kW)
  Demux/1 -> FeedbackStateNormal/1(LcSOP_PackChrgPeakTablePwr_kW)
  Mux/1 -> Demux3/1, Demux2/1, Demux1/1, Demux/1
  LcSOP_PackChrgPeakTablePwr_kW/1 -> [LcSOP_PackChrgPeakTablePwr_kW], Mux/1
  LcSOP_CurrPwr_kW/1 -> Mux/2
  Demux1/1 -> FeedbackStateFltLevel1/1(LcSOP_PackChrgPeakTablePwr_kW)
  Demux1/2 -> FeedbackStateFltLevel1/2(LcSOP_CurrPwr_kW)
  Demux2/1 -> FeedbackStateFltLevel2/1(LcSOP_PackChrgPeakTablePwr_kW)
  Demux2/2 -> FeedbackStateFltLevel2/2(LcSOP_CurrPwr_kW)
  Demux3/2 -> FeedbackStateFltLevel3/2(LcSOP_CurrPwr_kW)
  Demux3/1 -> FeedbackStateFltLevel3/1(LcSOP_PackChrgPeakTablePwr_kW)
  Constant1/1 -> Relational Operator1/2
  Relational Operator1/1 -> FeedbackStateFltLevel1/Enable
  Constant2/1 -> Relational Operator2/2
  Relational Operator2/1 -> FeedbackStateFltLevel2/Enable
  Constant3/1 -> Relational Operator3/2
  Relational Operator3/1 -> FeedbackStateFltLevel3/Enable
  Constant5/1 -> Relational Operator4/2
  [LcSOP_PackChrgPeakTablePwr_kW] -> Relational Operator4/1
  Relational Operator4/1 -> Logical Operator1/2
  LbSOP_PwrFltFuncEn_flg/1 -> Logical Operator1/1
  Logical Operator1/1 -> FeedbackState/1(LbSOP_FeedbackPwrFltFuncEn_flg)  "LbSOP_FeedbackPwrFltFuncEn_flg"
  Data Type Conversion4/1 -> Relational Operator/1, Relational Operator2/1, Relational Operator3/1, Relational Operator1/1
  Constant7/1 -> Relational Operator6/2
  Data Type Conversion1/1 -> Relational Operator6/1, Relational Operator7/1, Relational Operator5/1
  Relational Operator6/1 -> SOP_GbSOP_FeedbackPwrFltLevel2_flg/1
  Constant6/1 -> Relational Operator5/2
  Constant8/1 -> Relational Operator7/2
  Relational Operator5/1 -> SOP_GbSOP_FeedbackPwrFltLevel3_flg/1
  Relational Operator7/1 -> SOP_GbSOP_FeedbackPwrFltLevel1_flg/1
  FeedbackState/1(GeSOP_FeedbackPwrState_enum) -> Data Type Conversion1/1, OverWrite/1, Unit Delay/1
  SOP_GbSOP_FeedbackPwrFltLevel3_flg/1 -> GbSOP_FeedbackPwrFltLevel3_flg/1  "GbSOP_FeedbackPwrFltLevel3_flg"
  SOP_GbSOP_FeedbackPwrFltLevel2_flg/1 -> GbSOP_FeedbackPwrFltLevel2_flg/1  "GbSOP_FeedbackPwrFltLevel2_flg"
  SOP_GbSOP_FeedbackPwrFltLevel1_flg/1 -> GbSOP_FeedbackPwrFltLevel1_flg/1  "GbSOP_FeedbackPwrFltLevel1_flg"
  GbUDS_TestMode1_flg/1 -> Mux/3
  Demux/3 -> FeedbackStateNormal/3(GbUDS_TestMode1_flg)
  Demux1/3 -> FeedbackStateFltLevel1/3(GbUDS_TestMode1_flg)
  Demux2/3 -> FeedbackStateFltLevel2/3(GbUDS_TestMode1_flg)
  Demux3/3 -> FeedbackStateFltLevel3/3(GbUDS_TestMode1_flg)

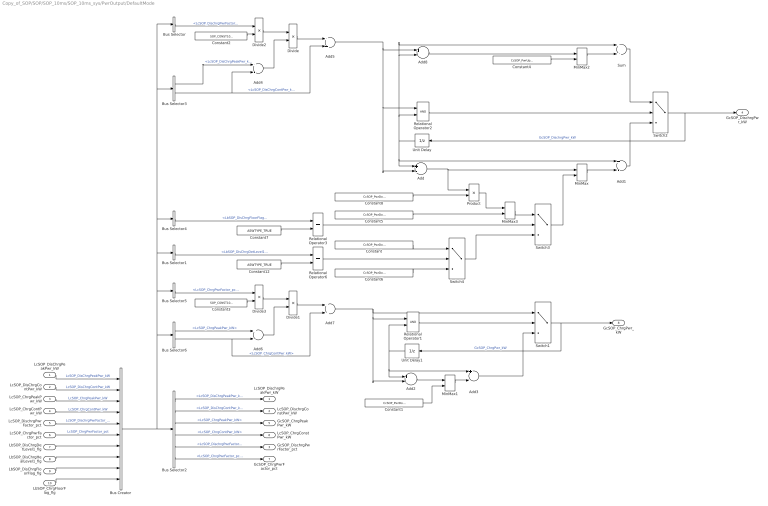
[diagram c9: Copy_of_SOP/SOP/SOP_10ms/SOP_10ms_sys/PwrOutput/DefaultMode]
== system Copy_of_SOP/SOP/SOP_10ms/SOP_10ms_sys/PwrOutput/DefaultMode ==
  LcSOP_DisChrgPeakPwr_kW : Inport
  LcSOP_DisChrgContPwr_kW : Inport  Port=2
  LcSOP_ChrgPeakPwr_kW : Inport  Port=3
  LcSOP_ChrgContPwr_kW : Inport  Port=4
  LcSOP_DischrgPwrFactor_pct : Inport  Port=5
  LcSOP_ChrgPwrFactor_pct : Inport  Port=6
  LbSOP_DisChrgDetLevel1_flg : Inport  Port=7
  LbSOP_DisChrgHealLevel1_flg : Inport  Port=8
  LbSOP_DisChrgFloorFlag_flg : Inport  Port=9
  LbSOP_ChrgFloorFlag_flg : Inport  Port=10
  Add{,1..4,6,8} (7 alike) : Sum  Inputs=+-
  Add5 : Sum
  Add7 : Sum
  Bus Creator : BusCreator  Inputs=10
  Bus Selector : BusSelector  OutputSignals=LcSOP_DischrgPwrFactor_pct
  Bus Selector1 : BusSelector  OutputSignals=LbSOP_DisChrgDetLevel1_flg
  Bus Selector2 : BusSelector  OutputSignals=LcSOP_DisChrgPeakPwr_kW,LcSOP_DisChrgContPwr_kW,LcSOP_ChrgPeakPwr_kW,LcSOP_ChrgContPwr_kW,LcSOP_DischrgPwrFactor_pct,LcSOP_ChrgPwrFactor_pct
  Bus Selector3 : BusSelector  OutputSignals=LcSOP_DisChrgPeakPwr_kW,LcSOP_DisChrgContPwr_kW
  Bus Selector4 : BusSelector  OutputSignals=LbSOP_DisChrgFloorFlag_flg
  Bus Selector5 : BusSelector  OutputSignals=LcSOP_ChrgPwrFactor_pct
  Bus Selector6 : BusSelector  OutputSignals=LcSOP_ChrgPeakPwr_kW,LcSOP_ChrgContPwr_kW
  Constant : Constant  Value=CcSOP_PwrDownDisDetLevel1Speed_kW
  Constant1 : Constant  Value=CcSOP_PwrDownSpeed_kW
  Constant12 : Constant  Value=ASWTYPE_TRUE
  Constant2 : Constant  Value=SOP_CONST100_NUMB
  Constant3 : Constant  Value=SOP_CONST100_NUMB
  Constant4 : Constant  Value=CcSOP_PwrUpSpeed_kW
  Constant5 : Constant  Value=CcSOP_PwrDownDisFloorSpeed_kW
  Constant6 : Constant  Value=CcSOP_PwrDownSpeed_kW
  Constant7 : Constant  Value=ASWTYPE_TRUE
  Constant8 : Constant  Value=CcSOP_PwrDownDisFloorFactor_numb
  Divide : Product  Inputs=**
  Divide1 : Product  Inputs=**
  Divide2 : Product  Inputs=*/  OutDataTypeStr=single
  Divide3 : Product  Inputs=*/  OutDataTypeStr=single
  MinMax{,1..3} (4 alike) : MinMax  Inputs=2
  Product : Product  OutDataTypeStr=Inherit: Inherit via back propagation
  Relational Operator1 : RelationalOperator  OutDataTypeStr=boolean
  Relational Operator2 : RelationalOperator  OutDataTypeStr=boolean
  Relational Operator3 : RelationalOperator  Operator===  OutDataTypeStr=boolean
  Relational Operator6 : RelationalOperator  Operator===  OutDataTypeStr=boolean
  Sum : Sum  OutDataTypeStr=Inherit: Inherit via back propagation  RndMeth=Zero
  Switch{1..4} (4 alike) : Switch  Criteria=u2 ~= 0
  Unit Delay : UnitDelay  SampleTime=-1  StateName=StateName
  Unit Delay1 : UnitDelay  SampleTime=-1  StateName=StateName
  LcSOP_DischrgPeakPwr_kW : Outport
  LcSOP_DischrgConstPwr_kW : Outport  Port=2
  GcSOP_DischrgPwrFactor_pct : Outport  Port=3
  GcSOP_DischrgPwr_kW : Outport  Port=4
  GcSOP_ChrgPeakPwr_kW : Outport  Port=5
  LcSOP_ChrgConstPwr_kW : Outport  Port=6
  GcSOP_ChrgPwrFactor_pct : Outport  Port=7
  GcSOP_ChrgPwr_kW : Outport  Port=8
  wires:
  Divide1/1 -> Add7/1
  Add6/1 -> Divide1/2
  Divide3/1 -> Divide1/1
  Bus Selector6/1 -> Add6/1  "<LcSOP_ChrgPeakPwr_kW>"
  Bus Selector6/2 -> Add7/2, Add6/2  "<LcSOP_ChrgContPwr_kW>"
  Bus Selector5/1 -> Divide3/1  "<LcSOP_ChrgPwrFactor_pct>"
  Constant3/1 -> Divide3/2
  Bus Creator/1 -> Bus Selector3/1, Bus Selector/1, Bus Selector4/1, Bus Selector1/1, Bus Selector5/1, Bus Selector6/1, Bus Selector2/1
  Add7/1 -> Add2/2, Relational Operator1/1, Switch1/1
  Add2/1 -> MinMax1/1
  Constant1/1 -> MinMax1/2
  Switch1/1 -> GcSOP_ChrgPwr_kW/1, Unit Delay1/1  "GcSOP_ChrgPwr_kW"
  Unit Delay1/1 -> Relational Operator1/2, Add2/1, Add3/1
  Relational Operator1/1 -> Switch1/2
  MinMax1/1 -> Add3/2
  Add3/1 -> Switch1/3
  Divide/1 -> Add5/1
  Add4/1 -> Divide/2
  Divide2/1 -> Divide/1
  Bus Selector3/1 -> Add4/1  "<LcSOP_DisChrgPeakPwr_kW>"
  Bus Selector3/2 -> Add5/2, Add4/2  "<LcSOP_DisChrgContPwr_kW>"
  Bus Selector/1 -> Divide2/1  "<LcSOP_DischrgPwrFactor_pct>"
  Constant2/1 -> Divide2/2
  LcSOP_DisChrgPeakPwr_kW/1 -> Bus Creator/1  "LcSOP_DisChrgPeakPwr_kW"
  LcSOP_DisChrgContPwr_kW/1 -> Bus Creator/2  "LcSOP_DisChrgContPwr_kW"
  LcSOP_ChrgPeakPwr_kW/1 -> Bus Creator/3  "LcSOP_ChrgPeakPwr_kW"
  LcSOP_ChrgContPwr_kW/1 -> Bus Creator/4  "LcSOP_ChrgContPwr_kW"
  LcSOP_DischrgPwrFactor_pct/1 -> Bus Creator/5  "LcSOP_DischrgPwrFactor_pct"
  LcSOP_ChrgPwrFactor_pct/1 -> Bus Creator/6  "LcSOP_ChrgPwrFactor_pct"
  Bus Selector2/1 -> LcSOP_DischrgPeakPwr_kW/1  "<LcSOP_DisChrgPeakPwr_kW>"
  Bus Selector2/2 -> LcSOP_DischrgConstPwr_kW/1  "<LcSOP_DisChrgContPwr_kW>"
  Bus Selector2/3 -> GcSOP_ChrgPeakPwr_kW/1  "<LcSOP_ChrgPeakPwr_kW>"
  Bus Selector2/4 -> LcSOP_ChrgConstPwr_kW/1  "<LcSOP_ChrgContPwr_kW>"
  Bus Selector2/5 -> GcSOP_DischrgPwrFactor_pct/1  "<LcSOP_DischrgPwrFactor_pct>"
  Bus Selector2/6 -> GcSOP_ChrgPwrFactor_pct/1  "<LcSOP_ChrgPwrFactor_pct>"
  Add/1 -> Product/1, MinMax/1
  Switch2/1 -> Unit Delay/1, GcSOP_DischrgPwr_kW/1  "GcSOP_DischrgPwr_kW"
  Relational Operator2/1 -> Switch2/2
  MinMax/1 -> Add1/2
  Add1/1 -> Switch2/3
  Add5/1 -> Relational Operator2/1, Add/2, Add8/1
  MinMax2/1 -> Sum/2
  Add8/1 -> MinMax2/1
  Sum/1 -> Switch2/1
  Constant4/1 -> MinMax2/2
  LbSOP_DisChrgDetLevel1_flg/1 -> Bus Creator/7
  LbSOP_DisChrgHealLevel1_flg/1 -> Bus Creator/8
  LbSOP_DisChrgFloorFlag_flg/1 -> Bus Creator/9
  LbSOP_ChrgFloorFlag_flg/1 -> Bus Creator/10
  Bus Selector4/1 -> Relational Operator3/1  "<LbSOP_DisChrgFloorFlag_flg>"
  Constant5/1 -> MinMax3/2
  Switch4/1 -> Switch3/3
  Bus Selector1/1 -> Relational Operator6/1  "<LbSOP_DisChrgDetLevel1_flg>"
  Constant/1 -> Switch4/1
  Constant6/1 -> Switch4/3
  Switch3/1 -> MinMax/2
  Constant12/1 -> Relational Operator6/2
  Constant7/1 -> Relational Operator3/2
  Relational Operator6/1 -> Switch4/2
  Relational Operator3/1 -> Switch3/2
  Unit Delay/1 -> Add1/1, Add/1, Relational Operator2/2, Add8/2, Sum/1
  MinMax3/1 -> Switch3/1
  Product/1 -> MinMax3/1
  Constant8/1 -> Product/2

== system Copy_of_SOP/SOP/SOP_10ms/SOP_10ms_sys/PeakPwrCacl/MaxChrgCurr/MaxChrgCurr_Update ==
  LcSOP_OrigMaxChrgTableCurr_A : Inport
  Bus Creator : BusCreator  Inputs=2
  Bus Selector : BusSelector  OutputSignals=LcSOP_OrigMaxChrgTableCurr_A,LcSOP_OldMaxChrgTableCurr_A
  Bus Selector1 : BusSelector  OutputSignals=LcSOP_OrigMaxChrgTableCurr_A,LcSOP_OldMaxChrgTableCurr_A
  Constant1 : Constant  Value=SOP_RUNTIME_MS
  Constant2 : Constant  Value=CcSOP_MaxCurrTableLarger_ms
  Constant3 : Constant  Value=SOP_RUNTIME_MS
  Constant4 : Constant  Value=CcSOP_MaxCurrTableSmaller_ms
  Delay : AIWAYS_Powertrain_BMS_lib/Debounce & Delay/BMSDelay
  Delay1 : AIWAYS_Powertrain_BMS_lib/Debounce & Delay/BMSDelay
  Logical Operator : Logic  Operator=OR  AllPortsSameDT=off  OutDataTypeStr=boolean
  Relational Operator1 : RelationalOperator  Operator=>  OutDataTypeStr=boolean
  Relational Operator2 : RelationalOperator  Operator=<  OutDataTypeStr=boolean
  Switch : Switch  Criteria=u2 ~= 0
  Unit Delay External IC : AIWAYS_Powertrain_BMS_lib/Delay Blocks/Unit Delay External IC
  LcSOP_MaxChrgTableCurr_A : Outport
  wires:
  Relational Operator1/1 -> Delay/1
  Constant1/1 -> Delay/2
  Constant2/1 -> Delay/3
  LcSOP_OrigMaxChrgTableCurr_A/1 -> Unit Delay External IC/2, Switch/1, Bus Creator/1
  Unit Delay External IC/1 -> Switch/3, Bus Creator/2  "LcSOP_OldMaxChrgTableCurr_A"
  Bus Creator/1 -> Bus Selector1/1, Bus Selector/1
  Bus Selector/1 -> Relational Operator1/1  "<LcSOP_OrigMaxChrgTableCurr_A>"
  Bus Selector/2 -> Relational Operator1/2  "<LcSOP_OldMaxChrgTableCurr_A>"
  Bus Selector1/1 -> Relational Operator2/1  "<LcSOP_OrigMaxChrgTableCurr_A>"
  Bus Selector1/2 -> Relational Operator2/2  "<LcSOP_OldMaxChrgTableCurr_A>"
  Relational Operator2/1 -> Delay1/1
  Constant3/1 -> Delay1/2
  Constant4/1 -> Delay1/3
  Delay/1 -> Logical Operator/1
  Delay1/1 -> Logical Operator/2
  Logical Operator/1 -> Switch/2  "LbSOP_MaxChrgTableCurrUpdate_flg"
  Switch/1 -> Unit Delay External IC/1, LcSOP_MaxChrgTableCurr_A/1

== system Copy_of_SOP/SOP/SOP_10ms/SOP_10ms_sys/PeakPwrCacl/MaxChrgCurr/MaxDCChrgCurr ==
  GcCDP_MaxCellTemp_C : Inport
  GcCDP_MinCellTemp_C : Inport  Port=2
  GcCDP_MaxCellVolt_mV : Inport  Port=3
  GcCDP_MinCellVolt_mV : Inport  Port=4
  GeUDS_CapSel_enum : Inport  Port=5
  3D_Config_Word{,1..3} (4 alike) : AIWAYS_Powertrain_BMS_lib/Signals/3D_Config_Word  Default_Cal_Breakpoint1_Name=CaSOP_MaxDCChrgCurrTempTable_C  Default_Cal_Breakpoint2_Name=CaSOP_MaxDCChrgCurrCellVoltTable_V  Default_Cal_Table1_Name=CaSOP_MaxDCChrgCurrTable_A  CATL153Ah_Cal_Breakpoint1_Name=CaSOP_MaxDCChrgCurrTempTableC153_C  CATL153Ah_Cal_Breakpoint2_Name=CaSOP_MaxDCChrgCurrCellVoltTableC153_V  CATL153Ah_Cal_Table1_Name=CaSOP_MaxDCChrgCurrTableC153_A  CATL180Ah_Cal_Breakpoint1_Name=CaSOP_MaxDCChrgCurrTempTableC180_C  CATL180Ah_Cal_Breakpoint2_Name=CaSOP_MaxDCChrgCurrCellVoltTableC180_V  CATL180Ah_Cal_Table1_Name=CaSOP_MaxDCChrgCurrTableC180_A  CATL177Ah_Cal_Breakpoint1_Name=CaSOP_MaxDCChrgCurrTempTableC177_C  CATL177Ah_Cal_Breakpoint2_Name=CaSOP_MaxDCChrgCurrCellVoltTableC177_V  CATL177Ah_Cal_Table1_Name=CaSOP_MaxDCChrgCurrTableC177_A  CATL203Ah_Cal_Breakpoint1_Name=CaSOP_MaxDCChrgCurrTempTableC203_C  CATL203Ah_Cal_Breakpoint2_Name=CaSOP_MaxDCChrgCurrCellVoltTableC203_V  CATL203Ah_Cal_Table1_Name=CaSOP_MaxDCChrgCurrTableC203_A  CATL51Ah_Cal_Breakpoint1_Name=CaSOP_MaxDCChrgCurrTempTableC51_C  CATL51Ah_Cal_Breakpoint2_Name=CaSOP_MaxDCChrgCurrCellVoltTableC51_V  CATL51Ah_Cal_Table1_Name=CaSOP_MaxDCChrgCurrTableC51_A  CATL132Ah_Cal_Breakpoint1_Name=CaSOP_MaxDCChrgCurrTempTableC132_C  CATL132Ah_Cal_Breakpoint2_Name=CaSOP_MaxDCChrgCurrCellVoltTableC132_V  CATL132Ah_Cal_Table1_Name=CaSOP_MaxDCChrgCurrTableC132_A  XWD75Ah_Cal_Breakpoint1_Name=CaSOP_MaxDCChrgCurrTempTableX75_C  XWD75Ah_Cal_Breakpoint2_Name=CaSOP_MaxDCChrgCurrCellVoltTableX75_V  XWD75Ah_Cal_Table1_Name=CaSOP_MaxDCChrgCurrTableX75_A  TFE177Ah_Cal_Breakpoint1_Name=CaSOP_MaxDCChrgCurrTempTableT177_C  TFE177Ah_Cal_Breakpoint2_Name=CaSOP_MaxDCChrgCurrCellVoltTableT177_V  TFE177Ah_Cal_Table1_Name=CaSOP_MaxDCChrgCurrTableT177_A  CATLCTP248Ah_Cal_Breakpoint1_Name=CaSOP_MaxDCChrgCurrTempTableC248_C  CATLCTP248Ah_Cal_Breakpoint2_Name=CaSOP_MaxDCChrgCurrCellVoltTableC248_V  CATLCTP248Ah_Cal_Table1_Name=CaSOP_MaxDCChrgCurrTableC248_A
  Bus Creator : BusCreator  Inputs=5
  Bus Selector : BusSelector  OutputSignals=GeUDS_CapSel_enum,GcCDP_MaxCellTemp_C,GcCDP_MaxCellVolt_V
  Bus Selector1 : BusSelector  OutputSignals=GeUDS_CapSel_enum,GcCDP_MaxCellTemp_C,GcCDP_MinCellVolt_V
  Bus Selector2 : BusSelector  OutputSignals=GeUDS_CapSel_enum,GcCDP_MinCellTemp_C,GcCDP_MaxCellVolt_V
  Bus Selector3 : BusSelector  OutputSignals=GeUDS_CapSel_enum,GcCDP_MinCellTemp_C,GcCDP_MinCellVolt_V
  Constant1 : Constant  Value=SOP_CONST1000_NUMB
  Constant2 : Constant  Value=SOP_CONST1000_NUMB
  Data Type Conversion : DataTypeConversion  OutDataTypeStr=fixdt(0,16,0.01,0)  RndMeth=Round
  Data Type Conversion1 : DataTypeConversion  OutDataTypeStr=fixdt(0,16,0.01,0)  RndMeth=Round
  Divide1 : Product  Inputs=*/  OutDataTypeStr=single
  Divide2 : Product  Inputs=*/  OutDataTypeStr=single
  MinMax : MinMax  Inputs=4
  LcSOP_OrigMaxChrgTableCurr_A : Outport
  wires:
  MinMax/1 -> LcSOP_OrigMaxChrgTableCurr_A/1  "LcSOP_OrigMaxChrgTableCurr_A"
  GcCDP_MaxCellTemp_C/1 -> Bus Creator/2
  GcCDP_MinCellTemp_C/1 -> Bus Creator/3
  Bus Creator/1 -> Bus Selector1/1, Bus Selector3/1, Bus Selector2/1, Bus Selector/1
  Constant1/1 -> Divide2/2
  GcCDP_MinCellVolt_mV/1 -> Divide2/1
  Divide2/1 -> Data Type Conversion1/1
  Constant2/1 -> Divide1/2
  GcCDP_MaxCellVolt_mV/1 -> Divide1/1
  Divide1/1 -> Data Type Conversion/1
  Data Type Conversion/1 -> Bus Creator/4  "GcCDP_MaxCellVolt_V"
  Data Type Conversion1/1 -> Bus Creator/5  "GcCDP_MinCellVolt_V"
  GeUDS_CapSel_enum/1 -> Bus Creator/1  "GeUDS_CapSel_enum"
  Bus Selector/1 -> 3D_Config_Word/1  "<GeUDS_CapSel_enum>"
  Bus Selector/2 -> 3D_Config_Word/2  "<GcCDP_MaxCellTemp_C>"
  Bus Selector/3 -> 3D_Config_Word/3  "<GcCDP_MaxCellVolt_V>"
  Bus Selector1/1 -> 3D_Config_Word1/1  "<GeUDS_CapSel_enum>"
  Bus Selector1/2 -> 3D_Config_Word1/2  "<GcCDP_MaxCellTemp_C>"
  Bus Selector1/3 -> 3D_Config_Word1/3  "<GcCDP_MinCellVolt_V>"
  Bus Selector2/1 -> 3D_Config_Word2/1  "<GeUDS_CapSel_enum>"
  Bus Selector2/2 -> 3D_Config_Word2/2  "<GcCDP_MinCellTemp_C>"
  Bus Selector2/3 -> 3D_Config_Word2/3  "<GcCDP_MaxCellVolt_V>"
  Bus Selector3/2 -> 3D_Config_Word3/2  "<GcCDP_MinCellTemp_C>"
  Bus Selector3/3 -> 3D_Config_Word3/3  "<GcCDP_MinCellVolt_V>"
  Bus Selector3/1 -> 3D_Config_Word3/1  "<GeUDS_CapSel_enum>"
  3D_Config_Word/1 -> MinMax/1
  3D_Config_Word1/1 -> MinMax/2
  3D_Config_Word2/1 -> MinMax/3
  3D_Config_Word3/1 -> MinMax/4

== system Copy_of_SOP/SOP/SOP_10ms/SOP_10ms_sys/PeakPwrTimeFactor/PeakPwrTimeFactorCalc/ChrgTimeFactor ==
  LcSOP_ChrgPeakPwr_kW : Inport
  LcSOP_ChrgContPwr_kW : Inport  Port=2
  GcHDP_PackCrnt_A : Inport  Port=3
  GcHDP_PackVolt_V : Inport  Port=4
  Add : Sum  AccumDataTypeStr=single  OutDataTypeStr=single
  Add1 : Sum  Inputs=+-  AccumDataTypeStr=single  OutDataTypeStr=single
  Add2 : Sum  Inputs=+-  AccumDataTypeStr=single  OutDataTypeStr=single
  Add3 : Sum  Inputs=+-  OutDataTypeStr=single
  Bus Creator : BusCreator  Inputs=2
  Bus Selector : BusSelector  OutputSignals=LcSOP_CurrPwr_kW,LcSOP_ChrgContPwr_kW
  Bus Selector1 : BusSelector  OutputSignals=LcSOP_CurrPwr_kW,LcSOP_ChrgContPwr_kW
  Bus Selector2 : BusSelector  OutputSignals=LcSOP_ChrgContPwr_kW
  Constant : Constant  Value=CcSOP_ChrgHighFactor_numb
  Constant1 : Constant  Value=CcSOP_ChrgLowFactor_numb
  Constant10 : Constant  Value=SOP_CONST0_NUMB
  Constant11 : Constant  Value=SOP_CONST100_NUMB
  Constant2 : Constant  Value=SOP_RUNTIME_MS
  Constant3 : Constant  Value=CcSOP_PeakPowerRunTime_ms
  Constant4 : Constant  Value=SOP_CONST0_NUMB
  Constant5 : Constant  Value=SOP_CONST100_NUMB
  Constant6 : Constant  Value=SOP_CONST100_NUMB
  Constant7 : Constant  Value=SOP_CONST1000_NUMB
  Constant8 : Constant  Value=SOP_CONSTF1_NUMB
  Constant9 : Constant  Value=SOP_CONSTF1_NUMB
  Data Type Conversion : DataTypeConversion
  Data Type Conversion1 : DataTypeConversion
  Data Type Conversion2 : DataTypeConversion
  Divide{,1..2,4} (4 alike) : Product  Inputs=**  OutDataTypeStr=single
  Divide5 : Product  Inputs=**  OutDataTypeStr=Inherit: Inherit via back propagation
  Divide6 : Product  Inputs=*/  OutDataTypeStr=single
  Limiter : AIWAYS_Powertrain_BMS_lib/Nonlinear Blocks/Limiter
  Limiter1 : AIWAYS_Powertrain_BMS_lib/Nonlinear Blocks/Limiter
  Product : Product  OutDataTypeStr=Inherit: Inherit via back propagation
  Product1 : Product  OutDataTypeStr=Inherit: Inherit via back propagation
  Protected Division : AIWAYS_Powertrain_BMS_lib/Arithmetic Operators/Protected Division
  Relational Operator : RelationalOperator  OutDataTypeStr=boolean
  Switch : Switch  Criteria=u2 ~= 0
  Unit Delay : UnitDelay  SampleTime=-1  StateName=StateName
  LcSOP_ChrgPwrFactor_pct : Outport
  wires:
  Constant7/1 -> Divide6/2
  Divide6/1 -> Bus Creator/1  "LcSOP_CurrPwr_kW"
  Divide/1 -> Divide6/1
  Add3/1 -> LcSOP_ChrgPwrFactor_pct/1
  Constant6/1 -> Add3/1
  Constant5/1 -> Divide5/2
  Protected Division/1 -> Divide5/1
  LcSOP_ChrgPeakPwr_kW/1 -> Product1/1
  Bus Selector2/1 -> Add2/2  "<LcSOP_ChrgContPwr_kW>"
  Add2/1 -> Divide2/1
  Add1/1 -> Divide1/1
  Bus Selector1/1 -> Add1/1  "<LcSOP_CurrPwr_kW>"
  Bus Selector1/2 -> Add1/2  "<LcSOP_ChrgContPwr_kW>"
  Bus Creator/1 -> Bus Selector1/1, Bus Selector/1, Bus Selector2/1
  Bus Selector/2 -> Relational Operator/2  "<LcSOP_ChrgContPwr_kW>"
  Bus Selector/1 -> Relational Operator/1  "<LcSOP_CurrPwr_kW>"
  LcSOP_ChrgContPwr_kW/1 -> Product/1
  Divide4/1 -> Add/2
  Switch/1 -> Divide4/2
  Divide1/1 -> Divide4/1
  Limiter/1 -> Protected Division/1, Unit Delay/1
  Divide2/1 -> Limiter/2, Protected Division/2
  Add/1 -> Limiter/3
  Constant3/1 -> Divide2/2
  Constant2/1 -> Divide1/2
  Unit Delay/1 -> Add/1
  Constant1/1 -> Switch/3
  Constant/1 -> Switch/1
  Relational Operator/1 -> Switch/2
  GcHDP_PackVolt_V/1 -> Divide/2
  GcHDP_PackCrnt_A/1 -> Divide/1
  Product/1 -> Bus Creator/2  "LcSOP_ChrgContPwr_kW"
  Product1/1 -> Add2/1
  Constant4/1 -> Data Type Conversion/1
  Constant8/1 -> Product/2
  Constant9/1 -> Product1/2
  Data Type Conversion/1 -> Limiter/1
  Constant10/1 -> Data Type Conversion1/1
  Data Type Conversion2/1 -> Limiter1/1
  Data Type Conversion1/1 -> Limiter1/2
  Constant11/1 -> Data Type Conversion2/1
  Divide5/1 -> Limiter1/3
  Limiter1/1 -> Add3/2

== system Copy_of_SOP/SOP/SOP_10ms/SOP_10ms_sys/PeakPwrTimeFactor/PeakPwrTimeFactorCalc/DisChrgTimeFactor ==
  note: // 放电正；充电负
  LcSOP_DisChrgPeakPwr_kW : Inport
  LcSOP_DisChrgContPwr_kW : Inport  Port=2
  GcHDP_PackCrnt_A : Inport  Port=3
  GcHDP_PackVolt_V : Inport  Port=4
  Add : Sum  AccumDataTypeStr=single  OutDataTypeStr=single
  Add1 : Sum  Inputs=+-  AccumDataTypeStr=single  OutDataTypeStr=single
  Add2 : Sum  Inputs=+-  AccumDataTypeStr=single  OutDataTypeStr=single
  Add3 : Sum  Inputs=+-  OutDataTypeStr=single
  Bus Creator : BusCreator  Inputs=2
  Bus Selector : BusSelector  OutputSignals=LcSOP_CurrPwr_kW,LcSOP_DisChrgContPwr_kW
  Bus Selector1 : BusSelector  OutputSignals=LcSOP_CurrPwr_kW,LcSOP_DisChrgContPwr_kW
  Bus Selector2 : BusSelector  OutputSignals=LcSOP_DisChrgContPwr_kW
  Constant : Constant  Value=CcSOP_DisChrgHighFactor_numb
  Constant1 : Constant  Value=CcSOP_DisChrgLowFactor_numb
  Constant2 : Constant  Value=SOP_RUNTIME_MS
  Constant3 : Constant  Value=CcSOP_PeakPowerRunTime_ms
  Constant4 : Constant  Value=SOP_CONST0_NUMB
  Constant5 : Constant  Value=SOP_CONST100_NUMB
  Constant6 : Constant  Value=SOP_CONST100_NUMB
  Constant7 : Constant  Value=SOP_CONST1000_NUMB
  Constant8 : Constant  Value=SOP_CONST0_NUMB
  Constant9 : Constant  Value=SOP_CONST100_NUMB
  Data Type Conversion : DataTypeConversion
  Data Type Conversion1 : DataTypeConversion
  Data Type Conversion2 : DataTypeConversion
  Divide{,1..2,4} (4 alike) : Product  Inputs=**  OutDataTypeStr=single
  Divide5 : Product  Inputs=**  OutDataTypeStr=Inherit: Inherit via back propagation
  Divide6 : Product  Inputs=*/  OutDataTypeStr=single
  Limiter : AIWAYS_Powertrain_BMS_lib/Nonlinear Blocks/Limiter
  Limiter1 : AIWAYS_Powertrain_BMS_lib/Nonlinear Blocks/Limiter
  Protected Division : AIWAYS_Powertrain_BMS_lib/Arithmetic Operators/Protected Division
  Relational Operator : RelationalOperator  OutDataTypeStr=boolean
  Switch : Switch  Criteria=u2 ~= 0
  Unit Delay : UnitDelay  SampleTime=-1  StateName=StateName
  LcSOP_DischrgPwrFactor_pct : Outport
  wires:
  GcHDP_PackCrnt_A/1 -> Divide/1
  GcHDP_PackVolt_V/1 -> Divide/2
  Relational Operator/1 -> Switch/2
  Constant/1 -> Switch/1
  Constant1/1 -> Switch/3
  Unit Delay/1 -> Add/2
  Constant2/1 -> Divide1/2
  Constant3/1 -> Divide2/2
  Add/1 -> Limiter/3
  Divide2/1 -> Limiter/1, Protected Division/2
  Constant4/1 -> Data Type Conversion/1
  Limiter/1 -> Unit Delay/1, Protected Division/1
  Divide1/1 -> Divide4/1
  Switch/1 -> Divide4/2
  Divide4/1 -> Add/1
  LcSOP_DisChrgContPwr_kW/1 -> Bus Creator/2  "LcSOP_DisChrgContPwr_kW"
  Bus Selector/1 -> Relational Operator/1  "<LcSOP_CurrPwr_kW>"
  Bus Selector/2 -> Relational Operator/2  "<LcSOP_DisChrgContPwr_kW>"
  Bus Creator/1 -> Bus Selector2/1, Bus Selector1/1, Bus Selector/1
  Bus Selector1/2 -> Add1/2  "<LcSOP_DisChrgContPwr_kW>"
  Bus Selector1/1 -> Add1/1  "<LcSOP_CurrPwr_kW>"
  Add1/1 -> Divide1/1
  Add2/1 -> Divide2/1
  Bus Selector2/1 -> Add2/2  "<LcSOP_DisChrgContPwr_kW>"
  LcSOP_DisChrgPeakPwr_kW/1 -> Add2/1
  Protected Division/1 -> Divide5/1
  Constant5/1 -> Divide5/2
  Constant6/1 -> Add3/1
  Divide5/1 -> Limiter1/3
  Add3/1 -> LcSOP_DischrgPwrFactor_pct/1
  Divide/1 -> Divide6/1
  Divide6/1 -> Bus Creator/1  "LcSOP_CurrPwr_kW"
  Constant7/1 -> Divide6/2
  Data Type Conversion/1 -> Limiter/2
  Constant8/1 -> Data Type Conversion1/1
  Data Type Conversion1/1 -> Limiter1/2
  Constant9/1 -> Data Type Conversion2/1
  Data Type Conversion2/1 -> Limiter1/1
  Limiter1/1 -> Add3/2

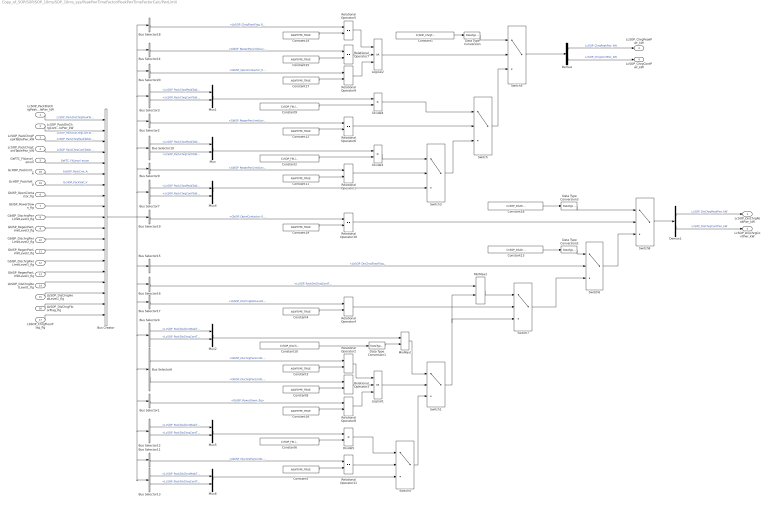
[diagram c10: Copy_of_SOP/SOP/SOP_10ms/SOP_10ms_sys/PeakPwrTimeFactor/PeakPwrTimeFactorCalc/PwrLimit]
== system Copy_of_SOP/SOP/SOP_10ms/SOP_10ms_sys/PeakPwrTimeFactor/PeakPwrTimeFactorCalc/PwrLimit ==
  LcSOP_PackDisChrgPeakTablePwr_kW : Inport
  LcSOP_PackDisChrgContTablePwr_kW : Inport  Port=2
  LcSOP_PackChrgPeakTablePwr_kW : Inport  Port=3
  LcSOP_PackChrgContTablePwr_kW : Inport  Port=4
  GeFTC_FltLevel_enum : Inport  Port=5
  GbISP_OpenContactor_flg : Inport  Port=6
  GbISP_PowerDown_flg : Inport  Port=7
  GbISP_DischrgPwrLimitLevel3_flg : Inport  Port=8
  GbISP_RegenPwrLimitLevel3_flg : Inport  Port=9
  GbISP_DischrgPwrLimitLevel2_flg : Inport  Port=10
  GbISP_RegenPwrLimitLevel2_flg : Inport  Port=11
  GbISP_DischrgPwrLimitLevel1_flg : Inport  Port=12
  GbISP_RegenPwrLimitLevel1_flg : Inport  Port=13
  LbSOP_DisChrgDetLevel1_flg : Inport  Port=14
  LbSOP_DisChrgHealLevel1_flg : Inport  Port=15
  LbSOP_DisChrgFloorFlag_flg : Inport  Port=16
  LbSOP_ChrgFloorFlag_flg : Inport  Port=17
  GcHDP_PackCrnt_A : Inport  Port=18
  GcHDP_PackVolt_V : Inport  Port=19
  Bus Creator : BusCreator  Inputs=19
  Bus Selector1 : BusSelector  OutputSignals=GbISP_PowerDown_flg
  Bus Selector10 : BusSelector  OutputSignals=LcSOP_PackChrgPeakTablePwr_kW,LcSOP_PackChrgContTablePwr_kW
  Bus Selector11 : BusSelector  OutputSignals=GbISP_DischrgPwrLimitLevel1_flg
  Bus Selector12 : BusSelector  OutputSignals=LcSOP_PackDisChrgPeakTablePwr_kW,LcSOP_PackDisChrgContTablePwr_kW
  Bus Selector13 : BusSelector  OutputSignals=LcSOP_PackDisChrgPeakTablePwr_kW,LcSOP_PackDisChrgContTablePwr_kW
  Bus Selector14 : BusSelector  OutputSignals=GbISP_RegenPwrLimitLevel3_flg
  Bus Selector15 : BusSelector  OutputSignals=LbSOP_DisChrgFloorFlag_flg
  Bus Selector16 : BusSelector  OutputSignals=LcSOP_PackDisChrgContTablePwr_kW
  Bus Selector17 : BusSelector  OutputSignals=LbSOP_DisChrgDetLevel1_flg
  Bus Selector18 : BusSelector  OutputSignals=LbSOP_ChrgFloorFlag_flg
  Bus Selector19 : BusSelector  OutputSignals=GbISP_OpenContactor_flg
  Bus Selector2 : BusSelector  OutputSignals=GbISP_RegenPwrLimitLevel2_flg
  Bus Selector20 : BusSelector  OutputSignals=GbISP_OpenContactor_flg
  Bus Selector3 : BusSelector  OutputSignals=LcSOP_PackChrgPeakTablePwr_kW,LcSOP_PackChrgContTablePwr_kW
  Bus Selector4 : BusSelector  OutputSignals=LcSOP_PackDisChrgPeakTablePwr_kW,LcSOP_PackDisChrgContTablePwr_kW
  Bus Selector6 : BusSelector  OutputSignals=GbISP_DischrgPwrLimitLevel3_flg,GbISP_DischrgPwrLimitLevel2_flg
  Bus Selector7 : BusSelector  OutputSignals=LcSOP_PackChrgPeakTablePwr_kW,LcSOP_PackChrgContTablePwr_kW
  Bus Selector9 : BusSelector  OutputSignals=GbISP_RegenPwrLimitLevel1_flg
  Constant1 : Constant  Value=CcSOP_ChrgFloorPwrLimit_kW
  Constant10 : Constant  Value=CcSOP_DisChrgPwrLimit_kW
  Constant{3..5,8,11..12,14..17,19} (11 alike) : Constant  Value=ASWTYPE_TRUE
  Constant13 : Constant  Value=CcSOP_DisChrgFloorPwrLimit_kW
  Constant18 : Constant  Value=CcSOP_DisChrgEmerPwrLimit_kW
  Constant2 : Constant  Value=CcSOP_FltLimitPwrFactorLevel1_numb
  Constant6 : Constant  Value=CcSOP_FltLimitPwrFactorLevel1_numb
  Constant9 : Constant  Value=CcSOP_FltLimitPwrFactorLevel2_numb
  Data Type Conversion{,1..3} (4 alike) : DataTypeConversion
  Demux : Demux  Outputs=2
  Demux1 : Demux  Outputs=2
  Divide3 : Product  Inputs=**
  Divide4 : Product  Inputs=**
  Divide5 : Product  Inputs=**
  Logical1 : Logic  Operator=OR  Inputs=3  OutDataTypeStr=boolean
  Logical2 : Logic  Operator=OR  Inputs=3  OutDataTypeStr=boolean
  MinMax1 : MinMax  Inputs=2  OutDataTypeStr=Inherit: Inherit via back propagation  RndMeth=Zero
  MinMax2 : MinMax  Inputs=2
  Mux{,1..2,4..6} (6 alike) : Mux  Inputs=2
  Relational Operator{1..11} (11 alike) : RelationalOperator  Operator===  OutDataTypeStr=boolean
  Switch{,1,3..8} (8 alike) : Switch  Criteria=u2 ~= 0
  LcSOP_DisChrgPeakPwr_kW : Outport
  LcSOP_DisChrgContPwr_kW : Outport  Port=2
  LcSOP_ChrgPeakPwr_kW : Outport  Port=3
  LcSOP_ChrgContPwr_kW : Outport  Port=4
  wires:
  Switch/1 -> Switch5/3
  LcSOP_PackDisChrgPeakTablePwr_kW/1 -> Bus Creator/1  "LcSOP_PackDisChrgPeakTablePwr_kW"
  LcSOP_PackChrgContTablePwr_kW/1 -> Bus Creator/4  "LcSOP_PackChrgContTablePwr_kW"
  LcSOP_PackDisChrgContTablePwr_kW/1 -> Bus Creator/2  "LcSOP_PackDisChrgContTablePwr_kW"
  LcSOP_PackChrgPeakTablePwr_kW/1 -> Bus Creator/3  "LcSOP_PackChrgPeakTablePwr_kW"
  Mux/1 -> Divide3/1
  Bus Selector10/2 -> Mux/2  "<LcSOP_PackChrgContTablePwr_kW>"
  Bus Selector10/1 -> Mux/1  "<LcSOP_PackChrgPeakTablePwr_kW>"
  Demux/1 -> LcSOP_ChrgPeakPwr_kW/1  "LcSOP_ChrgPeakPwr_kW"
  Demux/2 -> LcSOP_ChrgContPwr_kW/1  "LcSOP_ChrgContPwr_kW"
  Bus Selector3/1 -> Mux1/1  "<LcSOP_PackChrgPeakTablePwr_kW>"
  Bus Selector3/2 -> Mux1/2  "<LcSOP_PackChrgContTablePwr_kW>"
  Constant8/1 -> Relational Operator3/2
  Bus Selector6/2 -> Relational Operator3/1  "<GbISP_DischrgPwrLimitLevel2_flg>"
  Demux1/1 -> LcSOP_DisChrgPeakPwr_kW/1  "LcSOP_DisChrgPeakPwr_kW"
  Demux1/2 -> LcSOP_DisChrgContPwr_kW/1  "LcSOP_DisChrgContPwr_kW"
  Mux1/1 -> Divide4/1
  Divide4/1 -> Switch/1
  Constant9/1 -> Divide4/2
  Logical1/1 -> Switch1/2
  Switch4/1 -> Switch1/3
  GeFTC_FltLevel_enum/1 -> Bus Creator/5  "GeFTC_FltLevel_enum"
  GcHDP_PackCrnt_A/1 -> Bus Creator/6  "GcHDP_PackCrnt_A"
  GcHDP_PackVolt_V/1 -> Bus Creator/7  "GcHDP_PackVolt_V"
  Bus Selector2/1 -> Relational Operator6/1  "<GbISP_RegenPwrLimitLevel2_flg>"
  Bus Creator/1 -> Bus Selector13/1, Bus Selector11/1, Bus Selector12/1, Bus Selector1/1, Bus Selector6/1, Bus Selector4/1, Bus Selector17/1, Bus Selector16/1, Bus Selector15/1, Bus Selector19/1, Bus Selector3/1, Bus Selector20/1, Bus Selector14/1, Bus Selector18/1, Bus Selector2/1, Bus Selector10/1, Bus Selector9/1, Bus Selector7/1
  Bus Selector7/2 -> Mux4/2  "<LcSOP_PackChrgContTablePwr_kW>"
  Mux4/1 -> Switch3/3
  Bus Selector7/1 -> Mux4/1  "<LcSOP_PackChrgPeakTablePwr_kW>"
  Switch3/1 -> Switch/3
  Constant2/1 -> Divide3/2
  Divide3/1 -> Switch3/1
  Bus Selector9/1 -> Relational Operator1/1  "<GbISP_RegenPwrLimitLevel1_flg>"
  Bus Selector11/1 -> Relational Operator11/1  "<GbISP_DischrgPwrLimitLevel1_flg>"
  Constant6/1 -> Divide5/2
  Divide5/1 -> Switch4/1
  Bus Selector12/2 -> Mux5/2  "<LcSOP_PackDisChrgContTablePwr_kW>"
  Bus Selector12/1 -> Mux5/1  "<LcSOP_PackDisChrgPeakTablePwr_kW>"
  Mux5/1 -> Divide5/1
  Bus Selector13/1 -> Mux6/1  "<LcSOP_PackDisChrgPeakTablePwr_kW>"
  Bus Selector13/2 -> Mux6/2  "<LcSOP_PackDisChrgContTablePwr_kW>"
  Mux6/1 -> Switch4/3
  Constant11/1 -> Relational Operator1/2
  Relational Operator1/1 -> Switch3/2
  Constant12/1 -> Relational Operator6/2
  Relational Operator6/1 -> Switch/2
  GbISP_OpenContactor_flg/1 -> Bus Creator/8
  GbISP_PowerDown_flg/1 -> Bus Creator/9
  GbISP_DischrgPwrLimitLevel3_flg/1 -> Bus Creator/10
  GbISP_RegenPwrLimitLevel3_flg/1 -> Bus Creator/11
  GbISP_DischrgPwrLimitLevel2_flg/1 -> Bus Creator/12
  GbISP_RegenPwrLimitLevel2_flg/1 -> Bus Creator/13
  GbISP_DischrgPwrLimitLevel1_flg/1 -> Bus Creator/14
  GbISP_RegenPwrLimitLevel1_flg/1 -> Bus Creator/15
  Constant1/1 -> Data Type Conversion/1
  Data Type Conversion/1 -> Switch5/1
  Switch5/1 -> Demux/1
  Constant3/1 -> Relational Operator2/2
  Bus Selector6/1 -> Relational Operator2/1  "<GbISP_DischrgPwrLimitLevel3_flg>"
  Relational Operator2/1 -> Logical1/1
  Relational Operator3/1 -> Logical1/2
  Constant10/1 -> Data Type Conversion1/1
  MinMax1/1 -> Switch1/1
  Bus Selector4/2 -> Mux2/2  "<LcSOP_PackDisChrgContTablePwr_kW>"
  Bus Selector4/1 -> Mux2/1  "<LcSOP_PackDisChrgPeakTablePwr_kW>"
  Data Type Conversion1/1 -> MinMax1/2
  Mux2/1 -> MinMax1/1
  LbSOP_ChrgFloorFlag_flg/1 -> Bus Creator/19
  LbSOP_DisChrgFloorFlag_flg/1 -> Bus Creator/18
  LbSOP_DisChrgHealLevel1_flg/1 -> Bus Creator/17
  LbSOP_DisChrgDetLevel1_flg/1 -> Bus Creator/16
  Bus Selector15/1 -> Switch6/2  "<LbSOP_DisChrgFloorFlag_flg>"
  Bus Selector16/1 -> MinMax2/1  "<LcSOP_PackDisChrgContTablePwr_kW>"
  Switch1/1 -> Switch7/3, MinMax2/2
  Constant13/1 -> Data Type Conversion2/1
  Data Type Conversion2/1 -> Switch6/1
  Switch7/1 -> Switch6/3
  MinMax2/1 -> Switch7/1
  Switch8/1 -> Demux1/1
  Constant14/1 -> Relational Operator5/2
  Bus Selector18/1 -> Relational Operator5/1  "<LbSOP_ChrgFloorFlag_flg>"
  Constant15/1 -> Relational Operator7/2
  Bus Selector14/1 -> Relational Operator7/1  "<GbISP_RegenPwrLimitLevel3_flg>"
  Relational Operator7/1 -> Logical2/2
  Relational Operator5/1 -> Logical2/1
  Logical2/1 -> Switch5/2
  Constant16/1 -> Relational Operator8/2
  Bus Selector1/1 -> Relational Operator8/1  "<GbISP_PowerDown_flg>"
  Relational Operator8/1 -> Logical1/3
  Bus Selector20/1 -> Relational Operator9/1  "<GbISP_OpenContactor_flg>"
  Constant17/1 -> Relational Operator9/2
  Relational Operator9/1 -> Logical2/3
  Constant18/1 -> Data Type Conversion3/1
  Data Type Conversion3/1 -> Switch8/1
  Switch6/1 -> Switch8/3
  Bus Selector19/1 -> Relational Operator10/1  "<GbISP_OpenContactor_flg>"
  Constant19/1 -> Relational Operator10/2
  Relational Operator10/1 -> Switch8/2
  Constant4/1 -> Relational Operator4/2
  Bus Selector17/1 -> Relational Operator4/1  "<LbSOP_DisChrgDetLevel1_flg>"
  Relational Operator4/1 -> Switch7/2
  Constant5/1 -> Relational Operator11/2
  Relational Operator11/1 -> Switch4/2

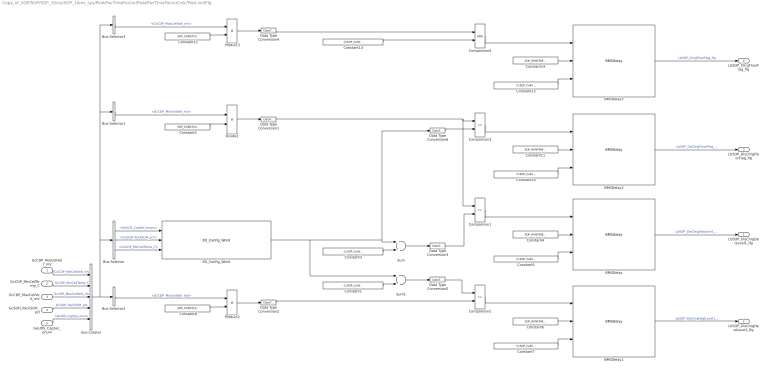
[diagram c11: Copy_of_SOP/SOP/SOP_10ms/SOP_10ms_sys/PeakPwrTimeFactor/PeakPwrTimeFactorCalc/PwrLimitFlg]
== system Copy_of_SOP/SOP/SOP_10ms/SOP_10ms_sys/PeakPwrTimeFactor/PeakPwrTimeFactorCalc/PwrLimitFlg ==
  GcCDP_MinCellVolt_mV : Inport
  GcCDP_MinCellTemp_C : Inport  Port=2
  GcCDP_MaxCellVolt_mV : Inport  Port=3
  GcSOH_PackSOH_pct : Inport  Port=4
  GeUDS_CapSel_enum : Inport  Port=5
  3D_Config_Word : AIWAYS_Powertrain_BMS_lib/Signals/3D_Config_Word  Default_Cal_Breakpoint1_Name=CaSOP_DisChrgCellSohTable_pct  Default_Cal_Breakpoint2_Name=CaSOP_DisChrgCellTempTable_C  Default_Cal_Table1_Name=CaSOP_DisChrgCellVoltTable_V  CATL153Ah_Cal_Breakpoint1_Name=CaSOP_DisChrgCellSohTableC153_pct  CATL153Ah_Cal_Breakpoint2_Name=CaSOP_DisChrgCellTempTableC153_C  CATL153Ah_Cal_Table1_Name=CaSOP_DisChrgCellVoltTableC153_V  CATL180Ah_Cal_Breakpoint1_Name=CaSOP_DisChrgCellSohTableC180_pct  CATL180Ah_Cal_Breakpoint2_Name=CaSOP_DisChrgCellTempTableC180_C  CATL180Ah_Cal_Table1_Name=CaSOP_DisChrgCellVoltTableC180_V  CATL177Ah_Cal_Breakpoint1_Name=CaSOP_DisChrgCellSohTableC177_pct  CATL177Ah_Cal_Breakpoint2_Name=CaSOP_DisChrgCellTempTableC177_C  CATL177Ah_Cal_Table1_Name=CaSOP_DisChrgCellVoltTableC177_V  CATL203Ah_Cal_Breakpoint1_Name=CaSOP_DisChrgCellSohTableC203_pct  CATL203Ah_Cal_Breakpoint2_Name=CaSOP_DisChrgCellTempTableC203_C  CATL203Ah_Cal_Table1_Name=CaSOP_DisChrgCellVoltTableC203_V  CATL51Ah_Cal_Breakpoint1_Name=CaSOP_DisChrgCellSohTableC51_pct  CATL51Ah_Cal_Breakpoint2_Name=CaSOP_DisChrgCellTempTableC51_C  CATL51Ah_Cal_Table1_Name=CaSOP_DisChrgCellVoltTableC51_V  CATL132Ah_Cal_Breakpoint1_Name=CaSOP_DisChrgCellSohTableC132_pct  CATL132Ah_Cal_Breakpoint2_Name=CaSOP_DisChrgCellTempTableC132_C  CATL132Ah_Cal_Table1_Name=CaSOP_DisChrgCellVoltTableC132_V  XWD75Ah_Cal_Breakpoint1_Name=CaSOP_DisChrgCellSohTableX75_pct  XWD75Ah_Cal_Breakpoint2_Name=CaSOP_DisChrgCellTempTableX75_C  XWD75Ah_Cal_Table1_Name=CaSOP_DisChrgCellVoltTableX75_V  TFE177Ah_Cal_Breakpoint1_Name=CaSOP_DisChrgCellSohTableT177_pct  TFE177Ah_Cal_Breakpoint2_Name=CaSOP_DisChrgCellTempTableT177_C  TFE177Ah_Cal_Table1_Name=CaSOP_DisChrgCellVoltTableT177_V  CATLCTP248Ah_Cal_Breakpoint1_Name=CaSOP_DisChrgCellSohTableC248_pct  CATLCTP248Ah_Cal_Breakpoint2_Name=CaSOP_DisChrgCellTempTableC248_C  CATLCTP248Ah_Cal_Table1_Name=CaSOP_DisChrgCellVoltTableC248_V
      link override Switch Case Action Subsystem4/2-D_Lookup_Table: BreakpointsForDimension1=CaSOP_DisChrgCellSohTableC203_pct  BreakpointsForDimension2=CaSOP_DisChrgCellTempTableC203_C  Table=CaSOP_DisChrgCellVoltTableC203_V
  BMSDelay{,1..3} (4 alike) : AIWAYS_Powertrain_BMS_lib/Debounce & Delay/BMSDelay
  Bus Creator : BusCreator  Inputs=5
  Bus Selector : BusSelector  OutputSignals=GeUDS_CapSel_enum,GcSOH_PackSOH_pct,GcCDP_MinCellTemp_C
  Bus Selector1 : BusSelector  OutputSignals=GcCDP_MinCellVolt_mV
  Bus Selector2 : BusSelector  OutputSignals=GcCDP_MinCellVolt_mV
  Bus Selector3 : BusSelector  OutputSignals=GcCDP_MaxCellVolt_mV
  Comparison1 : RelationalOperator  Operator=<=  OutDataTypeStr=boolean
  Comparison2 : RelationalOperator  Operator=<=  OutDataTypeStr=boolean
  Comparison3 : RelationalOperator  Operator=<=  OutDataTypeStr=boolean
  Comparison4 : RelationalOperator  OutDataTypeStr=boolean
  Constant1 : Constant  Value=CcSOP_CellVoltRngDiffHeal_V
  Constant10 : Constant  Value=CcSOP_CellVoltRngLowTime_MS
  Constant{4,6,11,14} (4 alike) : Constant  Value=SOP_RUNTIME_MS
  Constant12 : Constant  Value=SOP_CONST1000_NUMB
  Constant13 : Constant  Value=CcSOP_CellVoltRngUpLimit_V
  Constant15 : Constant  Value=CcSOP_CellVoltRngHighTime_MS
  Constant2 : Constant  Value=SOP_CONST1000_NUMB
  Constant3 : Constant  Value=CcSOP_CellVoltRngDiff_V
  Constant5 : Constant  Value=CcSOP_CellVoltLowLevel1Time_MS
  Constant7 : Constant  Value=CcSOP_CellVoltLowLevel1Time_MS
  Constant8 : Constant  Value=SOP_CONST1000_NUMB
  Data Type Conversion{1..6} (6 alike) : DataTypeConversion  OutDataTypeStr=fixdt(0,16,0.01,0)  RndMeth=Round
  Divide2 : Product  Inputs=*/  OutDataTypeStr=single
  Product2 : Product  Inputs=*/  OutDataTypeStr=single
  Product3 : Product  Inputs=*/  OutDataTypeStr=single
  Sum : Sum  OutDataTypeStr=Inherit: Inherit via back propagation  RndMeth=Zero
  Sum1 : Sum  OutDataTypeStr=Inherit: Inherit via back propagation  RndMeth=Zero
  LbSOP_DisChrgDetLevel1_flg : Outport
  LbSOP_DisChrgHealLevel1_flg : Outport  Port=2
  LbSOP_DisChrgFloorFlag_flg : Outport  Port=3
  LbSOP_ChrgFloorFlag_flg : Outport  Port=4
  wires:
  GcCDP_MinCellVolt_mV/1 -> Bus Creator/1  "GcCDP_MinCellVolt_mV"
  GcCDP_MinCellTemp_C/1 -> Bus Creator/2  "GcCDP_MinCellTemp_C"
  GcCDP_MaxCellVolt_mV/1 -> Bus Creator/3  "GcCDP_MaxCellVolt_mV"
  Bus Creator/1 -> Bus Selector3/1, Bus Selector1/1, Bus Selector/1, Bus Selector2/1
  3D_Config_Word/1 -> Sum/1, Data Type Conversion6/1, Sum1/1
  Constant3/1 -> Sum/2
  Sum/1 -> Data Type Conversion3/1
  Comparison1/1 -> BMSDelay/1
  Constant4/1 -> BMSDelay/2
  Constant5/1 -> BMSDelay/3
  BMSDelay/1 -> LbSOP_DisChrgDetLevel1_flg/1  "LbSOP_DisChrgDetLevel1_flg"
  Constant1/1 -> Sum1/2
  Sum1/1 -> Data Type Conversion5/1
  Constant7/1 -> BMSDelay1/3
  Constant6/1 -> BMSDelay1/2
  Comparison2/1 -> BMSDelay1/1
  BMSDelay1/1 -> LbSOP_DisChrgHealLevel1_flg/1  "LbSOP_DisChrgHealLevel1_flg"
  Constant8/1 -> Product2/2
  Bus Selector2/1 -> Product2/1  "<GcCDP_MinCellVolt_mV>"
  Product2/1 -> Data Type Conversion2/1
  Constant10/1 -> BMSDelay2/3
  Constant11/1 -> BMSDelay2/2
  Comparison3/1 -> BMSDelay2/1
  BMSDelay2/1 -> LbSOP_DisChrgFloorFlag_flg/1  "LbSOP_DisChrgFloorFlag_flg"
  Constant12/1 -> Product3/2
  Bus Selector3/1 -> Product3/1  "<GcCDP_MaxCellVolt_mV>"
  Product3/1 -> Data Type Conversion4/1
  Constant13/1 -> Comparison4/2
  Comparison4/1 -> BMSDelay3/1
  Constant14/1 -> BMSDelay3/2
  Constant15/1 -> BMSDelay3/3
  BMSDelay3/1 -> LbSOP_ChrgFloorFlag_flg/1  "LbSOP_ChrgFloorFlag_flg"
  Divide2/1 -> Data Type Conversion1/1
  Constant2/1 -> Divide2/2
  Data Type Conversion1/1 -> Comparison1/1, Comparison3/1
  Bus Selector1/1 -> Divide2/1  "<GcCDP_MinCellVolt_mV>"
  Data Type Conversion4/1 -> Comparison4/1
  Data Type Conversion2/1 -> Comparison2/2
  Data Type Conversion3/1 -> Comparison1/2
  Data Type Conversion5/1 -> Comparison2/1
  Data Type Conversion6/1 -> Comparison3/2
  GcSOH_PackSOH_pct/1 -> Bus Creator/4  "GcSOH_PackSOH_pct"
  GeUDS_CapSel_enum/1 -> Bus Creator/5  "GeUDS_CapSel_enum"
  Bus Selector/1 -> 3D_Config_Word/1  "<GeUDS_CapSel_enum>"
  Bus Selector/2 -> 3D_Config_Word/2  "<GcSOH_PackSOH_pct>"
  Bus Selector/3 -> 3D_Config_Word/3  "<GcCDP_MinCellTemp_C>"
